VERSION 5.8 ;
BUSBITCHARS "[]" ;
DIVIDERCHAR "/" ;
UNITS
    DATABASE MICRONS 1000 ;
END UNITS

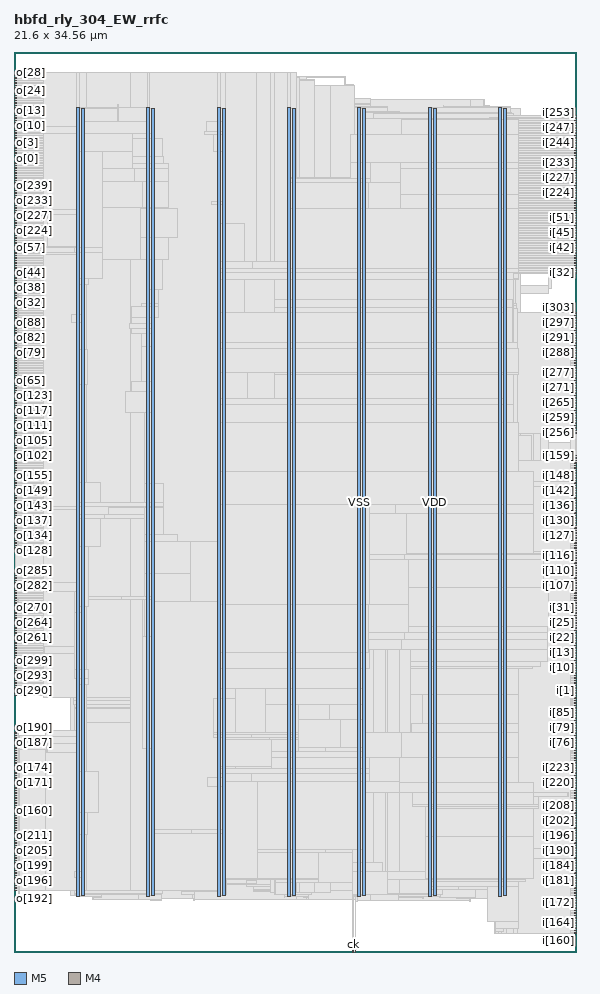
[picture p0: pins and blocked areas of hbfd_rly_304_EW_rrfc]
MACRO hbfd_rly_304_EW_rrfc
  FOREIGN hbfd_rly_304_EW_rrfc 0 0 ;
  CLASS BLOCK ;
  SIZE 21.6 BY 34.56 ;
  PIN ck
    DIRECTION INPUT ;
    USE SIGNAL ;
    PORT
      LAYER M5 ;
        RECT  13.008 0 13.032 0.084 ;
    END
  END ck
  PIN i[0]
    DIRECTION INPUT ;
    USE SIGNAL ;
    PORT
      LAYER M4 ;
        RECT  21.516 9.936 21.6 9.96 ;
    END
  END i[0]
  PIN i[100]
    DIRECTION INPUT ;
    USE SIGNAL ;
    PORT
      LAYER M4 ;
        RECT  21.516 13.392 21.6 13.416 ;
    END
  END i[100]
  PIN i[101]
    DIRECTION INPUT ;
    USE SIGNAL ;
    PORT
      LAYER M4 ;
        RECT  21.516 13.488 21.6 13.512 ;
    END
  END i[101]
  PIN i[102]
    DIRECTION INPUT ;
    USE SIGNAL ;
    PORT
      LAYER M4 ;
        RECT  21.516 13.584 21.6 13.608 ;
    END
  END i[102]
  PIN i[103]
    DIRECTION INPUT ;
    USE SIGNAL ;
    PORT
      LAYER M4 ;
        RECT  21.516 13.68 21.6 13.704 ;
    END
  END i[103]
  PIN i[104]
    DIRECTION INPUT ;
    USE SIGNAL ;
    PORT
      LAYER M4 ;
        RECT  21.516 13.776 21.6 13.8 ;
    END
  END i[104]
  PIN i[105]
    DIRECTION INPUT ;
    USE SIGNAL ;
    PORT
      LAYER M4 ;
        RECT  21.516 13.872 21.6 13.896 ;
    END
  END i[105]
  PIN i[106]
    DIRECTION INPUT ;
    USE SIGNAL ;
    PORT
      LAYER M4 ;
        RECT  21.516 13.968 21.6 13.992 ;
    END
  END i[106]
  PIN i[107]
    DIRECTION INPUT ;
    USE SIGNAL ;
    PORT
      LAYER M4 ;
        RECT  21.516 14.064 21.6 14.088 ;
    END
  END i[107]
  PIN i[108]
    DIRECTION INPUT ;
    USE SIGNAL ;
    PORT
      LAYER M4 ;
        RECT  21.516 14.16 21.6 14.184 ;
    END
  END i[108]
  PIN i[109]
    DIRECTION INPUT ;
    USE SIGNAL ;
    PORT
      LAYER M4 ;
        RECT  21.516 14.256 21.6 14.28 ;
    END
  END i[109]
  PIN i[10]
    DIRECTION INPUT ;
    USE SIGNAL ;
    PORT
      LAYER M4 ;
        RECT  21.516 10.896 21.6 10.92 ;
    END
  END i[10]
  PIN i[110]
    DIRECTION INPUT ;
    USE SIGNAL ;
    PORT
      LAYER M4 ;
        RECT  21.516 14.352 21.6 14.376 ;
    END
  END i[110]
  PIN i[111]
    DIRECTION INPUT ;
    USE SIGNAL ;
    PORT
      LAYER M4 ;
        RECT  21.516 14.448 21.6 14.472 ;
    END
  END i[111]
  PIN i[112]
    DIRECTION INPUT ;
    USE SIGNAL ;
    PORT
      LAYER M4 ;
        RECT  21.516 14.544 21.6 14.568 ;
    END
  END i[112]
  PIN i[113]
    DIRECTION INPUT ;
    USE SIGNAL ;
    PORT
      LAYER M4 ;
        RECT  21.516 14.64 21.6 14.664 ;
    END
  END i[113]
  PIN i[114]
    DIRECTION INPUT ;
    USE SIGNAL ;
    PORT
      LAYER M4 ;
        RECT  21.516 14.736 21.6 14.76 ;
    END
  END i[114]
  PIN i[115]
    DIRECTION INPUT ;
    USE SIGNAL ;
    PORT
      LAYER M4 ;
        RECT  21.516 14.832 21.6 14.856 ;
    END
  END i[115]
  PIN i[116]
    DIRECTION INPUT ;
    USE SIGNAL ;
    PORT
      LAYER M4 ;
        RECT  21.516 14.928 21.6 14.952 ;
    END
  END i[116]
  PIN i[117]
    DIRECTION INPUT ;
    USE SIGNAL ;
    PORT
      LAYER M4 ;
        RECT  21.516 15.024 21.6 15.048 ;
    END
  END i[117]
  PIN i[118]
    DIRECTION INPUT ;
    USE SIGNAL ;
    PORT
      LAYER M4 ;
        RECT  21.516 15.12 21.6 15.144 ;
    END
  END i[118]
  PIN i[119]
    DIRECTION INPUT ;
    USE SIGNAL ;
    PORT
      LAYER M4 ;
        RECT  21.516 15.216 21.6 15.24 ;
    END
  END i[119]
  PIN i[11]
    DIRECTION INPUT ;
    USE SIGNAL ;
    PORT
      LAYER M4 ;
        RECT  21.516 10.992 21.6 11.016 ;
    END
  END i[11]
  PIN i[120]
    DIRECTION INPUT ;
    USE SIGNAL ;
    PORT
      LAYER M4 ;
        RECT  21.516 15.312 21.6 15.336 ;
    END
  END i[120]
  PIN i[121]
    DIRECTION INPUT ;
    USE SIGNAL ;
    PORT
      LAYER M4 ;
        RECT  21.516 15.408 21.6 15.432 ;
    END
  END i[121]
  PIN i[122]
    DIRECTION INPUT ;
    USE SIGNAL ;
    PORT
      LAYER M4 ;
        RECT  21.516 15.504 21.6 15.528 ;
    END
  END i[122]
  PIN i[123]
    DIRECTION INPUT ;
    USE SIGNAL ;
    PORT
      LAYER M4 ;
        RECT  21.516 15.6 21.6 15.624 ;
    END
  END i[123]
  PIN i[124]
    DIRECTION INPUT ;
    USE SIGNAL ;
    PORT
      LAYER M4 ;
        RECT  21.516 15.696 21.6 15.72 ;
    END
  END i[124]
  PIN i[125]
    DIRECTION INPUT ;
    USE SIGNAL ;
    PORT
      LAYER M4 ;
        RECT  21.516 15.792 21.6 15.816 ;
    END
  END i[125]
  PIN i[126]
    DIRECTION INPUT ;
    USE SIGNAL ;
    PORT
      LAYER M4 ;
        RECT  21.516 15.888 21.6 15.912 ;
    END
  END i[126]
  PIN i[127]
    DIRECTION INPUT ;
    USE SIGNAL ;
    PORT
      LAYER M4 ;
        RECT  21.516 15.984 21.6 16.008 ;
    END
  END i[127]
  PIN i[128]
    DIRECTION INPUT ;
    USE SIGNAL ;
    PORT
      LAYER M4 ;
        RECT  21.516 16.08 21.6 16.104 ;
    END
  END i[128]
  PIN i[129]
    DIRECTION INPUT ;
    USE SIGNAL ;
    PORT
      LAYER M4 ;
        RECT  21.516 16.176 21.6 16.2 ;
    END
  END i[129]
  PIN i[12]
    DIRECTION INPUT ;
    USE SIGNAL ;
    PORT
      LAYER M4 ;
        RECT  21.516 11.088 21.6 11.112 ;
    END
  END i[12]
  PIN i[130]
    DIRECTION INPUT ;
    USE SIGNAL ;
    PORT
      LAYER M4 ;
        RECT  21.516 16.272 21.6 16.296 ;
    END
  END i[130]
  PIN i[131]
    DIRECTION INPUT ;
    USE SIGNAL ;
    PORT
      LAYER M4 ;
        RECT  21.516 16.368 21.6 16.392 ;
    END
  END i[131]
  PIN i[132]
    DIRECTION INPUT ;
    USE SIGNAL ;
    PORT
      LAYER M4 ;
        RECT  21.516 16.464 21.6 16.488 ;
    END
  END i[132]
  PIN i[133]
    DIRECTION INPUT ;
    USE SIGNAL ;
    PORT
      LAYER M4 ;
        RECT  21.516 16.56 21.6 16.584 ;
    END
  END i[133]
  PIN i[134]
    DIRECTION INPUT ;
    USE SIGNAL ;
    PORT
      LAYER M4 ;
        RECT  21.516 16.656 21.6 16.68 ;
    END
  END i[134]
  PIN i[135]
    DIRECTION INPUT ;
    USE SIGNAL ;
    PORT
      LAYER M4 ;
        RECT  21.516 16.752 21.6 16.776 ;
    END
  END i[135]
  PIN i[136]
    DIRECTION INPUT ;
    USE SIGNAL ;
    PORT
      LAYER M4 ;
        RECT  21.516 16.848 21.6 16.872 ;
    END
  END i[136]
  PIN i[137]
    DIRECTION INPUT ;
    USE SIGNAL ;
    PORT
      LAYER M4 ;
        RECT  21.516 16.944 21.6 16.968 ;
    END
  END i[137]
  PIN i[138]
    DIRECTION INPUT ;
    USE SIGNAL ;
    PORT
      LAYER M4 ;
        RECT  21.516 17.04 21.6 17.064 ;
    END
  END i[138]
  PIN i[139]
    DIRECTION INPUT ;
    USE SIGNAL ;
    PORT
      LAYER M4 ;
        RECT  21.516 17.136 21.6 17.16 ;
    END
  END i[139]
  PIN i[13]
    DIRECTION INPUT ;
    USE SIGNAL ;
    PORT
      LAYER M4 ;
        RECT  21.516 11.184 21.6 11.208 ;
    END
  END i[13]
  PIN i[140]
    DIRECTION INPUT ;
    USE SIGNAL ;
    PORT
      LAYER M4 ;
        RECT  21.516 17.232 21.6 17.256 ;
    END
  END i[140]
  PIN i[141]
    DIRECTION INPUT ;
    USE SIGNAL ;
    PORT
      LAYER M4 ;
        RECT  21.516 17.328 21.6 17.352 ;
    END
  END i[141]
  PIN i[142]
    DIRECTION INPUT ;
    USE SIGNAL ;
    PORT
      LAYER M4 ;
        RECT  21.516 17.424 21.6 17.448 ;
    END
  END i[142]
  PIN i[143]
    DIRECTION INPUT ;
    USE SIGNAL ;
    PORT
      LAYER M4 ;
        RECT  21.516 17.52 21.6 17.544 ;
    END
  END i[143]
  PIN i[144]
    DIRECTION INPUT ;
    USE SIGNAL ;
    PORT
      LAYER M4 ;
        RECT  21.516 17.616 21.6 17.64 ;
    END
  END i[144]
  PIN i[145]
    DIRECTION INPUT ;
    USE SIGNAL ;
    PORT
      LAYER M4 ;
        RECT  21.516 17.712 21.6 17.736 ;
    END
  END i[145]
  PIN i[146]
    DIRECTION INPUT ;
    USE SIGNAL ;
    PORT
      LAYER M4 ;
        RECT  21.516 17.808 21.6 17.832 ;
    END
  END i[146]
  PIN i[147]
    DIRECTION INPUT ;
    USE SIGNAL ;
    PORT
      LAYER M4 ;
        RECT  21.516 17.904 21.6 17.928 ;
    END
  END i[147]
  PIN i[148]
    DIRECTION INPUT ;
    USE SIGNAL ;
    PORT
      LAYER M4 ;
        RECT  21.516 18 21.6 18.024 ;
    END
  END i[148]
  PIN i[149]
    DIRECTION INPUT ;
    USE SIGNAL ;
    PORT
      LAYER M4 ;
        RECT  21.516 18.096 21.6 18.12 ;
    END
  END i[149]
  PIN i[14]
    DIRECTION INPUT ;
    USE SIGNAL ;
    PORT
      LAYER M4 ;
        RECT  21.516 11.28 21.6 11.304 ;
    END
  END i[14]
  PIN i[150]
    DIRECTION INPUT ;
    USE SIGNAL ;
    PORT
      LAYER M4 ;
        RECT  21.516 18.192 21.6 18.216 ;
    END
  END i[150]
  PIN i[151]
    DIRECTION INPUT ;
    USE SIGNAL ;
    PORT
      LAYER M4 ;
        RECT  21.516 18.288 21.6 18.312 ;
    END
  END i[151]
  PIN i[152]
    DIRECTION INPUT ;
    USE SIGNAL ;
    PORT
      LAYER M4 ;
        RECT  21.516 18.384 21.6 18.408 ;
    END
  END i[152]
  PIN i[153]
    DIRECTION INPUT ;
    USE SIGNAL ;
    PORT
      LAYER M4 ;
        RECT  21.516 18.48 21.6 18.504 ;
    END
  END i[153]
  PIN i[154]
    DIRECTION INPUT ;
    USE SIGNAL ;
    PORT
      LAYER M4 ;
        RECT  21.516 18.576 21.6 18.6 ;
    END
  END i[154]
  PIN i[155]
    DIRECTION INPUT ;
    USE SIGNAL ;
    PORT
      LAYER M4 ;
        RECT  21.516 18.672 21.6 18.696 ;
    END
  END i[155]
  PIN i[156]
    DIRECTION INPUT ;
    USE SIGNAL ;
    PORT
      LAYER M4 ;
        RECT  21.516 18.768 21.6 18.792 ;
    END
  END i[156]
  PIN i[157]
    DIRECTION INPUT ;
    USE SIGNAL ;
    PORT
      LAYER M4 ;
        RECT  21.516 18.864 21.6 18.888 ;
    END
  END i[157]
  PIN i[158]
    DIRECTION INPUT ;
    USE SIGNAL ;
    PORT
      LAYER M4 ;
        RECT  21.516 18.96 21.6 18.984 ;
    END
  END i[158]
  PIN i[159]
    DIRECTION INPUT ;
    USE SIGNAL ;
    PORT
      LAYER M4 ;
        RECT  21.516 19.056 21.6 19.08 ;
    END
  END i[159]
  PIN i[15]
    DIRECTION INPUT ;
    USE SIGNAL ;
    PORT
      LAYER M4 ;
        RECT  21.516 11.376 21.6 11.4 ;
    END
  END i[15]
  PIN i[160]
    DIRECTION INPUT ;
    USE SIGNAL ;
    PORT
      LAYER M4 ;
        RECT  21.516 0.72 21.6 0.744 ;
    END
  END i[160]
  PIN i[161]
    DIRECTION INPUT ;
    USE SIGNAL ;
    PORT
      LAYER M4 ;
        RECT  21.516 0.816 21.6 0.84 ;
    END
  END i[161]
  PIN i[162]
    DIRECTION INPUT ;
    USE SIGNAL ;
    PORT
      LAYER M4 ;
        RECT  21.516 0.912 21.6 0.936 ;
    END
  END i[162]
  PIN i[163]
    DIRECTION INPUT ;
    USE SIGNAL ;
    PORT
      LAYER M4 ;
        RECT  21.516 1.008 21.6 1.032 ;
    END
  END i[163]
  PIN i[164]
    DIRECTION INPUT ;
    USE SIGNAL ;
    PORT
      LAYER M4 ;
        RECT  21.516 1.104 21.6 1.128 ;
    END
  END i[164]
  PIN i[165]
    DIRECTION INPUT ;
    USE SIGNAL ;
    PORT
      LAYER M4 ;
        RECT  21.516 1.2 21.6 1.224 ;
    END
  END i[165]
  PIN i[166]
    DIRECTION INPUT ;
    USE SIGNAL ;
    PORT
      LAYER M4 ;
        RECT  21.516 1.296 21.6 1.32 ;
    END
  END i[166]
  PIN i[167]
    DIRECTION INPUT ;
    USE SIGNAL ;
    PORT
      LAYER M4 ;
        RECT  21.516 1.392 21.6 1.416 ;
    END
  END i[167]
  PIN i[168]
    DIRECTION INPUT ;
    USE SIGNAL ;
    PORT
      LAYER M4 ;
        RECT  21.516 1.488 21.6 1.512 ;
    END
  END i[168]
  PIN i[169]
    DIRECTION INPUT ;
    USE SIGNAL ;
    PORT
      LAYER M4 ;
        RECT  21.516 1.584 21.6 1.608 ;
    END
  END i[169]
  PIN i[16]
    DIRECTION INPUT ;
    USE SIGNAL ;
    PORT
      LAYER M4 ;
        RECT  21.516 11.472 21.6 11.496 ;
    END
  END i[16]
  PIN i[170]
    DIRECTION INPUT ;
    USE SIGNAL ;
    PORT
      LAYER M4 ;
        RECT  21.516 1.68 21.6 1.704 ;
    END
  END i[170]
  PIN i[171]
    DIRECTION INPUT ;
    USE SIGNAL ;
    PORT
      LAYER M4 ;
        RECT  21.516 1.776 21.6 1.8 ;
    END
  END i[171]
  PIN i[172]
    DIRECTION INPUT ;
    USE SIGNAL ;
    PORT
      LAYER M4 ;
        RECT  21.516 1.872 21.6 1.896 ;
    END
  END i[172]
  PIN i[173]
    DIRECTION INPUT ;
    USE SIGNAL ;
    PORT
      LAYER M4 ;
        RECT  21.516 1.968 21.6 1.992 ;
    END
  END i[173]
  PIN i[174]
    DIRECTION INPUT ;
    USE SIGNAL ;
    PORT
      LAYER M4 ;
        RECT  21.516 2.064 21.6 2.088 ;
    END
  END i[174]
  PIN i[175]
    DIRECTION INPUT ;
    USE SIGNAL ;
    PORT
      LAYER M4 ;
        RECT  21.516 2.16 21.6 2.184 ;
    END
  END i[175]
  PIN i[176]
    DIRECTION INPUT ;
    USE SIGNAL ;
    PORT
      LAYER M4 ;
        RECT  21.516 2.256 21.6 2.28 ;
    END
  END i[176]
  PIN i[177]
    DIRECTION INPUT ;
    USE SIGNAL ;
    PORT
      LAYER M4 ;
        RECT  21.516 2.352 21.6 2.376 ;
    END
  END i[177]
  PIN i[178]
    DIRECTION INPUT ;
    USE SIGNAL ;
    PORT
      LAYER M4 ;
        RECT  21.516 2.448 21.6 2.472 ;
    END
  END i[178]
  PIN i[179]
    DIRECTION INPUT ;
    USE SIGNAL ;
    PORT
      LAYER M4 ;
        RECT  21.516 2.544 21.6 2.568 ;
    END
  END i[179]
  PIN i[17]
    DIRECTION INPUT ;
    USE SIGNAL ;
    PORT
      LAYER M4 ;
        RECT  21.516 11.568 21.6 11.592 ;
    END
  END i[17]
  PIN i[180]
    DIRECTION INPUT ;
    USE SIGNAL ;
    PORT
      LAYER M4 ;
        RECT  21.516 2.64 21.6 2.664 ;
    END
  END i[180]
  PIN i[181]
    DIRECTION INPUT ;
    USE SIGNAL ;
    PORT
      LAYER M4 ;
        RECT  21.516 2.736 21.6 2.76 ;
    END
  END i[181]
  PIN i[182]
    DIRECTION INPUT ;
    USE SIGNAL ;
    PORT
      LAYER M4 ;
        RECT  21.516 2.832 21.6 2.856 ;
    END
  END i[182]
  PIN i[183]
    DIRECTION INPUT ;
    USE SIGNAL ;
    PORT
      LAYER M4 ;
        RECT  21.516 2.928 21.6 2.952 ;
    END
  END i[183]
  PIN i[184]
    DIRECTION INPUT ;
    USE SIGNAL ;
    PORT
      LAYER M4 ;
        RECT  21.516 3.024 21.6 3.048 ;
    END
  END i[184]
  PIN i[185]
    DIRECTION INPUT ;
    USE SIGNAL ;
    PORT
      LAYER M4 ;
        RECT  21.516 3.12 21.6 3.144 ;
    END
  END i[185]
  PIN i[186]
    DIRECTION INPUT ;
    USE SIGNAL ;
    PORT
      LAYER M4 ;
        RECT  21.516 3.216 21.6 3.24 ;
    END
  END i[186]
  PIN i[187]
    DIRECTION INPUT ;
    USE SIGNAL ;
    PORT
      LAYER M4 ;
        RECT  21.516 3.312 21.6 3.336 ;
    END
  END i[187]
  PIN i[188]
    DIRECTION INPUT ;
    USE SIGNAL ;
    PORT
      LAYER M4 ;
        RECT  21.516 3.408 21.6 3.432 ;
    END
  END i[188]
  PIN i[189]
    DIRECTION INPUT ;
    USE SIGNAL ;
    PORT
      LAYER M4 ;
        RECT  21.516 3.504 21.6 3.528 ;
    END
  END i[189]
  PIN i[18]
    DIRECTION INPUT ;
    USE SIGNAL ;
    PORT
      LAYER M4 ;
        RECT  21.516 11.664 21.6 11.688 ;
    END
  END i[18]
  PIN i[190]
    DIRECTION INPUT ;
    USE SIGNAL ;
    PORT
      LAYER M4 ;
        RECT  21.516 3.6 21.6 3.624 ;
    END
  END i[190]
  PIN i[191]
    DIRECTION INPUT ;
    USE SIGNAL ;
    PORT
      LAYER M4 ;
        RECT  21.516 3.696 21.6 3.72 ;
    END
  END i[191]
  PIN i[192]
    DIRECTION INPUT ;
    USE SIGNAL ;
    PORT
      LAYER M4 ;
        RECT  21.516 3.792 21.6 3.816 ;
    END
  END i[192]
  PIN i[193]
    DIRECTION INPUT ;
    USE SIGNAL ;
    PORT
      LAYER M4 ;
        RECT  21.516 3.888 21.6 3.912 ;
    END
  END i[193]
  PIN i[194]
    DIRECTION INPUT ;
    USE SIGNAL ;
    PORT
      LAYER M4 ;
        RECT  21.516 3.984 21.6 4.008 ;
    END
  END i[194]
  PIN i[195]
    DIRECTION INPUT ;
    USE SIGNAL ;
    PORT
      LAYER M4 ;
        RECT  21.516 4.08 21.6 4.104 ;
    END
  END i[195]
  PIN i[196]
    DIRECTION INPUT ;
    USE SIGNAL ;
    PORT
      LAYER M4 ;
        RECT  21.516 4.176 21.6 4.2 ;
    END
  END i[196]
  PIN i[197]
    DIRECTION INPUT ;
    USE SIGNAL ;
    PORT
      LAYER M4 ;
        RECT  21.516 4.272 21.6 4.296 ;
    END
  END i[197]
  PIN i[198]
    DIRECTION INPUT ;
    USE SIGNAL ;
    PORT
      LAYER M4 ;
        RECT  21.516 4.368 21.6 4.392 ;
    END
  END i[198]
  PIN i[199]
    DIRECTION INPUT ;
    USE SIGNAL ;
    PORT
      LAYER M4 ;
        RECT  21.516 4.464 21.6 4.488 ;
    END
  END i[199]
  PIN i[19]
    DIRECTION INPUT ;
    USE SIGNAL ;
    PORT
      LAYER M4 ;
        RECT  21.516 11.76 21.6 11.784 ;
    END
  END i[19]
  PIN i[1]
    DIRECTION INPUT ;
    USE SIGNAL ;
    PORT
      LAYER M4 ;
        RECT  21.516 10.032 21.6 10.056 ;
    END
  END i[1]
  PIN i[200]
    DIRECTION INPUT ;
    USE SIGNAL ;
    PORT
      LAYER M4 ;
        RECT  21.516 4.56 21.6 4.584 ;
    END
  END i[200]
  PIN i[201]
    DIRECTION INPUT ;
    USE SIGNAL ;
    PORT
      LAYER M4 ;
        RECT  21.516 4.656 21.6 4.68 ;
    END
  END i[201]
  PIN i[202]
    DIRECTION INPUT ;
    USE SIGNAL ;
    PORT
      LAYER M4 ;
        RECT  21.516 4.752 21.6 4.776 ;
    END
  END i[202]
  PIN i[203]
    DIRECTION INPUT ;
    USE SIGNAL ;
    PORT
      LAYER M4 ;
        RECT  21.516 4.848 21.6 4.872 ;
    END
  END i[203]
  PIN i[204]
    DIRECTION INPUT ;
    USE SIGNAL ;
    PORT
      LAYER M4 ;
        RECT  21.516 4.944 21.6 4.968 ;
    END
  END i[204]
  PIN i[205]
    DIRECTION INPUT ;
    USE SIGNAL ;
    PORT
      LAYER M4 ;
        RECT  21.516 5.04 21.6 5.064 ;
    END
  END i[205]
  PIN i[206]
    DIRECTION INPUT ;
    USE SIGNAL ;
    PORT
      LAYER M4 ;
        RECT  21.516 5.136 21.6 5.16 ;
    END
  END i[206]
  PIN i[207]
    DIRECTION INPUT ;
    USE SIGNAL ;
    PORT
      LAYER M4 ;
        RECT  21.516 5.232 21.6 5.256 ;
    END
  END i[207]
  PIN i[208]
    DIRECTION INPUT ;
    USE SIGNAL ;
    PORT
      LAYER M4 ;
        RECT  21.516 5.328 21.6 5.352 ;
    END
  END i[208]
  PIN i[209]
    DIRECTION INPUT ;
    USE SIGNAL ;
    PORT
      LAYER M4 ;
        RECT  21.516 5.424 21.6 5.448 ;
    END
  END i[209]
  PIN i[20]
    DIRECTION INPUT ;
    USE SIGNAL ;
    PORT
      LAYER M4 ;
        RECT  21.516 11.856 21.6 11.88 ;
    END
  END i[20]
  PIN i[210]
    DIRECTION INPUT ;
    USE SIGNAL ;
    PORT
      LAYER M4 ;
        RECT  21.516 5.52 21.6 5.544 ;
    END
  END i[210]
  PIN i[211]
    DIRECTION INPUT ;
    USE SIGNAL ;
    PORT
      LAYER M4 ;
        RECT  21.516 5.616 21.6 5.64 ;
    END
  END i[211]
  PIN i[212]
    DIRECTION INPUT ;
    USE SIGNAL ;
    PORT
      LAYER M4 ;
        RECT  21.516 5.712 21.6 5.736 ;
    END
  END i[212]
  PIN i[213]
    DIRECTION INPUT ;
    USE SIGNAL ;
    PORT
      LAYER M4 ;
        RECT  21.516 5.808 21.6 5.832 ;
    END
  END i[213]
  PIN i[214]
    DIRECTION INPUT ;
    USE SIGNAL ;
    PORT
      LAYER M4 ;
        RECT  21.516 5.904 21.6 5.928 ;
    END
  END i[214]
  PIN i[215]
    DIRECTION INPUT ;
    USE SIGNAL ;
    PORT
      LAYER M4 ;
        RECT  21.516 6 21.6 6.024 ;
    END
  END i[215]
  PIN i[216]
    DIRECTION INPUT ;
    USE SIGNAL ;
    PORT
      LAYER M4 ;
        RECT  21.516 6.096 21.6 6.12 ;
    END
  END i[216]
  PIN i[217]
    DIRECTION INPUT ;
    USE SIGNAL ;
    PORT
      LAYER M4 ;
        RECT  21.516 6.192 21.6 6.216 ;
    END
  END i[217]
  PIN i[218]
    DIRECTION INPUT ;
    USE SIGNAL ;
    PORT
      LAYER M4 ;
        RECT  21.516 6.288 21.6 6.312 ;
    END
  END i[218]
  PIN i[219]
    DIRECTION INPUT ;
    USE SIGNAL ;
    PORT
      LAYER M4 ;
        RECT  21.516 6.384 21.6 6.408 ;
    END
  END i[219]
  PIN i[21]
    DIRECTION INPUT ;
    USE SIGNAL ;
    PORT
      LAYER M4 ;
        RECT  21.516 11.952 21.6 11.976 ;
    END
  END i[21]
  PIN i[220]
    DIRECTION INPUT ;
    USE SIGNAL ;
    PORT
      LAYER M4 ;
        RECT  21.516 6.48 21.6 6.504 ;
    END
  END i[220]
  PIN i[221]
    DIRECTION INPUT ;
    USE SIGNAL ;
    PORT
      LAYER M4 ;
        RECT  21.516 6.576 21.6 6.6 ;
    END
  END i[221]
  PIN i[222]
    DIRECTION INPUT ;
    USE SIGNAL ;
    PORT
      LAYER M4 ;
        RECT  21.516 6.672 21.6 6.696 ;
    END
  END i[222]
  PIN i[223]
    DIRECTION INPUT ;
    USE SIGNAL ;
    PORT
      LAYER M4 ;
        RECT  21.516 6.768 21.6 6.792 ;
    END
  END i[223]
  PIN i[224]
    DIRECTION INPUT ;
    USE SIGNAL ;
    PORT
      LAYER M4 ;
        RECT  21.516 29.136 21.6 29.16 ;
    END
  END i[224]
  PIN i[225]
    DIRECTION INPUT ;
    USE SIGNAL ;
    PORT
      LAYER M4 ;
        RECT  21.516 29.232 21.6 29.256 ;
    END
  END i[225]
  PIN i[226]
    DIRECTION INPUT ;
    USE SIGNAL ;
    PORT
      LAYER M4 ;
        RECT  21.516 29.328 21.6 29.352 ;
    END
  END i[226]
  PIN i[227]
    DIRECTION INPUT ;
    USE SIGNAL ;
    PORT
      LAYER M4 ;
        RECT  21.516 29.424 21.6 29.448 ;
    END
  END i[227]
  PIN i[228]
    DIRECTION INPUT ;
    USE SIGNAL ;
    PORT
      LAYER M4 ;
        RECT  21.516 29.52 21.6 29.544 ;
    END
  END i[228]
  PIN i[229]
    DIRECTION INPUT ;
    USE SIGNAL ;
    PORT
      LAYER M4 ;
        RECT  21.516 29.616 21.6 29.64 ;
    END
  END i[229]
  PIN i[22]
    DIRECTION INPUT ;
    USE SIGNAL ;
    PORT
      LAYER M4 ;
        RECT  21.516 12.048 21.6 12.072 ;
    END
  END i[22]
  PIN i[230]
    DIRECTION INPUT ;
    USE SIGNAL ;
    PORT
      LAYER M4 ;
        RECT  21.516 29.712 21.6 29.736 ;
    END
  END i[230]
  PIN i[231]
    DIRECTION INPUT ;
    USE SIGNAL ;
    PORT
      LAYER M4 ;
        RECT  21.516 29.808 21.6 29.832 ;
    END
  END i[231]
  PIN i[232]
    DIRECTION INPUT ;
    USE SIGNAL ;
    PORT
      LAYER M4 ;
        RECT  21.516 29.904 21.6 29.928 ;
    END
  END i[232]
  PIN i[233]
    DIRECTION INPUT ;
    USE SIGNAL ;
    PORT
      LAYER M4 ;
        RECT  21.516 30 21.6 30.024 ;
    END
  END i[233]
  PIN i[234]
    DIRECTION INPUT ;
    USE SIGNAL ;
    PORT
      LAYER M4 ;
        RECT  21.516 30.096 21.6 30.12 ;
    END
  END i[234]
  PIN i[235]
    DIRECTION INPUT ;
    USE SIGNAL ;
    PORT
      LAYER M4 ;
        RECT  21.516 30.192 21.6 30.216 ;
    END
  END i[235]
  PIN i[236]
    DIRECTION INPUT ;
    USE SIGNAL ;
    PORT
      LAYER M4 ;
        RECT  21.516 30.288 21.6 30.312 ;
    END
  END i[236]
  PIN i[237]
    DIRECTION INPUT ;
    USE SIGNAL ;
    PORT
      LAYER M4 ;
        RECT  21.516 30.384 21.6 30.408 ;
    END
  END i[237]
  PIN i[238]
    DIRECTION INPUT ;
    USE SIGNAL ;
    PORT
      LAYER M4 ;
        RECT  21.516 30.48 21.6 30.504 ;
    END
  END i[238]
  PIN i[239]
    DIRECTION INPUT ;
    USE SIGNAL ;
    PORT
      LAYER M4 ;
        RECT  21.516 30.576 21.6 30.6 ;
    END
  END i[239]
  PIN i[23]
    DIRECTION INPUT ;
    USE SIGNAL ;
    PORT
      LAYER M4 ;
        RECT  21.516 12.144 21.6 12.168 ;
    END
  END i[23]
  PIN i[240]
    DIRECTION INPUT ;
    USE SIGNAL ;
    PORT
      LAYER M4 ;
        RECT  21.516 30.672 21.6 30.696 ;
    END
  END i[240]
  PIN i[241]
    DIRECTION INPUT ;
    USE SIGNAL ;
    PORT
      LAYER M4 ;
        RECT  21.516 30.768 21.6 30.792 ;
    END
  END i[241]
  PIN i[242]
    DIRECTION INPUT ;
    USE SIGNAL ;
    PORT
      LAYER M4 ;
        RECT  21.516 30.864 21.6 30.888 ;
    END
  END i[242]
  PIN i[243]
    DIRECTION INPUT ;
    USE SIGNAL ;
    PORT
      LAYER M4 ;
        RECT  21.516 30.96 21.6 30.984 ;
    END
  END i[243]
  PIN i[244]
    DIRECTION INPUT ;
    USE SIGNAL ;
    PORT
      LAYER M4 ;
        RECT  21.516 31.056 21.6 31.08 ;
    END
  END i[244]
  PIN i[245]
    DIRECTION INPUT ;
    USE SIGNAL ;
    PORT
      LAYER M4 ;
        RECT  21.516 31.152 21.6 31.176 ;
    END
  END i[245]
  PIN i[246]
    DIRECTION INPUT ;
    USE SIGNAL ;
    PORT
      LAYER M4 ;
        RECT  21.516 31.248 21.6 31.272 ;
    END
  END i[246]
  PIN i[247]
    DIRECTION INPUT ;
    USE SIGNAL ;
    PORT
      LAYER M4 ;
        RECT  21.516 31.344 21.6 31.368 ;
    END
  END i[247]
  PIN i[248]
    DIRECTION INPUT ;
    USE SIGNAL ;
    PORT
      LAYER M4 ;
        RECT  21.516 31.44 21.6 31.464 ;
    END
  END i[248]
  PIN i[249]
    DIRECTION INPUT ;
    USE SIGNAL ;
    PORT
      LAYER M4 ;
        RECT  21.516 31.536 21.6 31.56 ;
    END
  END i[249]
  PIN i[24]
    DIRECTION INPUT ;
    USE SIGNAL ;
    PORT
      LAYER M4 ;
        RECT  21.516 12.24 21.6 12.264 ;
    END
  END i[24]
  PIN i[250]
    DIRECTION INPUT ;
    USE SIGNAL ;
    PORT
      LAYER M4 ;
        RECT  21.516 31.632 21.6 31.656 ;
    END
  END i[250]
  PIN i[251]
    DIRECTION INPUT ;
    USE SIGNAL ;
    PORT
      LAYER M4 ;
        RECT  21.516 31.728 21.6 31.752 ;
    END
  END i[251]
  PIN i[252]
    DIRECTION INPUT ;
    USE SIGNAL ;
    PORT
      LAYER M4 ;
        RECT  21.516 31.824 21.6 31.848 ;
    END
  END i[252]
  PIN i[253]
    DIRECTION INPUT ;
    USE SIGNAL ;
    PORT
      LAYER M4 ;
        RECT  21.516 31.92 21.6 31.944 ;
    END
  END i[253]
  PIN i[254]
    DIRECTION INPUT ;
    USE SIGNAL ;
    PORT
      LAYER M4 ;
        RECT  21.516 32.016 21.6 32.04 ;
    END
  END i[254]
  PIN i[255]
    DIRECTION INPUT ;
    USE SIGNAL ;
    PORT
      LAYER M4 ;
        RECT  21.516 32.112 21.6 32.136 ;
    END
  END i[255]
  PIN i[256]
    DIRECTION INPUT ;
    USE SIGNAL ;
    PORT
      LAYER M4 ;
        RECT  21.516 19.92 21.6 19.944 ;
    END
  END i[256]
  PIN i[257]
    DIRECTION INPUT ;
    USE SIGNAL ;
    PORT
      LAYER M4 ;
        RECT  21.516 20.016 21.6 20.04 ;
    END
  END i[257]
  PIN i[258]
    DIRECTION INPUT ;
    USE SIGNAL ;
    PORT
      LAYER M4 ;
        RECT  21.516 20.112 21.6 20.136 ;
    END
  END i[258]
  PIN i[259]
    DIRECTION INPUT ;
    USE SIGNAL ;
    PORT
      LAYER M4 ;
        RECT  21.516 20.208 21.6 20.232 ;
    END
  END i[259]
  PIN i[25]
    DIRECTION INPUT ;
    USE SIGNAL ;
    PORT
      LAYER M4 ;
        RECT  21.516 12.336 21.6 12.36 ;
    END
  END i[25]
  PIN i[260]
    DIRECTION INPUT ;
    USE SIGNAL ;
    PORT
      LAYER M4 ;
        RECT  21.516 20.304 21.6 20.328 ;
    END
  END i[260]
  PIN i[261]
    DIRECTION INPUT ;
    USE SIGNAL ;
    PORT
      LAYER M4 ;
        RECT  21.516 20.4 21.6 20.424 ;
    END
  END i[261]
  PIN i[262]
    DIRECTION INPUT ;
    USE SIGNAL ;
    PORT
      LAYER M4 ;
        RECT  21.516 20.496 21.6 20.52 ;
    END
  END i[262]
  PIN i[263]
    DIRECTION INPUT ;
    USE SIGNAL ;
    PORT
      LAYER M4 ;
        RECT  21.516 20.592 21.6 20.616 ;
    END
  END i[263]
  PIN i[264]
    DIRECTION INPUT ;
    USE SIGNAL ;
    PORT
      LAYER M4 ;
        RECT  21.516 20.688 21.6 20.712 ;
    END
  END i[264]
  PIN i[265]
    DIRECTION INPUT ;
    USE SIGNAL ;
    PORT
      LAYER M4 ;
        RECT  21.516 20.784 21.6 20.808 ;
    END
  END i[265]
  PIN i[266]
    DIRECTION INPUT ;
    USE SIGNAL ;
    PORT
      LAYER M4 ;
        RECT  21.516 20.88 21.6 20.904 ;
    END
  END i[266]
  PIN i[267]
    DIRECTION INPUT ;
    USE SIGNAL ;
    PORT
      LAYER M4 ;
        RECT  21.516 20.976 21.6 21 ;
    END
  END i[267]
  PIN i[268]
    DIRECTION INPUT ;
    USE SIGNAL ;
    PORT
      LAYER M4 ;
        RECT  21.516 21.072 21.6 21.096 ;
    END
  END i[268]
  PIN i[269]
    DIRECTION INPUT ;
    USE SIGNAL ;
    PORT
      LAYER M4 ;
        RECT  21.516 21.168 21.6 21.192 ;
    END
  END i[269]
  PIN i[26]
    DIRECTION INPUT ;
    USE SIGNAL ;
    PORT
      LAYER M4 ;
        RECT  21.516 12.432 21.6 12.456 ;
    END
  END i[26]
  PIN i[270]
    DIRECTION INPUT ;
    USE SIGNAL ;
    PORT
      LAYER M4 ;
        RECT  21.516 21.264 21.6 21.288 ;
    END
  END i[270]
  PIN i[271]
    DIRECTION INPUT ;
    USE SIGNAL ;
    PORT
      LAYER M4 ;
        RECT  21.516 21.36 21.6 21.384 ;
    END
  END i[271]
  PIN i[272]
    DIRECTION INPUT ;
    USE SIGNAL ;
    PORT
      LAYER M4 ;
        RECT  21.516 21.456 21.6 21.48 ;
    END
  END i[272]
  PIN i[273]
    DIRECTION INPUT ;
    USE SIGNAL ;
    PORT
      LAYER M4 ;
        RECT  21.516 21.552 21.6 21.576 ;
    END
  END i[273]
  PIN i[274]
    DIRECTION INPUT ;
    USE SIGNAL ;
    PORT
      LAYER M4 ;
        RECT  21.516 21.648 21.6 21.672 ;
    END
  END i[274]
  PIN i[275]
    DIRECTION INPUT ;
    USE SIGNAL ;
    PORT
      LAYER M4 ;
        RECT  21.516 21.744 21.6 21.768 ;
    END
  END i[275]
  PIN i[276]
    DIRECTION INPUT ;
    USE SIGNAL ;
    PORT
      LAYER M4 ;
        RECT  21.516 21.84 21.6 21.864 ;
    END
  END i[276]
  PIN i[277]
    DIRECTION INPUT ;
    USE SIGNAL ;
    PORT
      LAYER M4 ;
        RECT  21.516 21.936 21.6 21.96 ;
    END
  END i[277]
  PIN i[278]
    DIRECTION INPUT ;
    USE SIGNAL ;
    PORT
      LAYER M4 ;
        RECT  21.516 22.032 21.6 22.056 ;
    END
  END i[278]
  PIN i[279]
    DIRECTION INPUT ;
    USE SIGNAL ;
    PORT
      LAYER M4 ;
        RECT  21.516 22.128 21.6 22.152 ;
    END
  END i[279]
  PIN i[27]
    DIRECTION INPUT ;
    USE SIGNAL ;
    PORT
      LAYER M4 ;
        RECT  21.516 12.528 21.6 12.552 ;
    END
  END i[27]
  PIN i[280]
    DIRECTION INPUT ;
    USE SIGNAL ;
    PORT
      LAYER M4 ;
        RECT  21.516 22.224 21.6 22.248 ;
    END
  END i[280]
  PIN i[281]
    DIRECTION INPUT ;
    USE SIGNAL ;
    PORT
      LAYER M4 ;
        RECT  21.516 22.32 21.6 22.344 ;
    END
  END i[281]
  PIN i[282]
    DIRECTION INPUT ;
    USE SIGNAL ;
    PORT
      LAYER M4 ;
        RECT  21.516 22.416 21.6 22.44 ;
    END
  END i[282]
  PIN i[283]
    DIRECTION INPUT ;
    USE SIGNAL ;
    PORT
      LAYER M4 ;
        RECT  21.516 22.512 21.6 22.536 ;
    END
  END i[283]
  PIN i[284]
    DIRECTION INPUT ;
    USE SIGNAL ;
    PORT
      LAYER M4 ;
        RECT  21.516 22.608 21.6 22.632 ;
    END
  END i[284]
  PIN i[285]
    DIRECTION INPUT ;
    USE SIGNAL ;
    PORT
      LAYER M4 ;
        RECT  21.516 22.704 21.6 22.728 ;
    END
  END i[285]
  PIN i[286]
    DIRECTION INPUT ;
    USE SIGNAL ;
    PORT
      LAYER M4 ;
        RECT  21.516 22.8 21.6 22.824 ;
    END
  END i[286]
  PIN i[287]
    DIRECTION INPUT ;
    USE SIGNAL ;
    PORT
      LAYER M4 ;
        RECT  21.516 22.896 21.6 22.92 ;
    END
  END i[287]
  PIN i[288]
    DIRECTION INPUT ;
    USE SIGNAL ;
    PORT
      LAYER M4 ;
        RECT  21.516 22.992 21.6 23.016 ;
    END
  END i[288]
  PIN i[289]
    DIRECTION INPUT ;
    USE SIGNAL ;
    PORT
      LAYER M4 ;
        RECT  21.516 23.088 21.6 23.112 ;
    END
  END i[289]
  PIN i[28]
    DIRECTION INPUT ;
    USE SIGNAL ;
    PORT
      LAYER M4 ;
        RECT  21.516 12.624 21.6 12.648 ;
    END
  END i[28]
  PIN i[290]
    DIRECTION INPUT ;
    USE SIGNAL ;
    PORT
      LAYER M4 ;
        RECT  21.516 23.184 21.6 23.208 ;
    END
  END i[290]
  PIN i[291]
    DIRECTION INPUT ;
    USE SIGNAL ;
    PORT
      LAYER M4 ;
        RECT  21.516 23.28 21.6 23.304 ;
    END
  END i[291]
  PIN i[292]
    DIRECTION INPUT ;
    USE SIGNAL ;
    PORT
      LAYER M4 ;
        RECT  21.516 23.376 21.6 23.4 ;
    END
  END i[292]
  PIN i[293]
    DIRECTION INPUT ;
    USE SIGNAL ;
    PORT
      LAYER M4 ;
        RECT  21.516 23.472 21.6 23.496 ;
    END
  END i[293]
  PIN i[294]
    DIRECTION INPUT ;
    USE SIGNAL ;
    PORT
      LAYER M4 ;
        RECT  21.516 23.568 21.6 23.592 ;
    END
  END i[294]
  PIN i[295]
    DIRECTION INPUT ;
    USE SIGNAL ;
    PORT
      LAYER M4 ;
        RECT  21.516 23.664 21.6 23.688 ;
    END
  END i[295]
  PIN i[296]
    DIRECTION INPUT ;
    USE SIGNAL ;
    PORT
      LAYER M4 ;
        RECT  21.516 23.76 21.6 23.784 ;
    END
  END i[296]
  PIN i[297]
    DIRECTION INPUT ;
    USE SIGNAL ;
    PORT
      LAYER M4 ;
        RECT  21.516 23.856 21.6 23.88 ;
    END
  END i[297]
  PIN i[298]
    DIRECTION INPUT ;
    USE SIGNAL ;
    PORT
      LAYER M4 ;
        RECT  21.516 23.952 21.6 23.976 ;
    END
  END i[298]
  PIN i[299]
    DIRECTION INPUT ;
    USE SIGNAL ;
    PORT
      LAYER M4 ;
        RECT  21.516 24.048 21.6 24.072 ;
    END
  END i[299]
  PIN i[29]
    DIRECTION INPUT ;
    USE SIGNAL ;
    PORT
      LAYER M4 ;
        RECT  21.516 12.72 21.6 12.744 ;
    END
  END i[29]
  PIN i[2]
    DIRECTION INPUT ;
    USE SIGNAL ;
    PORT
      LAYER M4 ;
        RECT  21.516 10.128 21.6 10.152 ;
    END
  END i[2]
  PIN i[300]
    DIRECTION INPUT ;
    USE SIGNAL ;
    PORT
      LAYER M4 ;
        RECT  21.516 24.144 21.6 24.168 ;
    END
  END i[300]
  PIN i[301]
    DIRECTION INPUT ;
    USE SIGNAL ;
    PORT
      LAYER M4 ;
        RECT  21.516 24.24 21.6 24.264 ;
    END
  END i[301]
  PIN i[302]
    DIRECTION INPUT ;
    USE SIGNAL ;
    PORT
      LAYER M4 ;
        RECT  21.516 24.336 21.6 24.36 ;
    END
  END i[302]
  PIN i[303]
    DIRECTION INPUT ;
    USE SIGNAL ;
    PORT
      LAYER M4 ;
        RECT  21.516 24.432 21.6 24.456 ;
    END
  END i[303]
  PIN i[30]
    DIRECTION INPUT ;
    USE SIGNAL ;
    PORT
      LAYER M4 ;
        RECT  21.516 12.816 21.6 12.84 ;
    END
  END i[30]
  PIN i[31]
    DIRECTION INPUT ;
    USE SIGNAL ;
    PORT
      LAYER M4 ;
        RECT  21.516 12.912 21.6 12.936 ;
    END
  END i[31]
  PIN i[32]
    DIRECTION INPUT ;
    USE SIGNAL ;
    PORT
      LAYER M4 ;
        RECT  21.516 26.064 21.6 26.088 ;
    END
  END i[32]
  PIN i[33]
    DIRECTION INPUT ;
    USE SIGNAL ;
    PORT
      LAYER M4 ;
        RECT  21.516 26.16 21.6 26.184 ;
    END
  END i[33]
  PIN i[34]
    DIRECTION INPUT ;
    USE SIGNAL ;
    PORT
      LAYER M4 ;
        RECT  21.516 26.256 21.6 26.28 ;
    END
  END i[34]
  PIN i[35]
    DIRECTION INPUT ;
    USE SIGNAL ;
    PORT
      LAYER M4 ;
        RECT  21.516 26.352 21.6 26.376 ;
    END
  END i[35]
  PIN i[36]
    DIRECTION INPUT ;
    USE SIGNAL ;
    PORT
      LAYER M4 ;
        RECT  21.516 26.448 21.6 26.472 ;
    END
  END i[36]
  PIN i[37]
    DIRECTION INPUT ;
    USE SIGNAL ;
    PORT
      LAYER M4 ;
        RECT  21.516 26.544 21.6 26.568 ;
    END
  END i[37]
  PIN i[38]
    DIRECTION INPUT ;
    USE SIGNAL ;
    PORT
      LAYER M4 ;
        RECT  21.516 26.64 21.6 26.664 ;
    END
  END i[38]
  PIN i[39]
    DIRECTION INPUT ;
    USE SIGNAL ;
    PORT
      LAYER M4 ;
        RECT  21.516 26.736 21.6 26.76 ;
    END
  END i[39]
  PIN i[3]
    DIRECTION INPUT ;
    USE SIGNAL ;
    PORT
      LAYER M4 ;
        RECT  21.516 10.224 21.6 10.248 ;
    END
  END i[3]
  PIN i[40]
    DIRECTION INPUT ;
    USE SIGNAL ;
    PORT
      LAYER M4 ;
        RECT  21.516 26.832 21.6 26.856 ;
    END
  END i[40]
  PIN i[41]
    DIRECTION INPUT ;
    USE SIGNAL ;
    PORT
      LAYER M4 ;
        RECT  21.516 26.928 21.6 26.952 ;
    END
  END i[41]
  PIN i[42]
    DIRECTION INPUT ;
    USE SIGNAL ;
    PORT
      LAYER M4 ;
        RECT  21.516 27.024 21.6 27.048 ;
    END
  END i[42]
  PIN i[43]
    DIRECTION INPUT ;
    USE SIGNAL ;
    PORT
      LAYER M4 ;
        RECT  21.516 27.12 21.6 27.144 ;
    END
  END i[43]
  PIN i[44]
    DIRECTION INPUT ;
    USE SIGNAL ;
    PORT
      LAYER M4 ;
        RECT  21.516 27.216 21.6 27.24 ;
    END
  END i[44]
  PIN i[45]
    DIRECTION INPUT ;
    USE SIGNAL ;
    PORT
      LAYER M4 ;
        RECT  21.516 27.312 21.6 27.336 ;
    END
  END i[45]
  PIN i[46]
    DIRECTION INPUT ;
    USE SIGNAL ;
    PORT
      LAYER M4 ;
        RECT  21.516 27.408 21.6 27.432 ;
    END
  END i[46]
  PIN i[47]
    DIRECTION INPUT ;
    USE SIGNAL ;
    PORT
      LAYER M4 ;
        RECT  21.516 27.504 21.6 27.528 ;
    END
  END i[47]
  PIN i[48]
    DIRECTION INPUT ;
    USE SIGNAL ;
    PORT
      LAYER M4 ;
        RECT  21.516 27.6 21.6 27.624 ;
    END
  END i[48]
  PIN i[49]
    DIRECTION INPUT ;
    USE SIGNAL ;
    PORT
      LAYER M4 ;
        RECT  21.516 27.696 21.6 27.72 ;
    END
  END i[49]
  PIN i[4]
    DIRECTION INPUT ;
    USE SIGNAL ;
    PORT
      LAYER M4 ;
        RECT  21.516 10.32 21.6 10.344 ;
    END
  END i[4]
  PIN i[50]
    DIRECTION INPUT ;
    USE SIGNAL ;
    PORT
      LAYER M4 ;
        RECT  21.516 27.792 21.6 27.816 ;
    END
  END i[50]
  PIN i[51]
    DIRECTION INPUT ;
    USE SIGNAL ;
    PORT
      LAYER M4 ;
        RECT  21.516 27.888 21.6 27.912 ;
    END
  END i[51]
  PIN i[52]
    DIRECTION INPUT ;
    USE SIGNAL ;
    PORT
      LAYER M4 ;
        RECT  21.516 27.984 21.6 28.008 ;
    END
  END i[52]
  PIN i[53]
    DIRECTION INPUT ;
    USE SIGNAL ;
    PORT
      LAYER M4 ;
        RECT  21.516 28.08 21.6 28.104 ;
    END
  END i[53]
  PIN i[54]
    DIRECTION INPUT ;
    USE SIGNAL ;
    PORT
      LAYER M4 ;
        RECT  21.516 28.176 21.6 28.2 ;
    END
  END i[54]
  PIN i[55]
    DIRECTION INPUT ;
    USE SIGNAL ;
    PORT
      LAYER M4 ;
        RECT  21.516 28.272 21.6 28.296 ;
    END
  END i[55]
  PIN i[56]
    DIRECTION INPUT ;
    USE SIGNAL ;
    PORT
      LAYER M4 ;
        RECT  21.516 28.368 21.6 28.392 ;
    END
  END i[56]
  PIN i[57]
    DIRECTION INPUT ;
    USE SIGNAL ;
    PORT
      LAYER M4 ;
        RECT  21.516 28.464 21.6 28.488 ;
    END
  END i[57]
  PIN i[58]
    DIRECTION INPUT ;
    USE SIGNAL ;
    PORT
      LAYER M4 ;
        RECT  21.516 28.56 21.6 28.584 ;
    END
  END i[58]
  PIN i[59]
    DIRECTION INPUT ;
    USE SIGNAL ;
    PORT
      LAYER M4 ;
        RECT  21.516 28.656 21.6 28.68 ;
    END
  END i[59]
  PIN i[5]
    DIRECTION INPUT ;
    USE SIGNAL ;
    PORT
      LAYER M4 ;
        RECT  21.516 10.416 21.6 10.44 ;
    END
  END i[5]
  PIN i[60]
    DIRECTION INPUT ;
    USE SIGNAL ;
    PORT
      LAYER M4 ;
        RECT  21.516 28.752 21.6 28.776 ;
    END
  END i[60]
  PIN i[61]
    DIRECTION INPUT ;
    USE SIGNAL ;
    PORT
      LAYER M4 ;
        RECT  21.516 28.848 21.6 28.872 ;
    END
  END i[61]
  PIN i[62]
    DIRECTION INPUT ;
    USE SIGNAL ;
    PORT
      LAYER M4 ;
        RECT  21.516 28.944 21.6 28.968 ;
    END
  END i[62]
  PIN i[63]
    DIRECTION INPUT ;
    USE SIGNAL ;
    PORT
      LAYER M4 ;
        RECT  21.516 29.04 21.6 29.064 ;
    END
  END i[63]
  PIN i[64]
    DIRECTION INPUT ;
    USE SIGNAL ;
    PORT
      LAYER M4 ;
        RECT  21.516 6.864 21.6 6.888 ;
    END
  END i[64]
  PIN i[65]
    DIRECTION INPUT ;
    USE SIGNAL ;
    PORT
      LAYER M4 ;
        RECT  21.516 6.96 21.6 6.984 ;
    END
  END i[65]
  PIN i[66]
    DIRECTION INPUT ;
    USE SIGNAL ;
    PORT
      LAYER M4 ;
        RECT  21.516 7.056 21.6 7.08 ;
    END
  END i[66]
  PIN i[67]
    DIRECTION INPUT ;
    USE SIGNAL ;
    PORT
      LAYER M4 ;
        RECT  21.516 7.152 21.6 7.176 ;
    END
  END i[67]
  PIN i[68]
    DIRECTION INPUT ;
    USE SIGNAL ;
    PORT
      LAYER M4 ;
        RECT  21.516 7.248 21.6 7.272 ;
    END
  END i[68]
  PIN i[69]
    DIRECTION INPUT ;
    USE SIGNAL ;
    PORT
      LAYER M4 ;
        RECT  21.516 7.344 21.6 7.368 ;
    END
  END i[69]
  PIN i[6]
    DIRECTION INPUT ;
    USE SIGNAL ;
    PORT
      LAYER M4 ;
        RECT  21.516 10.512 21.6 10.536 ;
    END
  END i[6]
  PIN i[70]
    DIRECTION INPUT ;
    USE SIGNAL ;
    PORT
      LAYER M4 ;
        RECT  21.516 7.44 21.6 7.464 ;
    END
  END i[70]
  PIN i[71]
    DIRECTION INPUT ;
    USE SIGNAL ;
    PORT
      LAYER M4 ;
        RECT  21.516 7.536 21.6 7.56 ;
    END
  END i[71]
  PIN i[72]
    DIRECTION INPUT ;
    USE SIGNAL ;
    PORT
      LAYER M4 ;
        RECT  21.516 7.632 21.6 7.656 ;
    END
  END i[72]
  PIN i[73]
    DIRECTION INPUT ;
    USE SIGNAL ;
    PORT
      LAYER M4 ;
        RECT  21.516 7.728 21.6 7.752 ;
    END
  END i[73]
  PIN i[74]
    DIRECTION INPUT ;
    USE SIGNAL ;
    PORT
      LAYER M4 ;
        RECT  21.516 7.824 21.6 7.848 ;
    END
  END i[74]
  PIN i[75]
    DIRECTION INPUT ;
    USE SIGNAL ;
    PORT
      LAYER M4 ;
        RECT  21.516 7.92 21.6 7.944 ;
    END
  END i[75]
  PIN i[76]
    DIRECTION INPUT ;
    USE SIGNAL ;
    PORT
      LAYER M4 ;
        RECT  21.516 8.016 21.6 8.04 ;
    END
  END i[76]
  PIN i[77]
    DIRECTION INPUT ;
    USE SIGNAL ;
    PORT
      LAYER M4 ;
        RECT  21.516 8.112 21.6 8.136 ;
    END
  END i[77]
  PIN i[78]
    DIRECTION INPUT ;
    USE SIGNAL ;
    PORT
      LAYER M4 ;
        RECT  21.516 8.208 21.6 8.232 ;
    END
  END i[78]
  PIN i[79]
    DIRECTION INPUT ;
    USE SIGNAL ;
    PORT
      LAYER M4 ;
        RECT  21.516 8.304 21.6 8.328 ;
    END
  END i[79]
  PIN i[7]
    DIRECTION INPUT ;
    USE SIGNAL ;
    PORT
      LAYER M4 ;
        RECT  21.516 10.608 21.6 10.632 ;
    END
  END i[7]
  PIN i[80]
    DIRECTION INPUT ;
    USE SIGNAL ;
    PORT
      LAYER M4 ;
        RECT  21.516 8.4 21.6 8.424 ;
    END
  END i[80]
  PIN i[81]
    DIRECTION INPUT ;
    USE SIGNAL ;
    PORT
      LAYER M4 ;
        RECT  21.516 8.496 21.6 8.52 ;
    END
  END i[81]
  PIN i[82]
    DIRECTION INPUT ;
    USE SIGNAL ;
    PORT
      LAYER M4 ;
        RECT  21.516 8.592 21.6 8.616 ;
    END
  END i[82]
  PIN i[83]
    DIRECTION INPUT ;
    USE SIGNAL ;
    PORT
      LAYER M4 ;
        RECT  21.516 8.688 21.6 8.712 ;
    END
  END i[83]
  PIN i[84]
    DIRECTION INPUT ;
    USE SIGNAL ;
    PORT
      LAYER M4 ;
        RECT  21.516 8.784 21.6 8.808 ;
    END
  END i[84]
  PIN i[85]
    DIRECTION INPUT ;
    USE SIGNAL ;
    PORT
      LAYER M4 ;
        RECT  21.516 8.88 21.6 8.904 ;
    END
  END i[85]
  PIN i[86]
    DIRECTION INPUT ;
    USE SIGNAL ;
    PORT
      LAYER M4 ;
        RECT  21.516 8.976 21.6 9 ;
    END
  END i[86]
  PIN i[87]
    DIRECTION INPUT ;
    USE SIGNAL ;
    PORT
      LAYER M4 ;
        RECT  21.516 9.072 21.6 9.096 ;
    END
  END i[87]
  PIN i[88]
    DIRECTION INPUT ;
    USE SIGNAL ;
    PORT
      LAYER M4 ;
        RECT  21.516 9.168 21.6 9.192 ;
    END
  END i[88]
  PIN i[89]
    DIRECTION INPUT ;
    USE SIGNAL ;
    PORT
      LAYER M4 ;
        RECT  21.516 9.264 21.6 9.288 ;
    END
  END i[89]
  PIN i[8]
    DIRECTION INPUT ;
    USE SIGNAL ;
    PORT
      LAYER M4 ;
        RECT  21.516 10.704 21.6 10.728 ;
    END
  END i[8]
  PIN i[90]
    DIRECTION INPUT ;
    USE SIGNAL ;
    PORT
      LAYER M4 ;
        RECT  21.516 9.36 21.6 9.384 ;
    END
  END i[90]
  PIN i[91]
    DIRECTION INPUT ;
    USE SIGNAL ;
    PORT
      LAYER M4 ;
        RECT  21.516 9.456 21.6 9.48 ;
    END
  END i[91]
  PIN i[92]
    DIRECTION INPUT ;
    USE SIGNAL ;
    PORT
      LAYER M4 ;
        RECT  21.516 9.552 21.6 9.576 ;
    END
  END i[92]
  PIN i[93]
    DIRECTION INPUT ;
    USE SIGNAL ;
    PORT
      LAYER M4 ;
        RECT  21.516 9.648 21.6 9.672 ;
    END
  END i[93]
  PIN i[94]
    DIRECTION INPUT ;
    USE SIGNAL ;
    PORT
      LAYER M4 ;
        RECT  21.516 9.744 21.6 9.768 ;
    END
  END i[94]
  PIN i[95]
    DIRECTION INPUT ;
    USE SIGNAL ;
    PORT
      LAYER M4 ;
        RECT  21.516 9.84 21.6 9.864 ;
    END
  END i[95]
  PIN i[96]
    DIRECTION INPUT ;
    USE SIGNAL ;
    PORT
      LAYER M4 ;
        RECT  21.516 13.008 21.6 13.032 ;
    END
  END i[96]
  PIN i[97]
    DIRECTION INPUT ;
    USE SIGNAL ;
    PORT
      LAYER M4 ;
        RECT  21.516 13.104 21.6 13.128 ;
    END
  END i[97]
  PIN i[98]
    DIRECTION INPUT ;
    USE SIGNAL ;
    PORT
      LAYER M4 ;
        RECT  21.516 13.2 21.6 13.224 ;
    END
  END i[98]
  PIN i[99]
    DIRECTION INPUT ;
    USE SIGNAL ;
    PORT
      LAYER M4 ;
        RECT  21.516 13.296 21.6 13.32 ;
    END
  END i[99]
  PIN i[9]
    DIRECTION INPUT ;
    USE SIGNAL ;
    PORT
      LAYER M4 ;
        RECT  21.516 10.8 21.6 10.824 ;
    END
  END i[9]
  PIN o[0]
    DIRECTION OUTPUT ;
    USE SIGNAL ;
    PORT
      LAYER M4 ;
        RECT  0 30.768 0.084 30.792 ;
    END
  END o[0]
  PIN o[100]
    DIRECTION OUTPUT ;
    USE SIGNAL ;
    PORT
      LAYER M4 ;
        RECT  0 18.864 0.084 18.888 ;
    END
  END o[100]
  PIN o[101]
    DIRECTION OUTPUT ;
    USE SIGNAL ;
    PORT
      LAYER M4 ;
        RECT  0 18.96 0.084 18.984 ;
    END
  END o[101]
  PIN o[102]
    DIRECTION OUTPUT ;
    USE SIGNAL ;
    PORT
      LAYER M4 ;
        RECT  0 19.056 0.084 19.08 ;
    END
  END o[102]
  PIN o[103]
    DIRECTION OUTPUT ;
    USE SIGNAL ;
    PORT
      LAYER M4 ;
        RECT  0 19.152 0.084 19.176 ;
    END
  END o[103]
  PIN o[104]
    DIRECTION OUTPUT ;
    USE SIGNAL ;
    PORT
      LAYER M4 ;
        RECT  0 19.248 0.084 19.272 ;
    END
  END o[104]
  PIN o[105]
    DIRECTION OUTPUT ;
    USE SIGNAL ;
    PORT
      LAYER M4 ;
        RECT  0 19.344 0.084 19.368 ;
    END
  END o[105]
  PIN o[106]
    DIRECTION OUTPUT ;
    USE SIGNAL ;
    PORT
      LAYER M4 ;
        RECT  0 19.44 0.084 19.464 ;
    END
  END o[106]
  PIN o[107]
    DIRECTION OUTPUT ;
    USE SIGNAL ;
    PORT
      LAYER M4 ;
        RECT  0 19.536 0.084 19.56 ;
    END
  END o[107]
  PIN o[108]
    DIRECTION OUTPUT ;
    USE SIGNAL ;
    PORT
      LAYER M4 ;
        RECT  0 19.632 0.084 19.656 ;
    END
  END o[108]
  PIN o[109]
    DIRECTION OUTPUT ;
    USE SIGNAL ;
    PORT
      LAYER M4 ;
        RECT  0 19.728 0.084 19.752 ;
    END
  END o[109]
  PIN o[10]
    DIRECTION OUTPUT ;
    USE SIGNAL ;
    PORT
      LAYER M4 ;
        RECT  0 31.728 0.084 31.752 ;
    END
  END o[10]
  PIN o[110]
    DIRECTION OUTPUT ;
    USE SIGNAL ;
    PORT
      LAYER M4 ;
        RECT  0 19.824 0.084 19.848 ;
    END
  END o[110]
  PIN o[111]
    DIRECTION OUTPUT ;
    USE SIGNAL ;
    PORT
      LAYER M4 ;
        RECT  0 19.92 0.084 19.944 ;
    END
  END o[111]
  PIN o[112]
    DIRECTION OUTPUT ;
    USE SIGNAL ;
    PORT
      LAYER M4 ;
        RECT  0 20.016 0.084 20.04 ;
    END
  END o[112]
  PIN o[113]
    DIRECTION OUTPUT ;
    USE SIGNAL ;
    PORT
      LAYER M4 ;
        RECT  0 20.112 0.084 20.136 ;
    END
  END o[113]
  PIN o[114]
    DIRECTION OUTPUT ;
    USE SIGNAL ;
    PORT
      LAYER M4 ;
        RECT  0 20.208 0.084 20.232 ;
    END
  END o[114]
  PIN o[115]
    DIRECTION OUTPUT ;
    USE SIGNAL ;
    PORT
      LAYER M4 ;
        RECT  0 20.304 0.084 20.328 ;
    END
  END o[115]
  PIN o[116]
    DIRECTION OUTPUT ;
    USE SIGNAL ;
    PORT
      LAYER M4 ;
        RECT  0 20.4 0.084 20.424 ;
    END
  END o[116]
  PIN o[117]
    DIRECTION OUTPUT ;
    USE SIGNAL ;
    PORT
      LAYER M4 ;
        RECT  0 20.496 0.084 20.52 ;
    END
  END o[117]
  PIN o[118]
    DIRECTION OUTPUT ;
    USE SIGNAL ;
    PORT
      LAYER M4 ;
        RECT  0 20.592 0.084 20.616 ;
    END
  END o[118]
  PIN o[119]
    DIRECTION OUTPUT ;
    USE SIGNAL ;
    PORT
      LAYER M4 ;
        RECT  0 20.688 0.084 20.712 ;
    END
  END o[119]
  PIN o[11]
    DIRECTION OUTPUT ;
    USE SIGNAL ;
    PORT
      LAYER M4 ;
        RECT  0 31.824 0.084 31.848 ;
    END
  END o[11]
  PIN o[120]
    DIRECTION OUTPUT ;
    USE SIGNAL ;
    PORT
      LAYER M4 ;
        RECT  0 20.784 0.084 20.808 ;
    END
  END o[120]
  PIN o[121]
    DIRECTION OUTPUT ;
    USE SIGNAL ;
    PORT
      LAYER M4 ;
        RECT  0 20.88 0.084 20.904 ;
    END
  END o[121]
  PIN o[122]
    DIRECTION OUTPUT ;
    USE SIGNAL ;
    PORT
      LAYER M4 ;
        RECT  0 20.976 0.084 21 ;
    END
  END o[122]
  PIN o[123]
    DIRECTION OUTPUT ;
    USE SIGNAL ;
    PORT
      LAYER M4 ;
        RECT  0 21.072 0.084 21.096 ;
    END
  END o[123]
  PIN o[124]
    DIRECTION OUTPUT ;
    USE SIGNAL ;
    PORT
      LAYER M4 ;
        RECT  0 21.168 0.084 21.192 ;
    END
  END o[124]
  PIN o[125]
    DIRECTION OUTPUT ;
    USE SIGNAL ;
    PORT
      LAYER M4 ;
        RECT  0 21.264 0.084 21.288 ;
    END
  END o[125]
  PIN o[126]
    DIRECTION OUTPUT ;
    USE SIGNAL ;
    PORT
      LAYER M4 ;
        RECT  0 21.36 0.084 21.384 ;
    END
  END o[126]
  PIN o[127]
    DIRECTION OUTPUT ;
    USE SIGNAL ;
    PORT
      LAYER M4 ;
        RECT  0 21.456 0.084 21.48 ;
    END
  END o[127]
  PIN o[128]
    DIRECTION OUTPUT ;
    USE SIGNAL ;
    PORT
      LAYER M4 ;
        RECT  0 15.408 0.084 15.432 ;
    END
  END o[128]
  PIN o[129]
    DIRECTION OUTPUT ;
    USE SIGNAL ;
    PORT
      LAYER M4 ;
        RECT  0 15.504 0.084 15.528 ;
    END
  END o[129]
  PIN o[12]
    DIRECTION OUTPUT ;
    USE SIGNAL ;
    PORT
      LAYER M4 ;
        RECT  0 31.92 0.084 31.944 ;
    END
  END o[12]
  PIN o[130]
    DIRECTION OUTPUT ;
    USE SIGNAL ;
    PORT
      LAYER M4 ;
        RECT  0 15.6 0.084 15.624 ;
    END
  END o[130]
  PIN o[131]
    DIRECTION OUTPUT ;
    USE SIGNAL ;
    PORT
      LAYER M4 ;
        RECT  0 15.696 0.084 15.72 ;
    END
  END o[131]
  PIN o[132]
    DIRECTION OUTPUT ;
    USE SIGNAL ;
    PORT
      LAYER M4 ;
        RECT  0 15.792 0.084 15.816 ;
    END
  END o[132]
  PIN o[133]
    DIRECTION OUTPUT ;
    USE SIGNAL ;
    PORT
      LAYER M4 ;
        RECT  0 15.888 0.084 15.912 ;
    END
  END o[133]
  PIN o[134]
    DIRECTION OUTPUT ;
    USE SIGNAL ;
    PORT
      LAYER M4 ;
        RECT  0 15.984 0.084 16.008 ;
    END
  END o[134]
  PIN o[135]
    DIRECTION OUTPUT ;
    USE SIGNAL ;
    PORT
      LAYER M4 ;
        RECT  0 16.08 0.084 16.104 ;
    END
  END o[135]
  PIN o[136]
    DIRECTION OUTPUT ;
    USE SIGNAL ;
    PORT
      LAYER M4 ;
        RECT  0 16.176 0.084 16.2 ;
    END
  END o[136]
  PIN o[137]
    DIRECTION OUTPUT ;
    USE SIGNAL ;
    PORT
      LAYER M4 ;
        RECT  0 16.272 0.084 16.296 ;
    END
  END o[137]
  PIN o[138]
    DIRECTION OUTPUT ;
    USE SIGNAL ;
    PORT
      LAYER M4 ;
        RECT  0 16.368 0.084 16.392 ;
    END
  END o[138]
  PIN o[139]
    DIRECTION OUTPUT ;
    USE SIGNAL ;
    PORT
      LAYER M4 ;
        RECT  0 16.464 0.084 16.488 ;
    END
  END o[139]
  PIN o[13]
    DIRECTION OUTPUT ;
    USE SIGNAL ;
    PORT
      LAYER M4 ;
        RECT  0 32.016 0.084 32.04 ;
    END
  END o[13]
  PIN o[140]
    DIRECTION OUTPUT ;
    USE SIGNAL ;
    PORT
      LAYER M4 ;
        RECT  0 16.56 0.084 16.584 ;
    END
  END o[140]
  PIN o[141]
    DIRECTION OUTPUT ;
    USE SIGNAL ;
    PORT
      LAYER M4 ;
        RECT  0 16.656 0.084 16.68 ;
    END
  END o[141]
  PIN o[142]
    DIRECTION OUTPUT ;
    USE SIGNAL ;
    PORT
      LAYER M4 ;
        RECT  0 16.752 0.084 16.776 ;
    END
  END o[142]
  PIN o[143]
    DIRECTION OUTPUT ;
    USE SIGNAL ;
    PORT
      LAYER M4 ;
        RECT  0 16.848 0.084 16.872 ;
    END
  END o[143]
  PIN o[144]
    DIRECTION OUTPUT ;
    USE SIGNAL ;
    PORT
      LAYER M4 ;
        RECT  0 16.944 0.084 16.968 ;
    END
  END o[144]
  PIN o[145]
    DIRECTION OUTPUT ;
    USE SIGNAL ;
    PORT
      LAYER M4 ;
        RECT  0 17.04 0.084 17.064 ;
    END
  END o[145]
  PIN o[146]
    DIRECTION OUTPUT ;
    USE SIGNAL ;
    PORT
      LAYER M4 ;
        RECT  0 17.136 0.084 17.16 ;
    END
  END o[146]
  PIN o[147]
    DIRECTION OUTPUT ;
    USE SIGNAL ;
    PORT
      LAYER M4 ;
        RECT  0 17.232 0.084 17.256 ;
    END
  END o[147]
  PIN o[148]
    DIRECTION OUTPUT ;
    USE SIGNAL ;
    PORT
      LAYER M4 ;
        RECT  0 17.328 0.084 17.352 ;
    END
  END o[148]
  PIN o[149]
    DIRECTION OUTPUT ;
    USE SIGNAL ;
    PORT
      LAYER M4 ;
        RECT  0 17.424 0.084 17.448 ;
    END
  END o[149]
  PIN o[14]
    DIRECTION OUTPUT ;
    USE SIGNAL ;
    PORT
      LAYER M4 ;
        RECT  0 32.112 0.084 32.136 ;
    END
  END o[14]
  PIN o[150]
    DIRECTION OUTPUT ;
    USE SIGNAL ;
    PORT
      LAYER M4 ;
        RECT  0 17.52 0.084 17.544 ;
    END
  END o[150]
  PIN o[151]
    DIRECTION OUTPUT ;
    USE SIGNAL ;
    PORT
      LAYER M4 ;
        RECT  0 17.616 0.084 17.64 ;
    END
  END o[151]
  PIN o[152]
    DIRECTION OUTPUT ;
    USE SIGNAL ;
    PORT
      LAYER M4 ;
        RECT  0 17.712 0.084 17.736 ;
    END
  END o[152]
  PIN o[153]
    DIRECTION OUTPUT ;
    USE SIGNAL ;
    PORT
      LAYER M4 ;
        RECT  0 17.808 0.084 17.832 ;
    END
  END o[153]
  PIN o[154]
    DIRECTION OUTPUT ;
    USE SIGNAL ;
    PORT
      LAYER M4 ;
        RECT  0 17.904 0.084 17.928 ;
    END
  END o[154]
  PIN o[155]
    DIRECTION OUTPUT ;
    USE SIGNAL ;
    PORT
      LAYER M4 ;
        RECT  0 18 0.084 18.024 ;
    END
  END o[155]
  PIN o[156]
    DIRECTION OUTPUT ;
    USE SIGNAL ;
    PORT
      LAYER M4 ;
        RECT  0 18.096 0.084 18.12 ;
    END
  END o[156]
  PIN o[157]
    DIRECTION OUTPUT ;
    USE SIGNAL ;
    PORT
      LAYER M4 ;
        RECT  0 18.192 0.084 18.216 ;
    END
  END o[157]
  PIN o[158]
    DIRECTION OUTPUT ;
    USE SIGNAL ;
    PORT
      LAYER M4 ;
        RECT  0 18.288 0.084 18.312 ;
    END
  END o[158]
  PIN o[159]
    DIRECTION OUTPUT ;
    USE SIGNAL ;
    PORT
      LAYER M4 ;
        RECT  0 18.384 0.084 18.408 ;
    END
  END o[159]
  PIN o[15]
    DIRECTION OUTPUT ;
    USE SIGNAL ;
    PORT
      LAYER M4 ;
        RECT  0 32.208 0.084 32.232 ;
    END
  END o[15]
  PIN o[160]
    DIRECTION OUTPUT ;
    USE SIGNAL ;
    PORT
      LAYER M4 ;
        RECT  0 5.424 0.084 5.448 ;
    END
  END o[160]
  PIN o[161]
    DIRECTION OUTPUT ;
    USE SIGNAL ;
    PORT
      LAYER M4 ;
        RECT  0 5.52 0.084 5.544 ;
    END
  END o[161]
  PIN o[162]
    DIRECTION OUTPUT ;
    USE SIGNAL ;
    PORT
      LAYER M4 ;
        RECT  0 5.616 0.084 5.64 ;
    END
  END o[162]
  PIN o[163]
    DIRECTION OUTPUT ;
    USE SIGNAL ;
    PORT
      LAYER M4 ;
        RECT  0 5.712 0.084 5.736 ;
    END
  END o[163]
  PIN o[164]
    DIRECTION OUTPUT ;
    USE SIGNAL ;
    PORT
      LAYER M4 ;
        RECT  0 5.808 0.084 5.832 ;
    END
  END o[164]
  PIN o[165]
    DIRECTION OUTPUT ;
    USE SIGNAL ;
    PORT
      LAYER M4 ;
        RECT  0 5.904 0.084 5.928 ;
    END
  END o[165]
  PIN o[166]
    DIRECTION OUTPUT ;
    USE SIGNAL ;
    PORT
      LAYER M4 ;
        RECT  0 6 0.084 6.024 ;
    END
  END o[166]
  PIN o[167]
    DIRECTION OUTPUT ;
    USE SIGNAL ;
    PORT
      LAYER M4 ;
        RECT  0 6.096 0.084 6.12 ;
    END
  END o[167]
  PIN o[168]
    DIRECTION OUTPUT ;
    USE SIGNAL ;
    PORT
      LAYER M4 ;
        RECT  0 6.192 0.084 6.216 ;
    END
  END o[168]
  PIN o[169]
    DIRECTION OUTPUT ;
    USE SIGNAL ;
    PORT
      LAYER M4 ;
        RECT  0 6.288 0.084 6.312 ;
    END
  END o[169]
  PIN o[16]
    DIRECTION OUTPUT ;
    USE SIGNAL ;
    PORT
      LAYER M4 ;
        RECT  0 32.304 0.084 32.328 ;
    END
  END o[16]
  PIN o[170]
    DIRECTION OUTPUT ;
    USE SIGNAL ;
    PORT
      LAYER M4 ;
        RECT  0 6.384 0.084 6.408 ;
    END
  END o[170]
  PIN o[171]
    DIRECTION OUTPUT ;
    USE SIGNAL ;
    PORT
      LAYER M4 ;
        RECT  0 6.48 0.084 6.504 ;
    END
  END o[171]
  PIN o[172]
    DIRECTION OUTPUT ;
    USE SIGNAL ;
    PORT
      LAYER M4 ;
        RECT  0 6.576 0.084 6.6 ;
    END
  END o[172]
  PIN o[173]
    DIRECTION OUTPUT ;
    USE SIGNAL ;
    PORT
      LAYER M4 ;
        RECT  0 6.672 0.084 6.696 ;
    END
  END o[173]
  PIN o[174]
    DIRECTION OUTPUT ;
    USE SIGNAL ;
    PORT
      LAYER M4 ;
        RECT  0 6.768 0.084 6.792 ;
    END
  END o[174]
  PIN o[175]
    DIRECTION OUTPUT ;
    USE SIGNAL ;
    PORT
      LAYER M4 ;
        RECT  0 6.864 0.084 6.888 ;
    END
  END o[175]
  PIN o[176]
    DIRECTION OUTPUT ;
    USE SIGNAL ;
    PORT
      LAYER M4 ;
        RECT  0 6.96 0.084 6.984 ;
    END
  END o[176]
  PIN o[177]
    DIRECTION OUTPUT ;
    USE SIGNAL ;
    PORT
      LAYER M4 ;
        RECT  0 7.056 0.084 7.08 ;
    END
  END o[177]
  PIN o[178]
    DIRECTION OUTPUT ;
    USE SIGNAL ;
    PORT
      LAYER M4 ;
        RECT  0 7.152 0.084 7.176 ;
    END
  END o[178]
  PIN o[179]
    DIRECTION OUTPUT ;
    USE SIGNAL ;
    PORT
      LAYER M4 ;
        RECT  0 7.248 0.084 7.272 ;
    END
  END o[179]
  PIN o[17]
    DIRECTION OUTPUT ;
    USE SIGNAL ;
    PORT
      LAYER M4 ;
        RECT  0 32.4 0.084 32.424 ;
    END
  END o[17]
  PIN o[180]
    DIRECTION OUTPUT ;
    USE SIGNAL ;
    PORT
      LAYER M4 ;
        RECT  0 7.344 0.084 7.368 ;
    END
  END o[180]
  PIN o[181]
    DIRECTION OUTPUT ;
    USE SIGNAL ;
    PORT
      LAYER M4 ;
        RECT  0 7.44 0.084 7.464 ;
    END
  END o[181]
  PIN o[182]
    DIRECTION OUTPUT ;
    USE SIGNAL ;
    PORT
      LAYER M4 ;
        RECT  0 7.536 0.084 7.56 ;
    END
  END o[182]
  PIN o[183]
    DIRECTION OUTPUT ;
    USE SIGNAL ;
    PORT
      LAYER M4 ;
        RECT  0 7.632 0.084 7.656 ;
    END
  END o[183]
  PIN o[184]
    DIRECTION OUTPUT ;
    USE SIGNAL ;
    PORT
      LAYER M4 ;
        RECT  0 7.728 0.084 7.752 ;
    END
  END o[184]
  PIN o[185]
    DIRECTION OUTPUT ;
    USE SIGNAL ;
    PORT
      LAYER M4 ;
        RECT  0 7.824 0.084 7.848 ;
    END
  END o[185]
  PIN o[186]
    DIRECTION OUTPUT ;
    USE SIGNAL ;
    PORT
      LAYER M4 ;
        RECT  0 7.92 0.084 7.944 ;
    END
  END o[186]
  PIN o[187]
    DIRECTION OUTPUT ;
    USE SIGNAL ;
    PORT
      LAYER M4 ;
        RECT  0 8.016 0.084 8.04 ;
    END
  END o[187]
  PIN o[188]
    DIRECTION OUTPUT ;
    USE SIGNAL ;
    PORT
      LAYER M4 ;
        RECT  0 8.112 0.084 8.136 ;
    END
  END o[188]
  PIN o[189]
    DIRECTION OUTPUT ;
    USE SIGNAL ;
    PORT
      LAYER M4 ;
        RECT  0 8.208 0.084 8.232 ;
    END
  END o[189]
  PIN o[18]
    DIRECTION OUTPUT ;
    USE SIGNAL ;
    PORT
      LAYER M4 ;
        RECT  0 32.496 0.084 32.52 ;
    END
  END o[18]
  PIN o[190]
    DIRECTION OUTPUT ;
    USE SIGNAL ;
    PORT
      LAYER M4 ;
        RECT  0 8.304 0.084 8.328 ;
    END
  END o[190]
  PIN o[191]
    DIRECTION OUTPUT ;
    USE SIGNAL ;
    PORT
      LAYER M4 ;
        RECT  0 8.4 0.084 8.424 ;
    END
  END o[191]
  PIN o[192]
    DIRECTION OUTPUT ;
    USE SIGNAL ;
    PORT
      LAYER M4 ;
        RECT  0 2.352 0.084 2.376 ;
    END
  END o[192]
  PIN o[193]
    DIRECTION OUTPUT ;
    USE SIGNAL ;
    PORT
      LAYER M4 ;
        RECT  0 2.448 0.084 2.472 ;
    END
  END o[193]
  PIN o[194]
    DIRECTION OUTPUT ;
    USE SIGNAL ;
    PORT
      LAYER M4 ;
        RECT  0 2.544 0.084 2.568 ;
    END
  END o[194]
  PIN o[195]
    DIRECTION OUTPUT ;
    USE SIGNAL ;
    PORT
      LAYER M4 ;
        RECT  0 2.64 0.084 2.664 ;
    END
  END o[195]
  PIN o[196]
    DIRECTION OUTPUT ;
    USE SIGNAL ;
    PORT
      LAYER M4 ;
        RECT  0 2.736 0.084 2.76 ;
    END
  END o[196]
  PIN o[197]
    DIRECTION OUTPUT ;
    USE SIGNAL ;
    PORT
      LAYER M4 ;
        RECT  0 2.832 0.084 2.856 ;
    END
  END o[197]
  PIN o[198]
    DIRECTION OUTPUT ;
    USE SIGNAL ;
    PORT
      LAYER M4 ;
        RECT  0 2.928 0.084 2.952 ;
    END
  END o[198]
  PIN o[199]
    DIRECTION OUTPUT ;
    USE SIGNAL ;
    PORT
      LAYER M4 ;
        RECT  0 3.024 0.084 3.048 ;
    END
  END o[199]
  PIN o[19]
    DIRECTION OUTPUT ;
    USE SIGNAL ;
    PORT
      LAYER M4 ;
        RECT  0 32.592 0.084 32.616 ;
    END
  END o[19]
  PIN o[1]
    DIRECTION OUTPUT ;
    USE SIGNAL ;
    PORT
      LAYER M4 ;
        RECT  0 30.864 0.084 30.888 ;
    END
  END o[1]
  PIN o[200]
    DIRECTION OUTPUT ;
    USE SIGNAL ;
    PORT
      LAYER M4 ;
        RECT  0 3.12 0.084 3.144 ;
    END
  END o[200]
  PIN o[201]
    DIRECTION OUTPUT ;
    USE SIGNAL ;
    PORT
      LAYER M4 ;
        RECT  0 3.216 0.084 3.24 ;
    END
  END o[201]
  PIN o[202]
    DIRECTION OUTPUT ;
    USE SIGNAL ;
    PORT
      LAYER M4 ;
        RECT  0 3.312 0.084 3.336 ;
    END
  END o[202]
  PIN o[203]
    DIRECTION OUTPUT ;
    USE SIGNAL ;
    PORT
      LAYER M4 ;
        RECT  0 3.408 0.084 3.432 ;
    END
  END o[203]
  PIN o[204]
    DIRECTION OUTPUT ;
    USE SIGNAL ;
    PORT
      LAYER M4 ;
        RECT  0 3.504 0.084 3.528 ;
    END
  END o[204]
  PIN o[205]
    DIRECTION OUTPUT ;
    USE SIGNAL ;
    PORT
      LAYER M4 ;
        RECT  0 3.6 0.084 3.624 ;
    END
  END o[205]
  PIN o[206]
    DIRECTION OUTPUT ;
    USE SIGNAL ;
    PORT
      LAYER M4 ;
        RECT  0 3.696 0.084 3.72 ;
    END
  END o[206]
  PIN o[207]
    DIRECTION OUTPUT ;
    USE SIGNAL ;
    PORT
      LAYER M4 ;
        RECT  0 3.792 0.084 3.816 ;
    END
  END o[207]
  PIN o[208]
    DIRECTION OUTPUT ;
    USE SIGNAL ;
    PORT
      LAYER M4 ;
        RECT  0 3.888 0.084 3.912 ;
    END
  END o[208]
  PIN o[209]
    DIRECTION OUTPUT ;
    USE SIGNAL ;
    PORT
      LAYER M4 ;
        RECT  0 3.984 0.084 4.008 ;
    END
  END o[209]
  PIN o[20]
    DIRECTION OUTPUT ;
    USE SIGNAL ;
    PORT
      LAYER M4 ;
        RECT  0 32.688 0.084 32.712 ;
    END
  END o[20]
  PIN o[210]
    DIRECTION OUTPUT ;
    USE SIGNAL ;
    PORT
      LAYER M4 ;
        RECT  0 4.08 0.084 4.104 ;
    END
  END o[210]
  PIN o[211]
    DIRECTION OUTPUT ;
    USE SIGNAL ;
    PORT
      LAYER M4 ;
        RECT  0 4.176 0.084 4.2 ;
    END
  END o[211]
  PIN o[212]
    DIRECTION OUTPUT ;
    USE SIGNAL ;
    PORT
      LAYER M4 ;
        RECT  0 4.272 0.084 4.296 ;
    END
  END o[212]
  PIN o[213]
    DIRECTION OUTPUT ;
    USE SIGNAL ;
    PORT
      LAYER M4 ;
        RECT  0 4.368 0.084 4.392 ;
    END
  END o[213]
  PIN o[214]
    DIRECTION OUTPUT ;
    USE SIGNAL ;
    PORT
      LAYER M4 ;
        RECT  0 4.464 0.084 4.488 ;
    END
  END o[214]
  PIN o[215]
    DIRECTION OUTPUT ;
    USE SIGNAL ;
    PORT
      LAYER M4 ;
        RECT  0 4.56 0.084 4.584 ;
    END
  END o[215]
  PIN o[216]
    DIRECTION OUTPUT ;
    USE SIGNAL ;
    PORT
      LAYER M4 ;
        RECT  0 4.656 0.084 4.68 ;
    END
  END o[216]
  PIN o[217]
    DIRECTION OUTPUT ;
    USE SIGNAL ;
    PORT
      LAYER M4 ;
        RECT  0 4.752 0.084 4.776 ;
    END
  END o[217]
  PIN o[218]
    DIRECTION OUTPUT ;
    USE SIGNAL ;
    PORT
      LAYER M4 ;
        RECT  0 4.848 0.084 4.872 ;
    END
  END o[218]
  PIN o[219]
    DIRECTION OUTPUT ;
    USE SIGNAL ;
    PORT
      LAYER M4 ;
        RECT  0 4.944 0.084 4.968 ;
    END
  END o[219]
  PIN o[21]
    DIRECTION OUTPUT ;
    USE SIGNAL ;
    PORT
      LAYER M4 ;
        RECT  0 32.784 0.084 32.808 ;
    END
  END o[21]
  PIN o[220]
    DIRECTION OUTPUT ;
    USE SIGNAL ;
    PORT
      LAYER M4 ;
        RECT  0 5.04 0.084 5.064 ;
    END
  END o[220]
  PIN o[221]
    DIRECTION OUTPUT ;
    USE SIGNAL ;
    PORT
      LAYER M4 ;
        RECT  0 5.136 0.084 5.16 ;
    END
  END o[221]
  PIN o[222]
    DIRECTION OUTPUT ;
    USE SIGNAL ;
    PORT
      LAYER M4 ;
        RECT  0 5.232 0.084 5.256 ;
    END
  END o[222]
  PIN o[223]
    DIRECTION OUTPUT ;
    USE SIGNAL ;
    PORT
      LAYER M4 ;
        RECT  0 5.328 0.084 5.352 ;
    END
  END o[223]
  PIN o[224]
    DIRECTION OUTPUT ;
    USE SIGNAL ;
    PORT
      LAYER M4 ;
        RECT  0 27.696 0.084 27.72 ;
    END
  END o[224]
  PIN o[225]
    DIRECTION OUTPUT ;
    USE SIGNAL ;
    PORT
      LAYER M4 ;
        RECT  0 27.792 0.084 27.816 ;
    END
  END o[225]
  PIN o[226]
    DIRECTION OUTPUT ;
    USE SIGNAL ;
    PORT
      LAYER M4 ;
        RECT  0 27.888 0.084 27.912 ;
    END
  END o[226]
  PIN o[227]
    DIRECTION OUTPUT ;
    USE SIGNAL ;
    PORT
      LAYER M4 ;
        RECT  0 27.984 0.084 28.008 ;
    END
  END o[227]
  PIN o[228]
    DIRECTION OUTPUT ;
    USE SIGNAL ;
    PORT
      LAYER M4 ;
        RECT  0 28.08 0.084 28.104 ;
    END
  END o[228]
  PIN o[229]
    DIRECTION OUTPUT ;
    USE SIGNAL ;
    PORT
      LAYER M4 ;
        RECT  0 28.176 0.084 28.2 ;
    END
  END o[229]
  PIN o[22]
    DIRECTION OUTPUT ;
    USE SIGNAL ;
    PORT
      LAYER M4 ;
        RECT  0 32.88 0.084 32.904 ;
    END
  END o[22]
  PIN o[230]
    DIRECTION OUTPUT ;
    USE SIGNAL ;
    PORT
      LAYER M4 ;
        RECT  0 28.272 0.084 28.296 ;
    END
  END o[230]
  PIN o[231]
    DIRECTION OUTPUT ;
    USE SIGNAL ;
    PORT
      LAYER M4 ;
        RECT  0 28.368 0.084 28.392 ;
    END
  END o[231]
  PIN o[232]
    DIRECTION OUTPUT ;
    USE SIGNAL ;
    PORT
      LAYER M4 ;
        RECT  0 28.464 0.084 28.488 ;
    END
  END o[232]
  PIN o[233]
    DIRECTION OUTPUT ;
    USE SIGNAL ;
    PORT
      LAYER M4 ;
        RECT  0 28.56 0.084 28.584 ;
    END
  END o[233]
  PIN o[234]
    DIRECTION OUTPUT ;
    USE SIGNAL ;
    PORT
      LAYER M4 ;
        RECT  0 28.656 0.084 28.68 ;
    END
  END o[234]
  PIN o[235]
    DIRECTION OUTPUT ;
    USE SIGNAL ;
    PORT
      LAYER M4 ;
        RECT  0 28.752 0.084 28.776 ;
    END
  END o[235]
  PIN o[236]
    DIRECTION OUTPUT ;
    USE SIGNAL ;
    PORT
      LAYER M4 ;
        RECT  0 28.848 0.084 28.872 ;
    END
  END o[236]
  PIN o[237]
    DIRECTION OUTPUT ;
    USE SIGNAL ;
    PORT
      LAYER M4 ;
        RECT  0 28.944 0.084 28.968 ;
    END
  END o[237]
  PIN o[238]
    DIRECTION OUTPUT ;
    USE SIGNAL ;
    PORT
      LAYER M4 ;
        RECT  0 29.04 0.084 29.064 ;
    END
  END o[238]
  PIN o[239]
    DIRECTION OUTPUT ;
    USE SIGNAL ;
    PORT
      LAYER M4 ;
        RECT  0 29.136 0.084 29.16 ;
    END
  END o[239]
  PIN o[23]
    DIRECTION OUTPUT ;
    USE SIGNAL ;
    PORT
      LAYER M4 ;
        RECT  0 32.976 0.084 33 ;
    END
  END o[23]
  PIN o[240]
    DIRECTION OUTPUT ;
    USE SIGNAL ;
    PORT
      LAYER M4 ;
        RECT  0 29.232 0.084 29.256 ;
    END
  END o[240]
  PIN o[241]
    DIRECTION OUTPUT ;
    USE SIGNAL ;
    PORT
      LAYER M4 ;
        RECT  0 29.328 0.084 29.352 ;
    END
  END o[241]
  PIN o[242]
    DIRECTION OUTPUT ;
    USE SIGNAL ;
    PORT
      LAYER M4 ;
        RECT  0 29.424 0.084 29.448 ;
    END
  END o[242]
  PIN o[243]
    DIRECTION OUTPUT ;
    USE SIGNAL ;
    PORT
      LAYER M4 ;
        RECT  0 29.52 0.084 29.544 ;
    END
  END o[243]
  PIN o[244]
    DIRECTION OUTPUT ;
    USE SIGNAL ;
    PORT
      LAYER M4 ;
        RECT  0 29.616 0.084 29.64 ;
    END
  END o[244]
  PIN o[245]
    DIRECTION OUTPUT ;
    USE SIGNAL ;
    PORT
      LAYER M4 ;
        RECT  0 29.712 0.084 29.736 ;
    END
  END o[245]
  PIN o[246]
    DIRECTION OUTPUT ;
    USE SIGNAL ;
    PORT
      LAYER M4 ;
        RECT  0 29.808 0.084 29.832 ;
    END
  END o[246]
  PIN o[247]
    DIRECTION OUTPUT ;
    USE SIGNAL ;
    PORT
      LAYER M4 ;
        RECT  0 29.904 0.084 29.928 ;
    END
  END o[247]
  PIN o[248]
    DIRECTION OUTPUT ;
    USE SIGNAL ;
    PORT
      LAYER M4 ;
        RECT  0 30 0.084 30.024 ;
    END
  END o[248]
  PIN o[249]
    DIRECTION OUTPUT ;
    USE SIGNAL ;
    PORT
      LAYER M4 ;
        RECT  0 30.096 0.084 30.12 ;
    END
  END o[249]
  PIN o[24]
    DIRECTION OUTPUT ;
    USE SIGNAL ;
    PORT
      LAYER M4 ;
        RECT  0 33.072 0.084 33.096 ;
    END
  END o[24]
  PIN o[250]
    DIRECTION OUTPUT ;
    USE SIGNAL ;
    PORT
      LAYER M4 ;
        RECT  0 30.192 0.084 30.216 ;
    END
  END o[250]
  PIN o[251]
    DIRECTION OUTPUT ;
    USE SIGNAL ;
    PORT
      LAYER M4 ;
        RECT  0 30.288 0.084 30.312 ;
    END
  END o[251]
  PIN o[252]
    DIRECTION OUTPUT ;
    USE SIGNAL ;
    PORT
      LAYER M4 ;
        RECT  0 30.384 0.084 30.408 ;
    END
  END o[252]
  PIN o[253]
    DIRECTION OUTPUT ;
    USE SIGNAL ;
    PORT
      LAYER M4 ;
        RECT  0 30.48 0.084 30.504 ;
    END
  END o[253]
  PIN o[254]
    DIRECTION OUTPUT ;
    USE SIGNAL ;
    PORT
      LAYER M4 ;
        RECT  0 30.576 0.084 30.6 ;
    END
  END o[254]
  PIN o[255]
    DIRECTION OUTPUT ;
    USE SIGNAL ;
    PORT
      LAYER M4 ;
        RECT  0 30.672 0.084 30.696 ;
    END
  END o[255]
  PIN o[256]
    DIRECTION OUTPUT ;
    USE SIGNAL ;
    PORT
      LAYER M4 ;
        RECT  0 11.568 0.084 11.592 ;
    END
  END o[256]
  PIN o[257]
    DIRECTION OUTPUT ;
    USE SIGNAL ;
    PORT
      LAYER M4 ;
        RECT  0 11.664 0.084 11.688 ;
    END
  END o[257]
  PIN o[258]
    DIRECTION OUTPUT ;
    USE SIGNAL ;
    PORT
      LAYER M4 ;
        RECT  0 11.76 0.084 11.784 ;
    END
  END o[258]
  PIN o[259]
    DIRECTION OUTPUT ;
    USE SIGNAL ;
    PORT
      LAYER M4 ;
        RECT  0 11.856 0.084 11.88 ;
    END
  END o[259]
  PIN o[25]
    DIRECTION OUTPUT ;
    USE SIGNAL ;
    PORT
      LAYER M4 ;
        RECT  0 33.168 0.084 33.192 ;
    END
  END o[25]
  PIN o[260]
    DIRECTION OUTPUT ;
    USE SIGNAL ;
    PORT
      LAYER M4 ;
        RECT  0 11.952 0.084 11.976 ;
    END
  END o[260]
  PIN o[261]
    DIRECTION OUTPUT ;
    USE SIGNAL ;
    PORT
      LAYER M4 ;
        RECT  0 12.048 0.084 12.072 ;
    END
  END o[261]
  PIN o[262]
    DIRECTION OUTPUT ;
    USE SIGNAL ;
    PORT
      LAYER M4 ;
        RECT  0 12.144 0.084 12.168 ;
    END
  END o[262]
  PIN o[263]
    DIRECTION OUTPUT ;
    USE SIGNAL ;
    PORT
      LAYER M4 ;
        RECT  0 12.24 0.084 12.264 ;
    END
  END o[263]
  PIN o[264]
    DIRECTION OUTPUT ;
    USE SIGNAL ;
    PORT
      LAYER M4 ;
        RECT  0 12.336 0.084 12.36 ;
    END
  END o[264]
  PIN o[265]
    DIRECTION OUTPUT ;
    USE SIGNAL ;
    PORT
      LAYER M4 ;
        RECT  0 12.432 0.084 12.456 ;
    END
  END o[265]
  PIN o[266]
    DIRECTION OUTPUT ;
    USE SIGNAL ;
    PORT
      LAYER M4 ;
        RECT  0 12.528 0.084 12.552 ;
    END
  END o[266]
  PIN o[267]
    DIRECTION OUTPUT ;
    USE SIGNAL ;
    PORT
      LAYER M4 ;
        RECT  0 12.624 0.084 12.648 ;
    END
  END o[267]
  PIN o[268]
    DIRECTION OUTPUT ;
    USE SIGNAL ;
    PORT
      LAYER M4 ;
        RECT  0 12.72 0.084 12.744 ;
    END
  END o[268]
  PIN o[269]
    DIRECTION OUTPUT ;
    USE SIGNAL ;
    PORT
      LAYER M4 ;
        RECT  0 12.816 0.084 12.84 ;
    END
  END o[269]
  PIN o[26]
    DIRECTION OUTPUT ;
    USE SIGNAL ;
    PORT
      LAYER M4 ;
        RECT  0 33.264 0.084 33.288 ;
    END
  END o[26]
  PIN o[270]
    DIRECTION OUTPUT ;
    USE SIGNAL ;
    PORT
      LAYER M4 ;
        RECT  0 12.912 0.084 12.936 ;
    END
  END o[270]
  PIN o[271]
    DIRECTION OUTPUT ;
    USE SIGNAL ;
    PORT
      LAYER M4 ;
        RECT  0 13.008 0.084 13.032 ;
    END
  END o[271]
  PIN o[272]
    DIRECTION OUTPUT ;
    USE SIGNAL ;
    PORT
      LAYER M4 ;
        RECT  0 13.104 0.084 13.128 ;
    END
  END o[272]
  PIN o[273]
    DIRECTION OUTPUT ;
    USE SIGNAL ;
    PORT
      LAYER M4 ;
        RECT  0 13.2 0.084 13.224 ;
    END
  END o[273]
  PIN o[274]
    DIRECTION OUTPUT ;
    USE SIGNAL ;
    PORT
      LAYER M4 ;
        RECT  0 13.296 0.084 13.32 ;
    END
  END o[274]
  PIN o[275]
    DIRECTION OUTPUT ;
    USE SIGNAL ;
    PORT
      LAYER M4 ;
        RECT  0 13.392 0.084 13.416 ;
    END
  END o[275]
  PIN o[276]
    DIRECTION OUTPUT ;
    USE SIGNAL ;
    PORT
      LAYER M4 ;
        RECT  0 13.488 0.084 13.512 ;
    END
  END o[276]
  PIN o[277]
    DIRECTION OUTPUT ;
    USE SIGNAL ;
    PORT
      LAYER M4 ;
        RECT  0 13.584 0.084 13.608 ;
    END
  END o[277]
  PIN o[278]
    DIRECTION OUTPUT ;
    USE SIGNAL ;
    PORT
      LAYER M4 ;
        RECT  0 13.68 0.084 13.704 ;
    END
  END o[278]
  PIN o[279]
    DIRECTION OUTPUT ;
    USE SIGNAL ;
    PORT
      LAYER M4 ;
        RECT  0 13.776 0.084 13.8 ;
    END
  END o[279]
  PIN o[27]
    DIRECTION OUTPUT ;
    USE SIGNAL ;
    PORT
      LAYER M4 ;
        RECT  0 33.36 0.084 33.384 ;
    END
  END o[27]
  PIN o[280]
    DIRECTION OUTPUT ;
    USE SIGNAL ;
    PORT
      LAYER M4 ;
        RECT  0 13.872 0.084 13.896 ;
    END
  END o[280]
  PIN o[281]
    DIRECTION OUTPUT ;
    USE SIGNAL ;
    PORT
      LAYER M4 ;
        RECT  0 13.968 0.084 13.992 ;
    END
  END o[281]
  PIN o[282]
    DIRECTION OUTPUT ;
    USE SIGNAL ;
    PORT
      LAYER M4 ;
        RECT  0 14.064 0.084 14.088 ;
    END
  END o[282]
  PIN o[283]
    DIRECTION OUTPUT ;
    USE SIGNAL ;
    PORT
      LAYER M4 ;
        RECT  0 14.16 0.084 14.184 ;
    END
  END o[283]
  PIN o[284]
    DIRECTION OUTPUT ;
    USE SIGNAL ;
    PORT
      LAYER M4 ;
        RECT  0 14.256 0.084 14.28 ;
    END
  END o[284]
  PIN o[285]
    DIRECTION OUTPUT ;
    USE SIGNAL ;
    PORT
      LAYER M4 ;
        RECT  0 14.352 0.084 14.376 ;
    END
  END o[285]
  PIN o[286]
    DIRECTION OUTPUT ;
    USE SIGNAL ;
    PORT
      LAYER M4 ;
        RECT  0 14.448 0.084 14.472 ;
    END
  END o[286]
  PIN o[287]
    DIRECTION OUTPUT ;
    USE SIGNAL ;
    PORT
      LAYER M4 ;
        RECT  0 14.544 0.084 14.568 ;
    END
  END o[287]
  PIN o[288]
    DIRECTION OUTPUT ;
    USE SIGNAL ;
    PORT
      LAYER M4 ;
        RECT  0 9.84 0.084 9.864 ;
    END
  END o[288]
  PIN o[289]
    DIRECTION OUTPUT ;
    USE SIGNAL ;
    PORT
      LAYER M4 ;
        RECT  0 9.936 0.084 9.96 ;
    END
  END o[289]
  PIN o[28]
    DIRECTION OUTPUT ;
    USE SIGNAL ;
    PORT
      LAYER M4 ;
        RECT  0 33.456 0.084 33.48 ;
    END
  END o[28]
  PIN o[290]
    DIRECTION OUTPUT ;
    USE SIGNAL ;
    PORT
      LAYER M4 ;
        RECT  0 10.032 0.084 10.056 ;
    END
  END o[290]
  PIN o[291]
    DIRECTION OUTPUT ;
    USE SIGNAL ;
    PORT
      LAYER M4 ;
        RECT  0 10.128 0.084 10.152 ;
    END
  END o[291]
  PIN o[292]
    DIRECTION OUTPUT ;
    USE SIGNAL ;
    PORT
      LAYER M4 ;
        RECT  0 10.224 0.084 10.248 ;
    END
  END o[292]
  PIN o[293]
    DIRECTION OUTPUT ;
    USE SIGNAL ;
    PORT
      LAYER M4 ;
        RECT  0 10.32 0.084 10.344 ;
    END
  END o[293]
  PIN o[294]
    DIRECTION OUTPUT ;
    USE SIGNAL ;
    PORT
      LAYER M4 ;
        RECT  0 10.416 0.084 10.44 ;
    END
  END o[294]
  PIN o[295]
    DIRECTION OUTPUT ;
    USE SIGNAL ;
    PORT
      LAYER M4 ;
        RECT  0 10.512 0.084 10.536 ;
    END
  END o[295]
  PIN o[296]
    DIRECTION OUTPUT ;
    USE SIGNAL ;
    PORT
      LAYER M4 ;
        RECT  0 10.608 0.084 10.632 ;
    END
  END o[296]
  PIN o[297]
    DIRECTION OUTPUT ;
    USE SIGNAL ;
    PORT
      LAYER M4 ;
        RECT  0 10.704 0.084 10.728 ;
    END
  END o[297]
  PIN o[298]
    DIRECTION OUTPUT ;
    USE SIGNAL ;
    PORT
      LAYER M4 ;
        RECT  0 10.8 0.084 10.824 ;
    END
  END o[298]
  PIN o[299]
    DIRECTION OUTPUT ;
    USE SIGNAL ;
    PORT
      LAYER M4 ;
        RECT  0 10.896 0.084 10.92 ;
    END
  END o[299]
  PIN o[29]
    DIRECTION OUTPUT ;
    USE SIGNAL ;
    PORT
      LAYER M4 ;
        RECT  0 33.552 0.084 33.576 ;
    END
  END o[29]
  PIN o[2]
    DIRECTION OUTPUT ;
    USE SIGNAL ;
    PORT
      LAYER M4 ;
        RECT  0 30.96 0.084 30.984 ;
    END
  END o[2]
  PIN o[300]
    DIRECTION OUTPUT ;
    USE SIGNAL ;
    PORT
      LAYER M4 ;
        RECT  0 10.992 0.084 11.016 ;
    END
  END o[300]
  PIN o[301]
    DIRECTION OUTPUT ;
    USE SIGNAL ;
    PORT
      LAYER M4 ;
        RECT  0 11.088 0.084 11.112 ;
    END
  END o[301]
  PIN o[302]
    DIRECTION OUTPUT ;
    USE SIGNAL ;
    PORT
      LAYER M4 ;
        RECT  0 11.184 0.084 11.208 ;
    END
  END o[302]
  PIN o[303]
    DIRECTION OUTPUT ;
    USE SIGNAL ;
    PORT
      LAYER M4 ;
        RECT  0 11.28 0.084 11.304 ;
    END
  END o[303]
  PIN o[30]
    DIRECTION OUTPUT ;
    USE SIGNAL ;
    PORT
      LAYER M4 ;
        RECT  0 33.648 0.084 33.672 ;
    END
  END o[30]
  PIN o[31]
    DIRECTION OUTPUT ;
    USE SIGNAL ;
    PORT
      LAYER M4 ;
        RECT  0 33.744 0.084 33.768 ;
    END
  END o[31]
  PIN o[32]
    DIRECTION OUTPUT ;
    USE SIGNAL ;
    PORT
      LAYER M4 ;
        RECT  0 24.624 0.084 24.648 ;
    END
  END o[32]
  PIN o[33]
    DIRECTION OUTPUT ;
    USE SIGNAL ;
    PORT
      LAYER M4 ;
        RECT  0 24.72 0.084 24.744 ;
    END
  END o[33]
  PIN o[34]
    DIRECTION OUTPUT ;
    USE SIGNAL ;
    PORT
      LAYER M4 ;
        RECT  0 24.816 0.084 24.84 ;
    END
  END o[34]
  PIN o[35]
    DIRECTION OUTPUT ;
    USE SIGNAL ;
    PORT
      LAYER M4 ;
        RECT  0 24.912 0.084 24.936 ;
    END
  END o[35]
  PIN o[36]
    DIRECTION OUTPUT ;
    USE SIGNAL ;
    PORT
      LAYER M4 ;
        RECT  0 25.008 0.084 25.032 ;
    END
  END o[36]
  PIN o[37]
    DIRECTION OUTPUT ;
    USE SIGNAL ;
    PORT
      LAYER M4 ;
        RECT  0 25.104 0.084 25.128 ;
    END
  END o[37]
  PIN o[38]
    DIRECTION OUTPUT ;
    USE SIGNAL ;
    PORT
      LAYER M4 ;
        RECT  0 25.2 0.084 25.224 ;
    END
  END o[38]
  PIN o[39]
    DIRECTION OUTPUT ;
    USE SIGNAL ;
    PORT
      LAYER M4 ;
        RECT  0 25.296 0.084 25.32 ;
    END
  END o[39]
  PIN o[3]
    DIRECTION OUTPUT ;
    USE SIGNAL ;
    PORT
      LAYER M4 ;
        RECT  0 31.056 0.084 31.08 ;
    END
  END o[3]
  PIN o[40]
    DIRECTION OUTPUT ;
    USE SIGNAL ;
    PORT
      LAYER M4 ;
        RECT  0 25.392 0.084 25.416 ;
    END
  END o[40]
  PIN o[41]
    DIRECTION OUTPUT ;
    USE SIGNAL ;
    PORT
      LAYER M4 ;
        RECT  0 25.488 0.084 25.512 ;
    END
  END o[41]
  PIN o[42]
    DIRECTION OUTPUT ;
    USE SIGNAL ;
    PORT
      LAYER M4 ;
        RECT  0 25.584 0.084 25.608 ;
    END
  END o[42]
  PIN o[43]
    DIRECTION OUTPUT ;
    USE SIGNAL ;
    PORT
      LAYER M4 ;
        RECT  0 25.68 0.084 25.704 ;
    END
  END o[43]
  PIN o[44]
    DIRECTION OUTPUT ;
    USE SIGNAL ;
    PORT
      LAYER M4 ;
        RECT  0 25.776 0.084 25.8 ;
    END
  END o[44]
  PIN o[45]
    DIRECTION OUTPUT ;
    USE SIGNAL ;
    PORT
      LAYER M4 ;
        RECT  0 25.872 0.084 25.896 ;
    END
  END o[45]
  PIN o[46]
    DIRECTION OUTPUT ;
    USE SIGNAL ;
    PORT
      LAYER M4 ;
        RECT  0 25.968 0.084 25.992 ;
    END
  END o[46]
  PIN o[47]
    DIRECTION OUTPUT ;
    USE SIGNAL ;
    PORT
      LAYER M4 ;
        RECT  0 26.064 0.084 26.088 ;
    END
  END o[47]
  PIN o[48]
    DIRECTION OUTPUT ;
    USE SIGNAL ;
    PORT
      LAYER M4 ;
        RECT  0 26.16 0.084 26.184 ;
    END
  END o[48]
  PIN o[49]
    DIRECTION OUTPUT ;
    USE SIGNAL ;
    PORT
      LAYER M4 ;
        RECT  0 26.256 0.084 26.28 ;
    END
  END o[49]
  PIN o[4]
    DIRECTION OUTPUT ;
    USE SIGNAL ;
    PORT
      LAYER M4 ;
        RECT  0 31.152 0.084 31.176 ;
    END
  END o[4]
  PIN o[50]
    DIRECTION OUTPUT ;
    USE SIGNAL ;
    PORT
      LAYER M4 ;
        RECT  0 26.352 0.084 26.376 ;
    END
  END o[50]
  PIN o[51]
    DIRECTION OUTPUT ;
    USE SIGNAL ;
    PORT
      LAYER M4 ;
        RECT  0 26.448 0.084 26.472 ;
    END
  END o[51]
  PIN o[52]
    DIRECTION OUTPUT ;
    USE SIGNAL ;
    PORT
      LAYER M4 ;
        RECT  0 26.544 0.084 26.568 ;
    END
  END o[52]
  PIN o[53]
    DIRECTION OUTPUT ;
    USE SIGNAL ;
    PORT
      LAYER M4 ;
        RECT  0 26.64 0.084 26.664 ;
    END
  END o[53]
  PIN o[54]
    DIRECTION OUTPUT ;
    USE SIGNAL ;
    PORT
      LAYER M4 ;
        RECT  0 26.736 0.084 26.76 ;
    END
  END o[54]
  PIN o[55]
    DIRECTION OUTPUT ;
    USE SIGNAL ;
    PORT
      LAYER M4 ;
        RECT  0 26.832 0.084 26.856 ;
    END
  END o[55]
  PIN o[56]
    DIRECTION OUTPUT ;
    USE SIGNAL ;
    PORT
      LAYER M4 ;
        RECT  0 26.928 0.084 26.952 ;
    END
  END o[56]
  PIN o[57]
    DIRECTION OUTPUT ;
    USE SIGNAL ;
    PORT
      LAYER M4 ;
        RECT  0 27.024 0.084 27.048 ;
    END
  END o[57]
  PIN o[58]
    DIRECTION OUTPUT ;
    USE SIGNAL ;
    PORT
      LAYER M4 ;
        RECT  0 27.12 0.084 27.144 ;
    END
  END o[58]
  PIN o[59]
    DIRECTION OUTPUT ;
    USE SIGNAL ;
    PORT
      LAYER M4 ;
        RECT  0 27.216 0.084 27.24 ;
    END
  END o[59]
  PIN o[5]
    DIRECTION OUTPUT ;
    USE SIGNAL ;
    PORT
      LAYER M4 ;
        RECT  0 31.248 0.084 31.272 ;
    END
  END o[5]
  PIN o[60]
    DIRECTION OUTPUT ;
    USE SIGNAL ;
    PORT
      LAYER M4 ;
        RECT  0 27.312 0.084 27.336 ;
    END
  END o[60]
  PIN o[61]
    DIRECTION OUTPUT ;
    USE SIGNAL ;
    PORT
      LAYER M4 ;
        RECT  0 27.408 0.084 27.432 ;
    END
  END o[61]
  PIN o[62]
    DIRECTION OUTPUT ;
    USE SIGNAL ;
    PORT
      LAYER M4 ;
        RECT  0 27.504 0.084 27.528 ;
    END
  END o[62]
  PIN o[63]
    DIRECTION OUTPUT ;
    USE SIGNAL ;
    PORT
      LAYER M4 ;
        RECT  0 27.6 0.084 27.624 ;
    END
  END o[63]
  PIN o[64]
    DIRECTION OUTPUT ;
    USE SIGNAL ;
    PORT
      LAYER M4 ;
        RECT  0 21.552 0.084 21.576 ;
    END
  END o[64]
  PIN o[65]
    DIRECTION OUTPUT ;
    USE SIGNAL ;
    PORT
      LAYER M4 ;
        RECT  0 21.648 0.084 21.672 ;
    END
  END o[65]
  PIN o[66]
    DIRECTION OUTPUT ;
    USE SIGNAL ;
    PORT
      LAYER M4 ;
        RECT  0 21.744 0.084 21.768 ;
    END
  END o[66]
  PIN o[67]
    DIRECTION OUTPUT ;
    USE SIGNAL ;
    PORT
      LAYER M4 ;
        RECT  0 21.84 0.084 21.864 ;
    END
  END o[67]
  PIN o[68]
    DIRECTION OUTPUT ;
    USE SIGNAL ;
    PORT
      LAYER M4 ;
        RECT  0 21.936 0.084 21.96 ;
    END
  END o[68]
  PIN o[69]
    DIRECTION OUTPUT ;
    USE SIGNAL ;
    PORT
      LAYER M4 ;
        RECT  0 22.032 0.084 22.056 ;
    END
  END o[69]
  PIN o[6]
    DIRECTION OUTPUT ;
    USE SIGNAL ;
    PORT
      LAYER M4 ;
        RECT  0 31.344 0.084 31.368 ;
    END
  END o[6]
  PIN o[70]
    DIRECTION OUTPUT ;
    USE SIGNAL ;
    PORT
      LAYER M4 ;
        RECT  0 22.128 0.084 22.152 ;
    END
  END o[70]
  PIN o[71]
    DIRECTION OUTPUT ;
    USE SIGNAL ;
    PORT
      LAYER M4 ;
        RECT  0 22.224 0.084 22.248 ;
    END
  END o[71]
  PIN o[72]
    DIRECTION OUTPUT ;
    USE SIGNAL ;
    PORT
      LAYER M4 ;
        RECT  0 22.32 0.084 22.344 ;
    END
  END o[72]
  PIN o[73]
    DIRECTION OUTPUT ;
    USE SIGNAL ;
    PORT
      LAYER M4 ;
        RECT  0 22.416 0.084 22.44 ;
    END
  END o[73]
  PIN o[74]
    DIRECTION OUTPUT ;
    USE SIGNAL ;
    PORT
      LAYER M4 ;
        RECT  0 22.512 0.084 22.536 ;
    END
  END o[74]
  PIN o[75]
    DIRECTION OUTPUT ;
    USE SIGNAL ;
    PORT
      LAYER M4 ;
        RECT  0 22.608 0.084 22.632 ;
    END
  END o[75]
  PIN o[76]
    DIRECTION OUTPUT ;
    USE SIGNAL ;
    PORT
      LAYER M4 ;
        RECT  0 22.704 0.084 22.728 ;
    END
  END o[76]
  PIN o[77]
    DIRECTION OUTPUT ;
    USE SIGNAL ;
    PORT
      LAYER M4 ;
        RECT  0 22.8 0.084 22.824 ;
    END
  END o[77]
  PIN o[78]
    DIRECTION OUTPUT ;
    USE SIGNAL ;
    PORT
      LAYER M4 ;
        RECT  0 22.896 0.084 22.92 ;
    END
  END o[78]
  PIN o[79]
    DIRECTION OUTPUT ;
    USE SIGNAL ;
    PORT
      LAYER M4 ;
        RECT  0 22.992 0.084 23.016 ;
    END
  END o[79]
  PIN o[7]
    DIRECTION OUTPUT ;
    USE SIGNAL ;
    PORT
      LAYER M4 ;
        RECT  0 31.44 0.084 31.464 ;
    END
  END o[7]
  PIN o[80]
    DIRECTION OUTPUT ;
    USE SIGNAL ;
    PORT
      LAYER M4 ;
        RECT  0 23.088 0.084 23.112 ;
    END
  END o[80]
  PIN o[81]
    DIRECTION OUTPUT ;
    USE SIGNAL ;
    PORT
      LAYER M4 ;
        RECT  0 23.184 0.084 23.208 ;
    END
  END o[81]
  PIN o[82]
    DIRECTION OUTPUT ;
    USE SIGNAL ;
    PORT
      LAYER M4 ;
        RECT  0 23.28 0.084 23.304 ;
    END
  END o[82]
  PIN o[83]
    DIRECTION OUTPUT ;
    USE SIGNAL ;
    PORT
      LAYER M4 ;
        RECT  0 23.376 0.084 23.4 ;
    END
  END o[83]
  PIN o[84]
    DIRECTION OUTPUT ;
    USE SIGNAL ;
    PORT
      LAYER M4 ;
        RECT  0 23.472 0.084 23.496 ;
    END
  END o[84]
  PIN o[85]
    DIRECTION OUTPUT ;
    USE SIGNAL ;
    PORT
      LAYER M4 ;
        RECT  0 23.568 0.084 23.592 ;
    END
  END o[85]
  PIN o[86]
    DIRECTION OUTPUT ;
    USE SIGNAL ;
    PORT
      LAYER M4 ;
        RECT  0 23.664 0.084 23.688 ;
    END
  END o[86]
  PIN o[87]
    DIRECTION OUTPUT ;
    USE SIGNAL ;
    PORT
      LAYER M4 ;
        RECT  0 23.76 0.084 23.784 ;
    END
  END o[87]
  PIN o[88]
    DIRECTION OUTPUT ;
    USE SIGNAL ;
    PORT
      LAYER M4 ;
        RECT  0 23.856 0.084 23.88 ;
    END
  END o[88]
  PIN o[89]
    DIRECTION OUTPUT ;
    USE SIGNAL ;
    PORT
      LAYER M4 ;
        RECT  0 23.952 0.084 23.976 ;
    END
  END o[89]
  PIN o[8]
    DIRECTION OUTPUT ;
    USE SIGNAL ;
    PORT
      LAYER M4 ;
        RECT  0 31.536 0.084 31.56 ;
    END
  END o[8]
  PIN o[90]
    DIRECTION OUTPUT ;
    USE SIGNAL ;
    PORT
      LAYER M4 ;
        RECT  0 24.048 0.084 24.072 ;
    END
  END o[90]
  PIN o[91]
    DIRECTION OUTPUT ;
    USE SIGNAL ;
    PORT
      LAYER M4 ;
        RECT  0 24.144 0.084 24.168 ;
    END
  END o[91]
  PIN o[92]
    DIRECTION OUTPUT ;
    USE SIGNAL ;
    PORT
      LAYER M4 ;
        RECT  0 24.24 0.084 24.264 ;
    END
  END o[92]
  PIN o[93]
    DIRECTION OUTPUT ;
    USE SIGNAL ;
    PORT
      LAYER M4 ;
        RECT  0 24.336 0.084 24.36 ;
    END
  END o[93]
  PIN o[94]
    DIRECTION OUTPUT ;
    USE SIGNAL ;
    PORT
      LAYER M4 ;
        RECT  0 24.432 0.084 24.456 ;
    END
  END o[94]
  PIN o[95]
    DIRECTION OUTPUT ;
    USE SIGNAL ;
    PORT
      LAYER M4 ;
        RECT  0 24.528 0.084 24.552 ;
    END
  END o[95]
  PIN o[96]
    DIRECTION OUTPUT ;
    USE SIGNAL ;
    PORT
      LAYER M4 ;
        RECT  0 18.48 0.084 18.504 ;
    END
  END o[96]
  PIN o[97]
    DIRECTION OUTPUT ;
    USE SIGNAL ;
    PORT
      LAYER M4 ;
        RECT  0 18.576 0.084 18.6 ;
    END
  END o[97]
  PIN o[98]
    DIRECTION OUTPUT ;
    USE SIGNAL ;
    PORT
      LAYER M4 ;
        RECT  0 18.672 0.084 18.696 ;
    END
  END o[98]
  PIN o[99]
    DIRECTION OUTPUT ;
    USE SIGNAL ;
    PORT
      LAYER M4 ;
        RECT  0 18.768 0.084 18.792 ;
    END
  END o[99]
  PIN o[9]
    DIRECTION OUTPUT ;
    USE SIGNAL ;
    PORT
      LAYER M4 ;
        RECT  0 31.632 0.084 31.656 ;
    END
  END o[9]
  PIN rfi
    DIRECTION INPUT ;
    USE SIGNAL ;
    PORT
      LAYER M4 ;
        RECT  21.516 24.528 21.6 24.552 ;
    END
  END rfi
  PIN rfo
    DIRECTION OUTPUT ;
    USE SIGNAL ;
    PORT
      LAYER M4 ;
        RECT  0 11.376 0.084 11.4 ;
    END
  END rfo
  PIN rs
    DIRECTION INPUT ;
    USE SIGNAL ;
    PORT
      LAYER M5 ;
        RECT  13.104 0 13.128 0.084 ;
    END
  END rs
  PIN rso
    DIRECTION OUTPUT ;
    USE SIGNAL ;
    PORT
      LAYER M4 ;
        RECT  0 11.472 0.084 11.496 ;
    END
  END rso
  PIN VDD
    DIRECTION INOUT ;
    USE POWER ;
    PORT
      LAYER M5 ;
        RECT  18.792 2.151 18.912 32.409 ;
        RECT  16.092 2.151 16.212 32.409 ;
        RECT  13.392 2.151 13.512 32.409 ;
        RECT  10.692 2.151 10.812 32.409 ;
        RECT  7.992 2.151 8.112 32.409 ;
        RECT  5.292 2.151 5.412 32.409 ;
        RECT  2.592 2.151 2.712 32.409 ;
    END
  END VDD
  PIN VSS
    DIRECTION INOUT ;
    USE GROUND ;
    PORT
      LAYER M5 ;
        RECT  18.6 2.137 18.72 32.423 ;
        RECT  15.9 2.137 16.02 32.423 ;
        RECT  13.2 2.137 13.32 32.423 ;
        RECT  10.5 2.137 10.62 32.423 ;
        RECT  7.8 2.137 7.92 32.423 ;
        RECT  5.1 2.137 5.22 32.423 ;
        RECT  2.4 2.137 2.52 32.423 ;
    END
  END VSS
  # OT_OBS_CLOSED layer=M5 d_um=1.536 added=81
  OBS
    LAYER RVTN ;
     RECT  2.16 2.16 19.44 2.295 ;
     RECT  2.16 2.565 19.44 2.835 ;
     RECT  2.16 3.105 19.44 3.375 ;
     RECT  2.16 3.645 19.44 3.915 ;
     RECT  2.16 4.185 19.44 4.455 ;
     RECT  2.16 4.725 19.44 4.995 ;
     RECT  2.16 5.265 19.44 5.535 ;
     RECT  2.16 5.805 19.44 6.075 ;
     RECT  2.16 6.345 19.44 6.615 ;
     RECT  2.16 6.885 19.44 7.155 ;
     RECT  2.16 7.425 19.44 7.695 ;
     RECT  2.16 7.965 19.44 8.235 ;
     RECT  2.16 8.505 19.44 8.775 ;
     RECT  2.16 9.045 19.44 9.315 ;
     RECT  2.16 9.585 19.44 9.855 ;
     RECT  2.16 10.125 19.44 10.395 ;
     RECT  2.16 10.665 19.44 10.935 ;
     RECT  2.16 11.205 19.44 11.475 ;
     RECT  2.16 11.745 19.44 12.015 ;
     RECT  2.16 12.285 19.44 12.555 ;
     RECT  2.16 12.825 19.44 13.095 ;
     RECT  2.16 13.365 19.44 13.635 ;
     RECT  2.16 13.905 19.44 14.175 ;
     RECT  2.16 14.445 19.44 14.715 ;
     RECT  2.16 14.985 19.44 15.255 ;
     RECT  2.16 15.525 19.44 15.795 ;
     RECT  2.16 16.065 19.44 16.335 ;
     RECT  2.16 16.605 19.44 16.875 ;
     RECT  2.16 17.145 19.44 17.415 ;
     RECT  2.16 17.685 19.44 17.955 ;
     RECT  2.16 18.225 19.44 18.495 ;
     RECT  2.16 18.765 19.44 19.035 ;
     RECT  2.16 19.305 19.44 19.575 ;
     RECT  2.16 19.845 19.44 20.115 ;
     RECT  2.16 20.385 19.44 20.655 ;
     RECT  2.16 20.925 19.44 21.195 ;
     RECT  2.16 21.465 19.44 21.735 ;
     RECT  2.16 22.005 19.44 22.275 ;
     RECT  2.16 22.545 19.44 22.815 ;
     RECT  2.16 23.085 19.44 23.355 ;
     RECT  2.16 23.625 19.44 23.895 ;
     RECT  2.16 24.165 19.44 24.435 ;
     RECT  2.16 24.705 19.44 24.975 ;
     RECT  2.16 25.245 19.44 25.515 ;
     RECT  2.16 25.785 19.44 26.055 ;
     RECT  2.16 26.325 19.44 26.595 ;
     RECT  2.16 26.865 19.44 27.135 ;
     RECT  2.16 27.405 19.44 27.675 ;
     RECT  2.16 27.945 19.44 28.215 ;
     RECT  2.16 28.485 19.44 28.755 ;
     RECT  2.16 29.025 19.44 29.295 ;
     RECT  2.16 29.565 19.44 29.835 ;
     RECT  2.16 30.105 19.44 30.375 ;
     RECT  2.16 30.645 19.44 30.915 ;
     RECT  2.16 31.185 19.44 31.455 ;
     RECT  2.16 31.725 19.44 31.995 ;
     RECT  2.16 32.265 19.44 32.4 ;
    LAYER RVTP ;
     RECT  2.16 2.295 19.44 2.565 ;
     RECT  2.16 2.835 19.44 3.105 ;
     RECT  2.16 3.375 19.44 3.645 ;
     RECT  2.16 3.915 19.44 4.185 ;
     RECT  2.16 4.455 19.44 4.725 ;
     RECT  2.16 4.995 19.44 5.265 ;
     RECT  2.16 5.535 19.44 5.805 ;
     RECT  2.16 6.075 19.44 6.345 ;
     RECT  2.16 6.615 19.44 6.885 ;
     RECT  2.16 7.155 19.44 7.425 ;
     RECT  2.16 7.695 19.44 7.965 ;
     RECT  2.16 8.235 19.44 8.505 ;
     RECT  2.16 8.775 19.44 9.045 ;
     RECT  2.16 9.315 19.44 9.585 ;
     RECT  2.16 9.855 19.44 10.125 ;
     RECT  2.16 10.395 19.44 10.665 ;
     RECT  2.16 10.935 19.44 11.205 ;
     RECT  2.16 11.475 19.44 11.745 ;
     RECT  2.16 12.015 19.44 12.285 ;
     RECT  2.16 12.555 19.44 12.825 ;
     RECT  2.16 13.095 19.44 13.365 ;
     RECT  2.16 13.635 19.44 13.905 ;
     RECT  2.16 14.175 19.44 14.445 ;
     RECT  2.16 14.715 19.44 14.985 ;
     RECT  2.16 15.255 19.44 15.525 ;
     RECT  2.16 15.795 19.44 16.065 ;
     RECT  2.16 16.335 19.44 16.605 ;
     RECT  2.16 16.875 19.44 17.145 ;
     RECT  2.16 17.415 19.44 17.685 ;
     RECT  2.16 17.955 19.44 18.225 ;
     RECT  2.16 18.495 19.44 18.765 ;
     RECT  2.16 19.035 19.44 19.305 ;
     RECT  2.16 19.575 19.44 19.845 ;
     RECT  2.16 20.115 19.44 20.385 ;
     RECT  2.16 20.655 19.44 20.925 ;
     RECT  2.16 21.195 19.44 21.465 ;
     RECT  2.16 21.735 19.44 22.005 ;
     RECT  2.16 22.275 19.44 22.545 ;
     RECT  2.16 22.815 19.44 23.085 ;
     RECT  2.16 23.355 19.44 23.625 ;
     RECT  2.16 23.895 19.44 24.165 ;
     RECT  2.16 24.435 19.44 24.705 ;
     RECT  2.16 24.975 19.44 25.245 ;
     RECT  2.16 25.515 19.44 25.785 ;
     RECT  2.16 26.055 19.44 26.325 ;
     RECT  2.16 26.595 19.44 26.865 ;
     RECT  2.16 27.135 19.44 27.405 ;
     RECT  2.16 27.675 19.44 27.945 ;
     RECT  2.16 28.215 19.44 28.485 ;
     RECT  2.16 28.755 19.44 29.025 ;
     RECT  2.16 29.295 19.44 29.565 ;
     RECT  2.16 29.835 19.44 30.105 ;
     RECT  2.16 30.375 19.44 30.645 ;
     RECT  2.16 30.915 19.44 31.185 ;
     RECT  2.16 31.455 19.44 31.725 ;
     RECT  2.16 31.995 19.44 32.265 ;
    LAYER M1 ;
     RECT  2.16 2.151 19.44 32.409 ;
    LAYER M2 ;
     RECT  0.103 7.74 0.139 7.758 ;
     RECT  0.103 23.751 0.139 23.769 ;
     RECT  0.103 18.666 0.175 18.684 ;
     RECT  0.103 2.538 0.203 2.556 ;
     RECT  0.103 3.996 0.203 4.014 ;
     RECT  0.103 5.31 0.203 5.526 ;
     RECT  0.103 6.66 0.203 6.678 ;
     RECT  0.103 11.412 0.203 11.43 ;
     RECT  0.103 14.256 0.203 14.274 ;
     RECT  0.103 17.316 0.203 17.442 ;
     RECT  0.103 19.62 0.203 19.638 ;
     RECT  0.103 31.806 0.203 31.824 ;
     RECT  0.175 18.621 0.211 18.684 ;
     RECT  0.203 5.31 0.239 5.328 ;
     RECT  0.139 21.816 0.239 21.834 ;
     RECT  0.103 29.376 0.239 30.744 ;
     RECT  0.139 7.668 0.347 7.758 ;
     RECT  0.211 18.621 0.347 19.602 ;
     RECT  0.103 20.97 0.347 20.988 ;
     RECT  0.139 23.634 0.347 23.769 ;
     RECT  0.103 24.984 0.347 25.002 ;
     RECT  0.347 7.668 0.383 7.686 ;
     RECT  0.499 10.404 0.535 10.422 ;
     RECT  0.347 18.621 0.823 18.684 ;
     RECT  0.535 15.066 1.111 15.084 ;
     RECT  0.535 10.404 1.147 10.494 ;
     RECT  0.203 17.316 1.147 17.334 ;
     RECT  0.347 19.584 1.147 19.602 ;
     RECT  1.111 27.954 1.147 27.972 ;
     RECT  0.823 18.198 1.175 18.684 ;
     RECT  1.147 19.584 1.175 19.674 ;
     RECT  1.147 27.954 1.175 28.044 ;
     RECT  1.175 19.656 1.219 19.674 ;
     RECT  1.147 20.664 1.219 20.682 ;
     RECT  1.147 17.082 1.319 17.334 ;
     RECT  1.219 19.656 1.355 20.682 ;
     RECT  1.291 7.668 1.391 7.686 ;
     RECT  1.355 20.664 1.391 20.682 ;
     RECT  1.687 3.348 2.16 3.366 ;
     RECT  1.147 10.296 2.16 10.494 ;
     RECT  1.111 15.066 2.16 15.282 ;
     RECT  1.319 17.316 2.16 17.334 ;
     RECT  1.175 18.198 2.16 18.594 ;
     RECT  1.355 19.656 2.16 19.674 ;
     RECT  0.347 23.706 2.16 23.724 ;
     RECT  1.723 24.786 2.16 24.804 ;
     RECT  0.535 26.136 2.16 26.154 ;
     RECT  1.175 28.026 2.16 28.044 ;
     RECT  0.239 29.376 2.16 30.402 ;
     RECT  1.723 32.58 2.16 32.598 ;
     RECT  2.16 2.151 2.335 32.598 ;
     RECT  2.335 2.151 2.551 33.066 ;
     RECT  2.551 2.151 3.019 33.102 ;
     RECT  3.019 2.034 5.251 33.138 ;
     RECT  5.251 1.998 5.675 33.138 ;
     RECT  5.675 2.07 6.907 33.138 ;
     RECT  6.907 1.998 10.831 33.138 ;
     RECT  10.831 1.998 11.219 33.606 ;
     RECT  11.219 33.588 12.731 33.606 ;
     RECT  11.219 1.998 13.171 32.76 ;
     RECT  13.171 1.962 13.703 32.76 ;
     RECT  13.703 1.962 17.519 32.724 ;
     RECT  17.519 2.106 18.059 32.724 ;
     RECT  18.059 2.106 18.275 32.49 ;
     RECT  18.275 2.106 18.959 32.454 ;
     RECT  18.959 2.151 19.067 32.454 ;
     RECT  19.067 2.151 19.44 32.409 ;
     RECT  19.44 15.84 19.967 24.228 ;
     RECT  19.44 26.37 19.967 30.6 ;
     RECT  19.44 2.538 20.219 5.76 ;
     RECT  19.967 15.84 20.219 23.922 ;
     RECT  19.44 31.77 20.219 32.058 ;
     RECT  20.219 2.538 20.435 4.986 ;
     RECT  19.44 6.66 20.435 8.766 ;
     RECT  20.435 2.538 20.507 4.518 ;
     RECT  20.219 17.118 20.507 23.922 ;
     RECT  20.507 4.158 20.543 4.518 ;
     RECT  20.435 6.66 20.543 8.226 ;
     RECT  19.44 11.718 20.543 13.086 ;
     RECT  20.507 20.358 20.543 23.922 ;
     RECT  19.44 25.29 20.543 25.578 ;
     RECT  19.967 26.568 20.543 27.972 ;
     RECT  19.967 28.8 20.543 30.6 ;
     RECT  20.219 31.77 20.543 31.986 ;
     RECT  20.543 20.358 20.579 23.688 ;
     RECT  20.543 25.488 20.579 25.578 ;
     RECT  20.543 29.538 20.579 30.6 ;
     RECT  20.543 26.568 20.615 27.738 ;
     RECT  20.579 25.488 20.651 25.506 ;
     RECT  20.615 27.72 20.651 27.738 ;
     RECT  20.219 5.742 21.271 5.76 ;
     RECT  20.543 12.834 21.271 13.086 ;
     RECT  20.543 4.158 21.299 4.446 ;
     RECT  19.44 10.098 21.307 10.116 ;
     RECT  21.307 10.098 21.343 10.728 ;
     RECT  20.579 21.474 21.371 23.346 ;
     RECT  21.343 10.098 21.407 10.854 ;
     RECT  20.507 17.118 21.407 19.566 ;
     RECT  20.507 2.538 21.415 3.366 ;
     RECT  21.299 4.158 21.415 4.176 ;
     RECT  21.271 5.742 21.415 6.174 ;
     RECT  21.271 12.636 21.415 13.086 ;
     RECT  19.44 13.95 21.415 15.084 ;
     RECT  20.219 15.84 21.415 16.362 ;
     RECT  21.407 17.388 21.415 19.566 ;
     RECT  20.579 20.358 21.415 20.376 ;
     RECT  20.579 29.538 21.415 29.826 ;
     RECT  21.415 2.538 21.443 4.176 ;
     RECT  20.543 11.718 21.443 11.736 ;
     RECT  21.415 17.388 21.443 20.376 ;
     RECT  21.371 21.474 21.443 21.996 ;
     RECT  21.371 23.058 21.443 23.346 ;
     RECT  20.615 26.568 21.443 26.586 ;
     RECT  21.443 3.114 21.479 3.744 ;
     RECT  20.543 7.128 21.479 8.226 ;
     RECT  21.307 9.054 21.479 9.072 ;
     RECT  21.407 10.71 21.479 10.854 ;
     RECT  21.415 12.636 21.479 16.362 ;
     RECT  21.443 17.586 21.479 19.026 ;
     RECT  21.443 21.474 21.479 21.798 ;
     RECT  21.479 12.636 21.487 13.968 ;
     RECT  21.479 3.348 21.515 3.744 ;
     RECT  21.415 5.508 21.515 6.174 ;
     RECT  21.479 7.128 21.515 7.758 ;
     RECT  21.479 10.71 21.515 10.728 ;
     RECT  21.487 12.366 21.515 13.968 ;
     RECT  21.479 14.958 21.515 16.362 ;
     RECT  21.479 18.036 21.515 19.026 ;
     RECT  21.443 20.016 21.515 20.214 ;
     RECT  21.479 21.78 21.515 21.798 ;
     RECT  21.443 23.328 21.515 23.346 ;
     RECT  21.415 28.26 21.515 29.826 ;
     RECT  20.579 30.582 21.515 30.6 ;
     RECT  20.543 31.968 21.515 31.986 ;
     RECT  21.515 12.366 21.587 12.384 ;
     RECT  21.515 16.344 21.587 16.362 ;
     RECT  21.515 18.774 21.587 18.792 ;
     RECT  21.515 20.016 21.587 20.034 ;
    LAYER M3 ;
     RECT  21.42 1.099 21.438 1.291 ;
     RECT  13.104 0.091 13.122 1.957 ;
     RECT  21.384 1.291 21.438 1.963 ;
     RECT  18.54 1.867 18.558 2.011 ;
     RECT  5.256 1.993 5.67 2.029 ;
     RECT  17.496 1.957 17.514 2.059 ;
     RECT  6.912 1.993 6.93 2.065 ;
     RECT  17.496 2.059 17.766 2.065 ;
     RECT  3.024 2.029 3.042 2.101 ;
     RECT  11.304 2.065 11.322 2.101 ;
     RECT  14.76 1.993 14.778 2.101 ;
     RECT  15.696 2.065 15.714 2.101 ;
     RECT  16.992 2.065 17.766 2.101 ;
     RECT  18.54 2.011 18.774 2.101 ;
     RECT  16.704 2.101 17.766 2.107 ;
     RECT  18.54 2.101 18.954 2.107 ;
     RECT  3.024 2.101 3.366 2.143 ;
     RECT  10.368 2.101 10.386 2.143 ;
     RECT  11.124 2.101 11.322 2.143 ;
     RECT  13.104 1.957 13.194 2.143 ;
     RECT  14.76 2.101 15.714 2.143 ;
     RECT  16.704 2.107 18.954 2.143 ;
     RECT  2.415 2.143 3.366 2.191 ;
     RECT  4.788 2.029 5.67 2.191 ;
     RECT  6.84 2.065 6.93 2.191 ;
     RECT  7.815 2.143 7.905 2.191 ;
     RECT  10.368 2.143 11.322 2.191 ;
     RECT  14.76 2.143 18.954 2.191 ;
     RECT  2.415 2.191 5.67 2.227 ;
     RECT  14.292 2.191 18.954 2.251 ;
     RECT  21.276 1.963 21.438 2.251 ;
     RECT  2.34 2.227 5.67 2.263 ;
     RECT  10.008 2.191 11.43 2.299 ;
     RECT  14.112 2.251 18.954 2.299 ;
     RECT  20.52 1.579 20.538 2.333 ;
     RECT  6.444 2.191 6.93 2.335 ;
     RECT  7.815 2.191 8.154 2.335 ;
     RECT  9.864 2.299 12.15 2.335 ;
     RECT  2.34 2.263 5.706 2.371 ;
     RECT  9.18 2.335 12.15 2.371 ;
     RECT  13.104 2.143 13.305 2.371 ;
     RECT  14.112 2.299 18.99 2.371 ;
     RECT  9.18 2.371 13.305 2.413 ;
     RECT  14.112 2.371 19.206 2.413 ;
     RECT  2.304 2.371 5.706 2.461 ;
     RECT  6.444 2.335 8.154 2.461 ;
     RECT  0.18 2.251 0.198 2.533 ;
     RECT  9.18 2.413 19.206 2.533 ;
     RECT  8.928 2.533 19.206 2.587 ;
     RECT  8.928 2.587 19.314 2.759 ;
     RECT  0.108 2.533 0.198 2.765 ;
     RECT  2.304 2.461 8.154 2.767 ;
     RECT  8.928 2.759 19.278 2.767 ;
     RECT  0.18 2.765 0.198 2.813 ;
     RECT  2.304 2.767 19.278 3.343 ;
     RECT  21.276 2.251 21.51 3.403 ;
     RECT  21.204 3.403 21.51 3.629 ;
     RECT  1.692 3.343 19.278 3.643 ;
     RECT  21.276 3.629 21.51 3.749 ;
     RECT  0.144 3.499 0.162 3.991 ;
     RECT  0.108 3.991 0.198 4.109 ;
     RECT  0.144 4.109 0.198 4.219 ;
     RECT  0.144 4.219 0.234 4.363 ;
     RECT  21.276 3.749 21.438 4.451 ;
     RECT  0.144 4.363 0.342 4.493 ;
     RECT  20.484 3.787 20.538 4.523 ;
     RECT  1.692 3.643 19.314 4.685 ;
     RECT  2.304 4.685 19.314 4.733 ;
     RECT  21.312 4.451 21.438 4.781 ;
     RECT  2.304 4.733 19.242 5.225 ;
     RECT  0.144 4.493 0.162 5.305 ;
     RECT  20.412 4.555 20.43 5.323 ;
     RECT  2.304 5.225 19.206 5.369 ;
     RECT  20.412 5.323 20.538 5.419 ;
     RECT  21.348 4.781 21.438 5.503 ;
     RECT  20.196 5.419 20.538 5.603 ;
     RECT  0.108 5.305 0.234 5.645 ;
     RECT  20.52 5.603 20.538 5.707 ;
     RECT  21.348 5.503 21.51 5.707 ;
     RECT  1.26 5.803 1.278 5.851 ;
     RECT  0.144 5.645 0.234 5.899 ;
     RECT  1.152 5.851 1.278 6.077 ;
     RECT  20.52 5.707 21.51 6.077 ;
     RECT  2.376 5.369 19.206 6.151 ;
     RECT  21.276 6.077 21.51 6.179 ;
     RECT  21.384 6.179 21.51 6.221 ;
     RECT  2.304 6.151 19.206 6.379 ;
     RECT  20.52 6.077 20.538 6.379 ;
     RECT  20.484 6.379 20.538 6.475 ;
     RECT  0.144 5.899 0.342 6.509 ;
     RECT  0.144 6.509 0.234 6.655 ;
     RECT  20.448 6.475 20.538 6.683 ;
     RECT  0.108 6.655 0.234 6.797 ;
     RECT  2.304 6.379 19.314 6.845 ;
     RECT  12.42 6.845 19.314 6.859 ;
     RECT  20.448 6.683 20.502 6.953 ;
     RECT  20.448 6.953 20.466 6.989 ;
     RECT  0.144 6.797 0.234 7.243 ;
     RECT  2.304 6.845 11.682 7.385 ;
     RECT  21.42 6.221 21.51 7.435 ;
     RECT  21.312 7.435 21.51 7.627 ;
     RECT  0.144 7.243 0.342 7.663 ;
     RECT  1.296 7.627 1.314 7.663 ;
     RECT  12.42 6.859 19.458 7.691 ;
     RECT  1.296 7.663 1.386 7.709 ;
     RECT  0.144 7.663 0.378 7.723 ;
     RECT  0.108 7.723 0.378 7.757 ;
     RECT  21.276 7.627 21.51 7.757 ;
     RECT  0.108 7.757 0.342 7.763 ;
     RECT  21.312 7.757 21.51 7.763 ;
     RECT  2.376 7.385 11.682 7.771 ;
     RECT  12.42 7.691 19.386 7.771 ;
     RECT  2.376 7.771 19.386 7.799 ;
     RECT  0.144 7.763 0.342 7.949 ;
     RECT  0.144 7.949 0.234 8.141 ;
     RECT  2.376 7.799 19.314 8.195 ;
     RECT  21.312 7.763 21.474 8.231 ;
     RECT  0.144 8.141 0.162 8.429 ;
     RECT  1.224 8.299 1.242 8.525 ;
     RECT  2.415 8.195 19.314 8.525 ;
     RECT  21.312 8.231 21.438 8.587 ;
     RECT  14.4 8.525 19.314 8.735 ;
     RECT  20.412 8.299 20.43 8.771 ;
     RECT  15.156 8.735 19.314 8.843 ;
     RECT  21.24 8.587 21.438 9.049 ;
     RECT  21.24 9.049 21.474 9.101 ;
     RECT  2.415 8.525 13.497 9.355 ;
     RECT  2.376 9.355 13.497 9.391 ;
     RECT  2.34 9.391 13.497 9.517 ;
     RECT  2.268 9.517 13.497 9.661 ;
     RECT  14.4 8.735 14.418 9.661 ;
     RECT  15.444 8.843 19.314 9.751 ;
     RECT  2.268 9.661 14.418 9.859 ;
     RECT  21.312 9.101 21.402 9.869 ;
     RECT  21.384 9.869 21.402 9.931 ;
     RECT  2.268 9.859 14.526 10.075 ;
     RECT  2.232 10.075 14.526 10.319 ;
     RECT  0.144 10.363 0.162 10.399 ;
     RECT  1.152 9.787 1.17 10.399 ;
     RECT  0.144 10.399 1.17 10.427 ;
     RECT  15.336 9.751 19.314 10.507 ;
     RECT  2.268 10.319 14.526 10.699 ;
     RECT  15.336 10.507 19.386 10.699 ;
     RECT  21.384 9.931 21.438 10.699 ;
     RECT  21.384 10.699 21.51 10.705 ;
     RECT  21.312 10.705 21.51 10.733 ;
     RECT  21.312 10.733 21.474 10.829 ;
     RECT  2.268 10.699 19.386 10.895 ;
     RECT  0.144 10.427 0.666 11.309 ;
     RECT  0.144 11.309 0.198 11.407 ;
     RECT  0.108 11.407 0.198 11.549 ;
     RECT  0.108 11.549 0.162 11.597 ;
     RECT  21.348 10.829 21.474 11.755 ;
     RECT  1.26 11.467 1.278 11.885 ;
     RECT  21.276 11.755 21.474 12.331 ;
     RECT  21.276 12.331 21.51 12.361 ;
     RECT  2.304 10.895 19.386 12.523 ;
     RECT  0.144 11.597 0.162 12.571 ;
     RECT  2.304 12.523 19.422 12.653 ;
     RECT  21.276 12.361 21.582 13.037 ;
     RECT  20.52 12.325 20.538 13.133 ;
     RECT  21.348 13.037 21.582 13.229 ;
     RECT  0.144 12.571 0.234 13.483 ;
     RECT  0.144 13.483 0.342 13.613 ;
     RECT  2.304 12.653 19.314 13.981 ;
     RECT  1.368 13.867 1.386 14.059 ;
     RECT  0.144 13.613 0.306 14.093 ;
     RECT  1.152 14.059 1.386 14.107 ;
     RECT  2.268 13.981 19.314 14.107 ;
     RECT  1.152 14.107 19.314 14.189 ;
     RECT  1.368 14.189 19.314 14.237 ;
     RECT  0.144 14.093 0.234 14.251 ;
     RECT  21.384 13.229 21.582 14.347 ;
     RECT  0.108 14.251 0.234 14.669 ;
     RECT  21.312 14.347 21.582 15.245 ;
     RECT  0.288 15.061 0.558 15.259 ;
     RECT  1.98 14.237 19.314 15.355 ;
     RECT  0.288 15.259 1.134 15.403 ;
     RECT  0.144 15.403 1.17 15.451 ;
     RECT  1.98 15.355 19.386 15.451 ;
     RECT  21.384 15.245 21.582 15.979 ;
     RECT  0.144 15.451 19.386 16.105 ;
     RECT  0.144 16.105 19.962 16.205 ;
     RECT  0.144 16.205 19.314 16.349 ;
     RECT  21.348 15.979 21.582 16.367 ;
     RECT  0.216 16.349 19.314 16.493 ;
     RECT  20.196 16.555 20.214 16.673 ;
     RECT  1.116 16.493 19.314 17.105 ;
     RECT  1.116 17.105 1.206 17.117 ;
     RECT  1.98 17.105 19.314 17.165 ;
     RECT  1.116 17.117 1.17 17.261 ;
     RECT  0.216 16.493 0.378 17.311 ;
     RECT  21.348 16.367 21.438 17.323 ;
     RECT  0.108 17.311 0.378 17.549 ;
     RECT  21.276 17.323 21.51 17.689 ;
     RECT  2.304 17.165 19.314 17.755 ;
     RECT  0.144 17.549 0.378 17.837 ;
     RECT  20.556 17.689 21.51 17.933 ;
     RECT  2.304 17.755 19.386 17.987 ;
     RECT  20.556 17.933 20.574 17.995 ;
     RECT  20.484 17.995 20.574 18.029 ;
     RECT  21.348 17.933 21.51 18.125 ;
     RECT  0.216 17.837 0.378 18.193 ;
     RECT  1.116 17.261 1.134 18.193 ;
     RECT  2.304 17.987 19.314 18.193 ;
     RECT  2.268 18.193 19.314 18.329 ;
     RECT  0.216 18.193 1.134 18.427 ;
     RECT  20.484 18.029 20.502 18.491 ;
     RECT  0.216 18.427 1.206 18.557 ;
     RECT  0.216 18.557 1.17 18.616 ;
     RECT  0.18 18.616 1.17 18.661 ;
     RECT  0.108 18.661 1.17 18.689 ;
     RECT  2.304 18.329 19.314 18.763 ;
     RECT  21.42 18.125 21.51 18.769 ;
     RECT  2.304 18.763 19.854 18.869 ;
     RECT  21.42 18.769 21.582 19.051 ;
     RECT  21.384 19.051 21.582 19.301 ;
     RECT  0.108 18.689 0.846 19.579 ;
     RECT  0.108 19.579 1.17 19.757 ;
     RECT  0.18 19.757 1.17 19.805 ;
     RECT  2.376 18.869 19.854 19.841 ;
     RECT  2.376 19.841 19.35 19.885 ;
     RECT  21.42 19.301 21.582 20.039 ;
     RECT  21.42 20.039 21.51 20.059 ;
     RECT  2.304 19.885 19.35 20.111 ;
     RECT  21.384 20.059 21.51 20.237 ;
     RECT  0.216 19.805 1.17 20.299 ;
     RECT  2.304 20.111 19.134 20.309 ;
     RECT  0.216 20.299 1.35 20.347 ;
     RECT  20.484 20.119 20.502 20.429 ;
     RECT  21.384 20.237 21.438 20.525 ;
     RECT  0.216 20.347 1.422 20.587 ;
     RECT  2.304 20.309 19.098 20.587 ;
     RECT  0.216 20.587 19.098 20.635 ;
     RECT  0.144 20.635 19.098 20.875 ;
     RECT  0.108 20.875 19.098 20.909 ;
     RECT  20.52 20.695 20.538 20.965 ;
     RECT  0.108 20.909 0.846 20.993 ;
     RECT  20.52 20.965 20.574 21.005 ;
     RECT  20.556 21.005 20.574 21.101 ;
     RECT  1.728 20.909 19.098 21.211 ;
     RECT  21.42 20.525 21.438 21.355 ;
     RECT  21.312 21.355 21.438 21.451 ;
     RECT  0.144 20.993 0.846 21.691 ;
     RECT  1.728 21.211 19.314 21.691 ;
     RECT  21.312 21.451 21.474 21.739 ;
     RECT  21.312 21.739 21.51 21.773 ;
     RECT  21.42 21.773 21.51 21.803 ;
     RECT  0.144 21.691 19.314 21.869 ;
     RECT  0.828 21.869 19.314 22.045 ;
     RECT  0.828 22.045 19.35 22.157 ;
     RECT  1.152 22.157 19.35 22.205 ;
     RECT  21.42 21.803 21.438 22.585 ;
     RECT  21.348 22.585 21.438 22.699 ;
     RECT  1.152 22.205 19.314 22.781 ;
     RECT  0.144 22.987 0.162 23.179 ;
     RECT  21.348 22.699 21.51 23.179 ;
     RECT  21.312 23.179 21.51 23.351 ;
     RECT  0.144 23.179 0.234 23.629 ;
     RECT  0.144 23.629 0.342 23.659 ;
     RECT  20.52 22.315 20.538 23.665 ;
     RECT  0.108 23.659 0.342 23.774 ;
     RECT  21.312 23.351 21.33 23.885 ;
     RECT  20.52 23.665 20.574 24.077 ;
     RECT  1.728 22.781 19.314 24.091 ;
     RECT  1.152 24.091 19.314 24.205 ;
     RECT  1.152 24.205 19.962 24.365 ;
     RECT  21.42 24.235 21.438 24.413 ;
     RECT  1.152 24.365 19.386 24.557 ;
     RECT  1.152 24.557 19.314 24.809 ;
     RECT  0.144 23.774 0.342 24.811 ;
     RECT  2.376 24.809 19.314 24.899 ;
     RECT  0.144 24.811 0.378 24.941 ;
     RECT  0.144 24.941 0.342 24.979 ;
     RECT  0.108 24.979 0.342 25.037 ;
     RECT  20.52 25.285 20.538 25.483 ;
     RECT  1.152 24.809 1.17 25.723 ;
     RECT  2.376 24.899 19.242 25.825 ;
     RECT  2.34 25.825 19.386 25.861 ;
     RECT  1.152 25.723 1.242 26.093 ;
     RECT  0.144 25.037 0.342 26.131 ;
     RECT  1.152 26.093 1.17 26.131 ;
     RECT  0.144 26.131 1.17 26.141 ;
     RECT  2.304 25.861 19.386 26.189 ;
     RECT  2.34 26.189 19.386 26.249 ;
     RECT  2.376 26.249 19.386 26.365 ;
     RECT  20.52 25.483 20.646 26.365 ;
     RECT  2.376 26.365 20.646 26.669 ;
     RECT  20.484 26.669 20.646 26.861 ;
     RECT  0.144 26.141 0.558 26.923 ;
     RECT  0.144 26.923 1.17 27.149 ;
     RECT  21.42 26.443 21.438 27.355 ;
     RECT  2.376 26.669 19.386 27.409 ;
     RECT  20.484 26.861 20.61 27.437 ;
     RECT  2.34 27.409 19.386 27.481 ;
     RECT  0.144 27.149 0.63 27.533 ;
     RECT  2.304 27.481 19.386 27.629 ;
     RECT  20.52 27.437 20.61 27.715 ;
     RECT  21.348 27.355 21.438 27.715 ;
     RECT  20.52 27.715 21.438 27.821 ;
     RECT  2.304 27.629 19.062 27.905 ;
     RECT  20.52 27.821 20.646 28.205 ;
     RECT  20.52 28.205 20.538 28.255 ;
     RECT  21.42 27.821 21.438 28.255 ;
     RECT  0.144 27.533 0.162 28.267 ;
     RECT  1.116 27.949 1.17 28.363 ;
     RECT  19.944 28.255 20.538 28.397 ;
     RECT  2.376 27.905 19.062 28.411 ;
     RECT  2.376 28.411 19.314 28.445 ;
     RECT  1.116 28.363 1.422 28.493 ;
     RECT  1.116 28.493 1.386 28.733 ;
     RECT  1.188 28.733 1.314 28.781 ;
     RECT  0.144 28.267 0.234 28.843 ;
     RECT  20.52 28.397 20.538 28.877 ;
     RECT  21.42 28.255 21.51 29.021 ;
     RECT  0.144 28.843 0.27 29.131 ;
     RECT  0.144 29.131 0.342 29.371 ;
     RECT  19.944 29.335 19.962 29.453 ;
     RECT  0.108 29.371 0.342 29.569 ;
     RECT  1.188 28.781 1.278 29.569 ;
     RECT  2.376 28.445 19.098 29.641 ;
     RECT  21.492 29.021 21.51 29.755 ;
     RECT  2.304 29.641 19.098 29.851 ;
     RECT  0.108 29.569 1.278 29.995 ;
     RECT  20.52 29.995 20.538 30.073 ;
     RECT  0.108 29.995 1.386 30.125 ;
     RECT  0.108 30.125 1.314 30.209 ;
     RECT  21.42 29.755 21.51 30.283 ;
     RECT  2.304 29.851 19.314 30.335 ;
     RECT  21.312 30.283 21.51 30.413 ;
     RECT  20.52 30.073 20.574 30.605 ;
     RECT  21.492 30.413 21.51 30.605 ;
     RECT  0.108 30.209 1.278 30.749 ;
     RECT  0.144 30.749 1.278 30.941 ;
     RECT  2.34 30.335 19.314 31.225 ;
     RECT  0.18 30.941 1.278 31.277 ;
     RECT  2.304 31.225 19.314 31.415 ;
     RECT  21.492 31.627 21.51 31.675 ;
     RECT  1.152 31.277 1.278 31.723 ;
     RECT  2.304 31.415 19.17 31.723 ;
     RECT  20.52 30.605 20.538 31.793 ;
     RECT  0.18 31.277 0.234 31.801 ;
     RECT  0.108 31.801 0.234 31.853 ;
     RECT  21.42 31.675 21.51 31.853 ;
     RECT  21.492 31.853 21.51 31.991 ;
     RECT  20.196 31.915 20.214 32.063 ;
     RECT  0.144 31.853 0.234 32.107 ;
     RECT  1.152 31.723 19.17 32.189 ;
     RECT  7.02 32.189 19.098 32.225 ;
     RECT  0.144 32.107 0.342 32.237 ;
     RECT  1.152 32.189 5.274 32.261 ;
     RECT  7.02 32.225 14.814 32.261 ;
     RECT  1.152 32.261 5.205 32.333 ;
     RECT  1.728 32.333 5.205 32.417 ;
     RECT  7.02 32.261 14.346 32.417 ;
     RECT  15.915 32.225 19.062 32.417 ;
     RECT  0.144 32.237 0.27 32.429 ;
     RECT  1.728 32.417 4.95 32.459 ;
     RECT  8.568 32.417 14.346 32.459 ;
     RECT  16.488 32.417 18.27 32.459 ;
     RECT  19.044 32.417 19.062 32.459 ;
     RECT  16.488 32.459 16.506 32.495 ;
     RECT  18.036 32.459 18.27 32.495 ;
     RECT  9.432 32.459 13.698 32.525 ;
     RECT  7.02 32.417 7.578 32.531 ;
     RECT  1.728 32.459 4.878 32.567 ;
     RECT  8.568 32.459 8.586 32.567 ;
     RECT  10.656 32.525 13.698 32.573 ;
     RECT  1.728 32.567 4.014 32.603 ;
     RECT  2.34 32.603 4.014 32.639 ;
     RECT  4.788 32.567 4.878 32.669 ;
     RECT  2.34 32.639 3.438 32.684 ;
     RECT  9.432 32.525 9.81 32.717 ;
     RECT  18.036 32.495 18.054 32.729 ;
     RECT  0.144 32.429 0.162 32.765 ;
     RECT  2.34 32.684 3.222 32.765 ;
     RECT  10.836 32.573 13.698 32.765 ;
     RECT  4.86 32.669 4.878 32.801 ;
     RECT  7.56 32.531 7.578 32.801 ;
     RECT  2.34 32.765 3.042 33.071 ;
     RECT  10.944 32.765 13.05 33.101 ;
     RECT  2.556 33.071 3.042 33.107 ;
     RECT  3.024 33.107 3.042 33.143 ;
     RECT  10.944 33.101 11.862 33.197 ;
     RECT  12.708 33.101 13.05 33.293 ;
     RECT  9.72 32.717 9.81 33.389 ;
     RECT  10.944 33.197 11.538 33.485 ;
     RECT  10.944 33.485 10.962 33.581 ;
     RECT  12.708 33.293 12.726 33.611 ;
     RECT  9.72 33.389 9.738 33.677 ;
     RECT  10.836 33.583 10.854 33.773 ;
    LAYER M4 ;
     RECT  0.084 2.352 0.169 2.376 ;
     RECT  0.06 2.376 0.169 2.448 ;
     RECT  0.084 2.448 0.169 2.472 ;
     RECT  0.06 2.472 0.169 2.544 ;
     RECT  0.084 2.544 0.169 2.568 ;
     RECT  0.06 2.568 0.169 2.64 ;
     RECT  0.084 2.64 0.169 2.664 ;
     RECT  0.06 2.664 0.169 2.736 ;
     RECT  0.084 2.736 0.169 2.76 ;
     RECT  0.06 2.76 0.169 2.832 ;
     RECT  0.084 2.832 0.169 2.856 ;
     RECT  0.06 2.856 0.169 2.928 ;
     RECT  0.084 2.928 0.169 2.952 ;
     RECT  0.06 2.952 0.169 3.024 ;
     RECT  0.084 3.024 0.169 3.048 ;
     RECT  0.06 3.048 0.169 3.12 ;
     RECT  0.084 3.12 0.169 3.144 ;
     RECT  0.06 3.144 0.169 3.216 ;
     RECT  0.084 3.216 0.169 3.24 ;
     RECT  0.06 3.24 0.169 3.312 ;
     RECT  0.084 3.312 0.169 3.336 ;
     RECT  0.06 3.336 0.169 3.408 ;
     RECT  0.084 3.408 0.169 3.432 ;
     RECT  0.06 3.432 0.169 3.504 ;
     RECT  0.084 3.504 0.169 3.528 ;
     RECT  0.06 3.528 0.169 3.6 ;
     RECT  0.084 3.6 0.169 3.624 ;
     RECT  0.06 3.624 0.169 3.696 ;
     RECT  0.084 3.696 0.169 3.72 ;
     RECT  0.06 3.72 0.169 3.792 ;
     RECT  0.084 3.792 0.169 3.816 ;
     RECT  0.06 3.816 0.169 3.888 ;
     RECT  0.084 3.888 0.169 3.912 ;
     RECT  0.06 3.912 0.169 3.984 ;
     RECT  0.084 3.984 0.169 4.008 ;
     RECT  0.06 4.008 0.169 4.08 ;
     RECT  0.084 4.08 0.169 4.104 ;
     RECT  0.06 4.104 0.169 4.176 ;
     RECT  0.084 4.176 0.169 4.2 ;
     RECT  0.06 4.2 0.169 4.272 ;
     RECT  0.084 4.272 0.169 4.296 ;
     RECT  0.06 4.296 0.169 4.368 ;
     RECT  0.084 4.368 0.169 4.392 ;
     RECT  0.06 4.392 0.169 4.464 ;
     RECT  0.084 4.464 0.169 4.488 ;
     RECT  0.06 4.488 0.169 4.56 ;
     RECT  0.084 4.56 0.169 4.584 ;
     RECT  0.06 4.584 0.169 4.656 ;
     RECT  0.084 4.656 0.169 4.68 ;
     RECT  0.06 4.68 0.169 4.752 ;
     RECT  0.084 4.752 0.169 4.776 ;
     RECT  0.06 4.776 0.169 4.848 ;
     RECT  0.084 4.848 0.169 4.872 ;
     RECT  0.06 4.872 0.169 4.944 ;
     RECT  0.084 4.944 0.169 4.968 ;
     RECT  0.06 4.968 0.169 5.04 ;
     RECT  0.084 5.04 0.169 5.064 ;
     RECT  0.06 5.064 0.169 5.136 ;
     RECT  0.084 5.136 0.169 5.16 ;
     RECT  0.06 5.16 0.169 5.232 ;
     RECT  0.084 5.232 0.169 5.256 ;
     RECT  0.06 5.256 0.169 5.328 ;
     RECT  0.084 5.328 0.169 5.352 ;
     RECT  0.06 5.352 0.169 5.424 ;
     RECT  0.084 5.424 0.169 5.448 ;
     RECT  0.06 5.448 0.169 5.52 ;
     RECT  0.084 5.52 0.169 5.544 ;
     RECT  0.06 5.544 0.169 5.616 ;
     RECT  0.084 5.616 0.169 5.64 ;
     RECT  0.06 5.64 0.169 5.712 ;
     RECT  0.084 5.712 0.169 5.736 ;
     RECT  0.06 5.736 0.169 5.808 ;
     RECT  0.084 5.808 0.169 5.832 ;
     RECT  0.06 5.832 0.169 5.904 ;
     RECT  0.084 5.904 0.169 5.928 ;
     RECT  0.06 5.928 0.169 6 ;
     RECT  0.084 6 0.169 6.024 ;
     RECT  0.06 6.024 0.169 6.096 ;
     RECT  0.084 6.096 0.169 6.12 ;
     RECT  0.06 6.12 0.169 6.192 ;
     RECT  0.084 6.192 0.169 6.216 ;
     RECT  0.06 6.216 0.169 6.288 ;
     RECT  0.084 6.288 0.169 6.312 ;
     RECT  0.06 6.312 0.169 6.384 ;
     RECT  0.084 6.384 0.169 6.408 ;
     RECT  0.06 6.408 0.169 6.48 ;
     RECT  0.084 6.48 0.169 6.504 ;
     RECT  0.06 6.504 0.169 6.576 ;
     RECT  0.084 6.576 0.169 6.6 ;
     RECT  0.06 6.6 0.169 6.672 ;
     RECT  0.084 6.672 0.169 6.696 ;
     RECT  0.06 6.696 0.169 6.768 ;
     RECT  0.084 6.768 0.169 6.792 ;
     RECT  0.06 6.792 0.169 6.864 ;
     RECT  0.084 6.864 0.169 6.888 ;
     RECT  0.06 6.888 0.169 6.96 ;
     RECT  0.084 6.96 0.169 6.984 ;
     RECT  0.06 6.984 0.169 7.056 ;
     RECT  0.084 7.056 0.169 7.08 ;
     RECT  0.06 7.08 0.169 7.152 ;
     RECT  0.084 7.152 0.169 7.176 ;
     RECT  0.06 7.176 0.169 7.248 ;
     RECT  0.084 7.248 0.169 7.272 ;
     RECT  0.06 7.272 0.169 7.344 ;
     RECT  0.084 7.344 0.169 7.368 ;
     RECT  0.06 7.368 0.169 7.44 ;
     RECT  0.084 7.44 0.169 7.464 ;
     RECT  0.06 7.464 0.169 7.536 ;
     RECT  0.084 7.536 0.169 7.56 ;
     RECT  0.06 7.56 0.169 7.632 ;
     RECT  0.084 7.632 0.169 7.656 ;
     RECT  0.06 7.656 0.169 7.728 ;
     RECT  0.084 7.728 0.169 7.752 ;
     RECT  0.06 7.752 0.169 7.824 ;
     RECT  0.084 7.824 0.169 7.848 ;
     RECT  0.06 7.848 0.169 7.92 ;
     RECT  0.084 7.92 0.169 7.944 ;
     RECT  0.06 7.944 0.169 8.016 ;
     RECT  0.084 8.016 0.169 8.04 ;
     RECT  0.06 8.04 0.169 8.112 ;
     RECT  0.084 8.112 0.169 8.136 ;
     RECT  0.06 8.136 0.169 8.208 ;
     RECT  0.084 8.208 0.169 8.232 ;
     RECT  0.06 8.232 0.169 8.304 ;
     RECT  0.084 8.304 0.169 8.328 ;
     RECT  0.06 8.328 0.169 8.4 ;
     RECT  0.084 8.4 0.169 8.424 ;
     RECT  0.169 2.256 0.173 8.424 ;
     RECT  0.173 2.256 0.227 8.328 ;
     RECT  0.084 9.84 1.141 9.864 ;
     RECT  0.06 9.864 1.141 9.936 ;
     RECT  0.084 9.936 1.141 9.96 ;
     RECT  0.06 9.96 1.141 10.032 ;
     RECT  0.084 10.032 1.141 10.056 ;
     RECT  0.06 10.056 1.141 10.128 ;
     RECT  0.084 10.128 1.141 10.152 ;
     RECT  0.06 10.152 1.141 10.224 ;
     RECT  0.084 10.224 1.141 10.248 ;
     RECT  0.06 10.248 1.141 10.32 ;
     RECT  0.084 10.32 1.141 10.344 ;
     RECT  0.06 10.344 1.141 10.416 ;
     RECT  0.084 10.416 1.141 10.44 ;
     RECT  0.06 10.44 1.141 10.512 ;
     RECT  0.084 10.512 1.141 10.536 ;
     RECT  0.06 10.536 1.141 10.608 ;
     RECT  0.084 10.608 1.141 10.632 ;
     RECT  0.06 10.632 1.141 10.704 ;
     RECT  0.084 10.704 1.141 10.728 ;
     RECT  0.06 10.728 1.141 10.8 ;
     RECT  0.084 10.8 1.141 10.824 ;
     RECT  0.06 10.824 1.141 10.896 ;
     RECT  0.084 10.896 1.141 10.92 ;
     RECT  0.06 10.92 1.141 10.992 ;
     RECT  0.084 10.992 1.141 11.016 ;
     RECT  0.06 11.016 1.141 11.088 ;
     RECT  0.084 11.088 1.141 11.112 ;
     RECT  0.06 11.112 1.141 11.184 ;
     RECT  0.084 11.184 1.141 11.208 ;
     RECT  0.06 11.208 1.141 11.28 ;
     RECT  0.084 11.28 1.141 11.304 ;
     RECT  0.06 11.304 1.141 11.376 ;
     RECT  0.084 11.376 1.141 11.4 ;
     RECT  0.06 11.4 1.141 11.472 ;
     RECT  0.084 11.472 1.141 11.496 ;
     RECT  0.06 11.496 1.141 11.568 ;
     RECT  0.084 11.568 1.141 11.592 ;
     RECT  0.06 11.592 1.141 11.664 ;
     RECT  0.084 11.664 1.141 11.688 ;
     RECT  0.06 11.688 1.141 11.76 ;
     RECT  0.084 11.76 1.141 11.784 ;
     RECT  0.06 11.784 1.141 11.856 ;
     RECT  0.084 11.856 1.141 11.88 ;
     RECT  0.06 11.88 1.141 11.952 ;
     RECT  0.084 11.952 1.141 11.976 ;
     RECT  0.06 11.976 1.141 12.048 ;
     RECT  0.084 12.048 1.141 12.072 ;
     RECT  0.06 12.072 1.141 12.144 ;
     RECT  0.084 12.144 1.141 12.168 ;
     RECT  0.06 12.168 1.141 12.24 ;
     RECT  0.084 12.24 1.141 12.264 ;
     RECT  0.06 12.264 1.141 12.336 ;
     RECT  0.084 12.336 1.141 12.36 ;
     RECT  0.06 12.36 1.141 12.432 ;
     RECT  0.084 12.432 1.141 12.456 ;
     RECT  0.06 12.456 1.141 12.528 ;
     RECT  0.084 12.528 1.141 12.552 ;
     RECT  0.06 12.552 1.141 12.624 ;
     RECT  0.084 12.624 1.141 12.648 ;
     RECT  0.06 12.648 1.141 12.72 ;
     RECT  0.084 12.72 1.141 12.744 ;
     RECT  0.06 12.744 1.141 12.816 ;
     RECT  0.084 12.816 1.141 12.84 ;
     RECT  0.06 12.84 1.141 12.912 ;
     RECT  0.084 12.912 1.141 12.936 ;
     RECT  0.06 12.936 1.141 13.008 ;
     RECT  0.084 13.008 1.141 13.032 ;
     RECT  0.06 13.032 1.141 13.104 ;
     RECT  0.084 13.104 1.141 13.128 ;
     RECT  0.06 13.128 1.141 13.2 ;
     RECT  0.084 13.2 1.141 13.224 ;
     RECT  0.06 13.224 1.141 13.296 ;
     RECT  0.084 13.296 1.141 13.32 ;
     RECT  0.06 13.32 1.141 13.392 ;
     RECT  0.084 13.392 1.141 13.416 ;
     RECT  0.06 13.416 1.141 13.488 ;
     RECT  0.084 13.488 1.141 13.512 ;
     RECT  0.06 13.512 1.141 13.584 ;
     RECT  0.084 13.584 1.141 13.608 ;
     RECT  0.06 13.608 1.141 13.68 ;
     RECT  0.084 13.68 1.141 13.704 ;
     RECT  0.06 13.704 1.141 13.776 ;
     RECT  0.084 13.776 1.141 13.8 ;
     RECT  0.06 13.8 1.141 13.872 ;
     RECT  0.084 13.872 1.141 13.896 ;
     RECT  0.06 13.896 1.141 13.968 ;
     RECT  0.084 13.968 1.141 13.992 ;
     RECT  0.06 13.992 1.141 14.064 ;
     RECT  0.084 14.064 1.141 14.088 ;
     RECT  0.06 14.088 1.141 14.16 ;
     RECT  0.084 14.16 1.141 14.184 ;
     RECT  0.06 14.184 1.141 14.256 ;
     RECT  0.084 14.256 1.141 14.28 ;
     RECT  0.06 14.28 1.141 14.352 ;
     RECT  0.084 14.352 1.141 14.376 ;
     RECT  0.06 14.376 1.141 14.448 ;
     RECT  0.084 14.448 1.141 14.472 ;
     RECT  0.06 14.472 1.141 14.544 ;
     RECT  0.084 14.544 1.141 14.568 ;
     RECT  0.06 14.568 1.141 15.408 ;
     RECT  0.084 15.408 1.141 15.432 ;
     RECT  0.06 15.432 1.141 15.504 ;
     RECT  0.084 15.504 1.141 15.528 ;
     RECT  0.06 15.528 1.141 15.6 ;
     RECT  0.084 15.6 1.141 15.624 ;
     RECT  0.06 15.624 1.141 15.696 ;
     RECT  0.084 15.696 1.141 15.72 ;
     RECT  0.06 15.72 1.141 15.792 ;
     RECT  0.084 15.792 1.141 15.816 ;
     RECT  0.06 15.816 1.141 15.888 ;
     RECT  0.084 15.888 1.141 15.912 ;
     RECT  0.06 15.912 1.141 15.984 ;
     RECT  0.084 15.984 1.141 16.008 ;
     RECT  0.06 16.008 1.141 16.08 ;
     RECT  0.084 16.08 1.141 16.104 ;
     RECT  0.06 16.104 1.141 16.176 ;
     RECT  0.084 16.176 1.141 16.2 ;
     RECT  0.06 16.2 1.141 16.272 ;
     RECT  0.084 16.272 1.141 16.296 ;
     RECT  0.06 16.296 1.141 16.368 ;
     RECT  0.084 16.368 1.141 16.392 ;
     RECT  0.06 16.392 1.141 16.464 ;
     RECT  0.084 16.464 1.141 16.488 ;
     RECT  0.06 16.488 1.141 16.56 ;
     RECT  0.084 16.56 1.141 16.584 ;
     RECT  0.06 16.584 1.141 16.656 ;
     RECT  0.084 16.656 1.141 16.68 ;
     RECT  0.06 16.68 1.141 16.752 ;
     RECT  0.084 16.752 1.141 16.776 ;
     RECT  0.06 16.776 1.141 16.848 ;
     RECT  0.084 16.848 1.141 16.872 ;
     RECT  0.06 16.872 1.141 16.944 ;
     RECT  0.084 16.944 1.141 16.968 ;
     RECT  0.06 16.968 1.141 17.04 ;
     RECT  0.084 17.04 1.141 17.064 ;
     RECT  0.06 17.064 1.141 17.136 ;
     RECT  0.084 17.136 1.141 17.16 ;
     RECT  0.06 17.16 1.141 17.232 ;
     RECT  0.084 17.232 1.141 17.256 ;
     RECT  0.06 17.256 1.141 17.328 ;
     RECT  0.084 17.328 1.141 17.352 ;
     RECT  0.06 17.352 1.141 17.424 ;
     RECT  0.084 17.424 1.141 17.448 ;
     RECT  0.06 17.448 1.141 17.52 ;
     RECT  0.084 17.52 1.141 17.544 ;
     RECT  0.06 17.544 1.141 17.616 ;
     RECT  0.084 17.616 1.141 17.64 ;
     RECT  0.06 17.64 1.141 17.712 ;
     RECT  0.084 17.712 1.141 17.736 ;
     RECT  0.06 17.736 1.141 17.808 ;
     RECT  0.084 17.808 1.141 17.832 ;
     RECT  0.06 17.832 1.141 17.904 ;
     RECT  0.084 17.904 1.141 17.928 ;
     RECT  0.06 17.928 1.141 18 ;
     RECT  0.084 18 1.141 18.024 ;
     RECT  0.06 18.024 1.141 18.096 ;
     RECT  0.084 18.096 1.141 18.12 ;
     RECT  0.06 18.12 1.141 18.192 ;
     RECT  0.084 18.192 1.141 18.216 ;
     RECT  0.06 18.216 1.141 18.288 ;
     RECT  0.084 18.288 1.141 18.312 ;
     RECT  0.06 18.312 1.141 18.384 ;
     RECT  0.084 18.384 1.141 18.408 ;
     RECT  0.06 18.408 1.141 18.48 ;
     RECT  0.084 18.48 1.141 18.504 ;
     RECT  0.06 18.504 1.141 18.576 ;
     RECT  0.084 18.576 1.141 18.6 ;
     RECT  0.06 18.6 1.141 18.672 ;
     RECT  0.084 18.672 1.141 18.696 ;
     RECT  0.06 18.696 1.141 18.768 ;
     RECT  0.084 18.768 1.141 18.792 ;
     RECT  0.06 18.792 1.141 18.864 ;
     RECT  0.084 18.864 1.141 18.888 ;
     RECT  0.06 18.888 1.141 18.96 ;
     RECT  0.084 18.96 1.141 18.984 ;
     RECT  0.06 18.984 1.141 19.056 ;
     RECT  0.084 19.056 1.141 19.08 ;
     RECT  0.06 19.08 1.141 19.152 ;
     RECT  0.084 19.152 1.141 19.176 ;
     RECT  0.06 19.176 1.141 19.248 ;
     RECT  0.084 19.248 1.141 19.272 ;
     RECT  0.06 19.272 1.141 19.344 ;
     RECT  0.084 19.344 1.141 19.368 ;
     RECT  0.06 19.368 1.141 19.44 ;
     RECT  0.084 19.44 1.141 19.464 ;
     RECT  0.06 19.464 1.141 19.536 ;
     RECT  0.084 19.536 1.141 19.56 ;
     RECT  0.06 19.56 1.141 19.632 ;
     RECT  0.084 19.632 1.141 19.656 ;
     RECT  0.06 19.656 1.141 19.728 ;
     RECT  0.084 19.728 1.141 19.752 ;
     RECT  0.06 19.752 1.141 19.824 ;
     RECT  0.084 19.824 1.141 19.848 ;
     RECT  0.06 19.848 1.141 19.92 ;
     RECT  0.084 19.92 1.141 19.944 ;
     RECT  0.06 19.944 1.141 20.016 ;
     RECT  0.084 20.016 1.141 20.04 ;
     RECT  0.06 20.04 1.141 20.112 ;
     RECT  0.084 20.112 1.141 20.136 ;
     RECT  0.06 20.136 1.141 20.208 ;
     RECT  0.084 20.208 1.141 20.232 ;
     RECT  0.06 20.232 1.141 20.304 ;
     RECT  0.084 20.304 1.141 20.328 ;
     RECT  0.06 20.328 1.141 20.4 ;
     RECT  0.084 20.4 1.141 20.424 ;
     RECT  0.06 20.424 1.141 20.496 ;
     RECT  0.084 20.496 1.141 20.52 ;
     RECT  0.06 20.52 1.141 20.592 ;
     RECT  0.084 20.592 1.141 20.616 ;
     RECT  0.06 20.616 1.141 20.688 ;
     RECT  0.084 20.688 1.141 20.712 ;
     RECT  0.06 20.712 1.141 20.784 ;
     RECT  0.084 20.784 1.141 20.808 ;
     RECT  0.06 20.808 1.141 20.88 ;
     RECT  0.084 20.88 1.141 20.904 ;
     RECT  0.06 20.904 1.141 20.976 ;
     RECT  0.084 20.976 1.141 21 ;
     RECT  0.06 21 1.141 21.072 ;
     RECT  0.084 21.072 1.141 21.096 ;
     RECT  0.06 21.096 1.141 21.168 ;
     RECT  0.084 21.168 1.141 21.192 ;
     RECT  0.06 21.192 1.141 21.264 ;
     RECT  0.084 21.264 1.141 21.288 ;
     RECT  0.06 21.288 1.141 21.36 ;
     RECT  0.084 21.36 1.141 21.384 ;
     RECT  0.06 21.384 1.141 21.456 ;
     RECT  0.084 21.456 1.141 21.48 ;
     RECT  0.06 21.48 1.141 21.552 ;
     RECT  0.084 21.552 1.141 21.576 ;
     RECT  0.06 21.576 1.141 21.648 ;
     RECT  0.084 21.648 1.141 21.672 ;
     RECT  0.06 21.672 1.141 21.744 ;
     RECT  0.084 21.744 1.141 21.768 ;
     RECT  0.06 21.768 1.141 21.84 ;
     RECT  0.084 21.84 1.141 21.864 ;
     RECT  0.06 21.864 1.141 21.936 ;
     RECT  0.084 21.936 1.141 21.96 ;
     RECT  0.06 21.96 1.141 22.032 ;
     RECT  0.084 22.032 1.141 22.056 ;
     RECT  0.06 22.056 1.141 22.128 ;
     RECT  0.084 22.128 1.141 22.152 ;
     RECT  0.06 22.152 1.141 22.224 ;
     RECT  0.084 22.224 1.141 22.248 ;
     RECT  0.06 22.248 1.141 22.32 ;
     RECT  0.084 22.32 1.141 22.344 ;
     RECT  0.06 22.344 1.141 22.416 ;
     RECT  0.084 22.416 1.141 22.44 ;
     RECT  0.06 22.44 1.141 22.512 ;
     RECT  0.084 22.512 1.141 22.536 ;
     RECT  0.06 22.536 1.141 22.608 ;
     RECT  0.084 22.608 1.141 22.632 ;
     RECT  0.06 22.632 1.141 22.704 ;
     RECT  0.084 22.704 1.141 22.728 ;
     RECT  0.06 22.728 1.141 22.8 ;
     RECT  0.084 22.8 1.141 22.824 ;
     RECT  0.06 22.824 1.141 22.896 ;
     RECT  0.084 22.896 1.141 22.92 ;
     RECT  0.06 22.92 1.141 22.992 ;
     RECT  0.084 22.992 1.141 23.016 ;
     RECT  0.06 23.016 1.141 23.088 ;
     RECT  0.084 23.088 1.141 23.112 ;
     RECT  0.06 23.112 1.141 23.184 ;
     RECT  0.084 23.184 1.141 23.208 ;
     RECT  0.06 23.208 1.141 23.28 ;
     RECT  0.084 23.28 1.141 23.304 ;
     RECT  0.06 23.304 1.141 23.376 ;
     RECT  0.084 23.376 1.141 23.4 ;
     RECT  0.06 23.4 1.141 23.472 ;
     RECT  0.084 23.472 1.141 23.496 ;
     RECT  0.06 23.496 1.141 23.568 ;
     RECT  0.084 23.568 1.141 23.592 ;
     RECT  0.06 23.592 1.141 23.664 ;
     RECT  0.084 23.664 1.141 23.688 ;
     RECT  0.06 23.688 1.141 23.76 ;
     RECT  0.084 23.76 1.141 23.784 ;
     RECT  0.06 23.784 1.141 23.856 ;
     RECT  0.084 23.856 1.141 23.88 ;
     RECT  0.06 23.88 1.141 23.952 ;
     RECT  0.084 23.952 1.141 23.976 ;
     RECT  0.06 23.976 1.141 24.048 ;
     RECT  0.084 24.048 1.141 24.072 ;
     RECT  0.06 24.072 1.141 24.144 ;
     RECT  0.084 24.144 1.141 24.168 ;
     RECT  0.06 24.168 1.141 24.24 ;
     RECT  0.084 24.24 1.141 24.264 ;
     RECT  0.06 24.264 1.141 24.336 ;
     RECT  0.084 24.336 1.141 24.36 ;
     RECT  0.06 24.36 1.141 24.432 ;
     RECT  0.084 24.432 1.141 24.456 ;
     RECT  0.06 24.456 1.141 24.528 ;
     RECT  0.084 24.528 1.141 24.552 ;
     RECT  0.06 24.552 1.141 24.624 ;
     RECT  0.084 24.624 1.141 24.648 ;
     RECT  0.06 24.648 1.141 24.72 ;
     RECT  0.084 24.72 1.141 24.744 ;
     RECT  0.06 24.744 1.141 24.816 ;
     RECT  0.084 24.816 1.141 24.84 ;
     RECT  0.06 24.84 1.141 24.912 ;
     RECT  0.084 24.912 1.141 24.936 ;
     RECT  0.06 24.936 1.141 25.008 ;
     RECT  0.084 25.008 1.141 25.032 ;
     RECT  0.06 25.032 1.141 25.104 ;
     RECT  0.084 25.104 1.141 25.128 ;
     RECT  0.06 25.128 1.141 25.2 ;
     RECT  0.084 25.2 1.141 25.224 ;
     RECT  0.06 25.224 1.141 25.296 ;
     RECT  0.084 25.296 1.141 25.32 ;
     RECT  0.06 25.32 1.141 25.392 ;
     RECT  0.084 25.392 1.141 25.416 ;
     RECT  0.06 25.416 1.141 25.488 ;
     RECT  0.084 25.488 1.141 25.512 ;
     RECT  0.06 25.512 1.141 25.584 ;
     RECT  0.084 25.584 1.141 25.608 ;
     RECT  0.06 25.608 1.141 25.68 ;
     RECT  0.084 25.68 1.141 25.704 ;
     RECT  0.06 25.704 1.141 25.776 ;
     RECT  0.084 25.776 1.141 25.8 ;
     RECT  0.06 25.8 1.141 25.872 ;
     RECT  0.084 25.872 1.141 25.896 ;
     RECT  0.06 25.896 1.141 25.968 ;
     RECT  0.084 25.968 1.141 25.992 ;
     RECT  0.06 25.992 1.141 26.064 ;
     RECT  0.084 26.064 1.141 26.088 ;
     RECT  0.06 26.088 1.141 26.16 ;
     RECT  0.084 26.16 1.141 26.184 ;
     RECT  0.06 26.184 1.141 26.256 ;
     RECT  0.084 26.256 1.141 26.28 ;
     RECT  0.06 26.28 1.141 26.352 ;
     RECT  0.084 26.352 1.141 26.376 ;
     RECT  0.06 26.376 1.141 26.448 ;
     RECT  0.084 26.448 1.141 26.472 ;
     RECT  0.06 26.472 1.141 26.544 ;
     RECT  0.084 26.544 1.141 26.568 ;
     RECT  0.06 26.568 1.141 26.64 ;
     RECT  0.084 26.64 1.141 26.664 ;
     RECT  0.06 26.664 1.141 26.736 ;
     RECT  0.084 26.736 1.141 26.76 ;
     RECT  0.06 26.76 1.141 26.832 ;
     RECT  0.084 26.832 1.141 26.856 ;
     RECT  0.06 26.856 1.141 26.928 ;
     RECT  0.084 26.928 1.141 26.952 ;
     RECT  0.06 26.952 1.141 27.024 ;
     RECT  0.084 27.024 1.141 27.048 ;
     RECT  0.06 27.048 1.141 27.12 ;
     RECT  0.084 27.12 1.141 27.144 ;
     RECT  0.06 27.144 1.141 27.216 ;
     RECT  0.084 27.216 1.141 27.24 ;
     RECT  0.06 27.24 1.141 27.312 ;
     RECT  0.084 27.312 1.141 27.336 ;
     RECT  0.06 27.336 1.141 27.408 ;
     RECT  0.084 27.408 1.141 27.432 ;
     RECT  0.06 27.432 1.141 27.504 ;
     RECT  0.084 27.504 1.141 27.528 ;
     RECT  0.06 27.528 1.141 27.6 ;
     RECT  0.084 27.6 1.141 27.624 ;
     RECT  0.06 27.624 1.141 27.696 ;
     RECT  0.084 27.696 1.141 27.72 ;
     RECT  0.06 27.72 1.141 27.792 ;
     RECT  0.084 27.792 1.141 27.816 ;
     RECT  0.06 27.816 1.141 27.888 ;
     RECT  0.084 27.888 1.141 27.912 ;
     RECT  0.06 27.912 1.141 27.984 ;
     RECT  0.084 27.984 1.141 28.008 ;
     RECT  0.06 28.008 1.141 28.08 ;
     RECT  0.084 28.08 1.141 28.104 ;
     RECT  0.06 28.104 1.141 28.176 ;
     RECT  0.084 28.176 1.141 28.2 ;
     RECT  0.06 28.2 1.141 28.272 ;
     RECT  0.084 28.272 1.141 28.296 ;
     RECT  0.06 28.296 1.141 28.368 ;
     RECT  0.084 28.368 1.141 28.392 ;
     RECT  0.06 28.392 1.141 28.464 ;
     RECT  0.084 28.464 1.141 28.488 ;
     RECT  0.06 28.488 1.141 28.56 ;
     RECT  0.084 28.56 1.141 28.584 ;
     RECT  0.06 28.584 1.141 28.656 ;
     RECT  0.084 28.656 1.141 28.68 ;
     RECT  0.06 28.68 1.141 28.752 ;
     RECT  0.084 28.752 1.141 28.776 ;
     RECT  0.06 28.776 1.141 28.848 ;
     RECT  0.084 28.848 1.141 28.872 ;
     RECT  0.06 28.872 1.141 28.944 ;
     RECT  0.084 28.944 1.141 28.968 ;
     RECT  0.06 28.968 1.141 29.04 ;
     RECT  0.084 29.04 1.141 29.064 ;
     RECT  0.06 29.064 1.141 29.136 ;
     RECT  0.084 29.136 1.141 29.16 ;
     RECT  0.06 29.16 1.141 29.232 ;
     RECT  0.084 29.232 1.141 29.256 ;
     RECT  0.06 29.256 1.141 29.328 ;
     RECT  0.084 29.328 1.141 29.352 ;
     RECT  0.06 29.352 1.141 29.424 ;
     RECT  0.084 29.424 1.141 29.448 ;
     RECT  0.06 29.448 1.141 29.52 ;
     RECT  0.084 29.52 1.141 29.544 ;
     RECT  0.06 29.544 1.141 29.616 ;
     RECT  0.084 29.616 1.141 29.64 ;
     RECT  0.06 29.64 1.141 29.712 ;
     RECT  0.084 29.712 1.141 29.736 ;
     RECT  0.06 29.736 1.141 29.808 ;
     RECT  0.084 29.808 1.141 29.832 ;
     RECT  0.06 29.832 1.141 29.904 ;
     RECT  0.084 29.904 1.141 29.928 ;
     RECT  0.06 29.928 1.141 30 ;
     RECT  0.084 30 1.141 30.024 ;
     RECT  0.06 30.024 1.141 30.096 ;
     RECT  0.084 30.096 1.141 30.12 ;
     RECT  0.06 30.12 1.141 30.192 ;
     RECT  0.084 30.192 1.141 30.216 ;
     RECT  0.06 30.216 1.141 30.288 ;
     RECT  0.084 30.288 1.141 30.312 ;
     RECT  0.06 30.312 1.141 30.384 ;
     RECT  0.084 30.384 1.141 30.408 ;
     RECT  0.06 30.408 1.141 30.48 ;
     RECT  0.084 30.48 1.141 30.504 ;
     RECT  0.06 30.504 1.141 30.576 ;
     RECT  0.084 30.576 1.141 30.6 ;
     RECT  0.06 30.6 1.141 30.672 ;
     RECT  0.084 30.672 1.141 30.696 ;
     RECT  0.06 30.696 1.141 30.768 ;
     RECT  0.084 30.768 1.141 30.792 ;
     RECT  0.06 30.792 1.141 30.864 ;
     RECT  0.084 30.864 1.141 30.888 ;
     RECT  0.06 30.888 1.141 30.96 ;
     RECT  0.084 30.96 1.141 30.984 ;
     RECT  0.06 30.984 1.141 31.056 ;
     RECT  0.084 31.056 1.141 31.08 ;
     RECT  0.06 31.08 1.141 31.152 ;
     RECT  0.084 31.152 1.141 31.176 ;
     RECT  0.06 31.176 1.141 31.248 ;
     RECT  0.084 31.248 1.141 31.272 ;
     RECT  0.06 31.272 1.141 31.344 ;
     RECT  0.084 31.344 1.141 31.368 ;
     RECT  0.06 31.368 1.141 31.44 ;
     RECT  0.084 31.44 1.141 31.464 ;
     RECT  0.06 31.464 1.141 31.536 ;
     RECT  0.084 31.536 1.141 31.56 ;
     RECT  0.06 31.56 1.141 31.632 ;
     RECT  0.084 31.632 1.141 31.656 ;
     RECT  0.06 31.656 1.141 31.728 ;
     RECT  0.084 31.728 1.141 31.752 ;
     RECT  0.06 31.752 1.141 31.824 ;
     RECT  0.084 31.824 1.141 31.848 ;
     RECT  0.06 31.848 1.141 31.92 ;
     RECT  0.084 31.92 1.141 31.944 ;
     RECT  0.06 31.944 1.141 32.016 ;
     RECT  0.084 32.016 1.141 32.04 ;
     RECT  0.06 32.04 1.141 32.112 ;
     RECT  0.084 32.112 1.141 32.136 ;
     RECT  0.06 32.136 1.141 32.208 ;
     RECT  0.084 32.208 1.141 32.232 ;
     RECT  0.06 32.232 1.141 32.304 ;
     RECT  0.084 32.304 1.141 32.328 ;
     RECT  0.06 32.328 1.141 32.4 ;
     RECT  0.084 32.4 1.141 32.424 ;
     RECT  0.06 32.424 1.141 32.496 ;
     RECT  0.084 32.496 1.141 32.52 ;
     RECT  0.06 32.52 1.141 32.592 ;
     RECT  0.084 32.592 1.141 32.616 ;
     RECT  0.06 32.616 1.141 32.688 ;
     RECT  0.084 32.688 1.141 32.712 ;
     RECT  0.06 32.712 1.141 32.784 ;
     RECT  0.084 32.784 1.141 32.808 ;
     RECT  0.06 32.808 1.141 32.88 ;
     RECT  0.084 32.88 1.141 32.904 ;
     RECT  0.06 32.904 1.141 32.976 ;
     RECT  0.084 32.976 1.141 33 ;
     RECT  0.06 33 1.141 33.072 ;
     RECT  0.084 33.072 1.141 33.096 ;
     RECT  0.06 33.096 1.141 33.168 ;
     RECT  0.084 33.168 1.141 33.192 ;
     RECT  0.06 33.192 1.141 33.264 ;
     RECT  0.084 33.264 1.141 33.288 ;
     RECT  0.06 33.288 1.141 33.36 ;
     RECT  0.084 33.36 1.141 33.384 ;
     RECT  0.06 33.384 1.141 33.456 ;
     RECT  0.084 33.456 1.141 33.48 ;
     RECT  0.06 33.48 1.141 33.552 ;
     RECT  0.084 33.552 1.141 33.576 ;
     RECT  0.06 33.576 1.141 33.648 ;
     RECT  0.084 33.648 1.141 33.672 ;
     RECT  0.06 33.672 1.141 33.744 ;
     RECT  0.084 33.744 1.141 33.768 ;
     RECT  0.227 2.352 1.213 8.328 ;
     RECT  1.213 2.352 2.408 8.52 ;
     RECT  1.141 9.792 2.408 33.768 ;
     RECT  2.408 2.148 2.512 33.768 ;
     RECT  2.512 2.352 2.765 33.768 ;
     RECT  2.765 2.352 4.489 8.808 ;
     RECT  2.765 9.792 4.489 33.768 ;
     RECT  4.489 2.352 5.108 33.768 ;
     RECT  5.108 2.148 5.212 33.768 ;
     RECT  5.212 2.352 7.808 33.768 ;
     RECT  7.808 2.148 7.912 33.768 ;
     RECT  7.912 2.418 8.104 33.768 ;
     RECT  8.104 2.544 8.165 2.616 ;
     RECT  8.165 2.592 9.313 2.616 ;
     RECT  8.104 3.696 9.313 33.768 ;
     RECT  9.313 2.592 9.853 33.768 ;
     RECT  9.853 2.304 9.997 33.768 ;
     RECT  9.997 2.208 10.508 33.768 ;
     RECT  10.508 2.148 10.612 33.768 ;
     RECT  10.612 2.304 10.865 33.768 ;
     RECT  10.865 2.304 10.973 33.576 ;
     RECT  10.973 2.304 11.549 33.48 ;
     RECT  11.549 2.304 12.161 33.288 ;
     RECT  12.161 2.352 13.061 33.288 ;
     RECT  13.093 0.096 13.139 0.12 ;
     RECT  13.061 2.352 13.208 32.412 ;
     RECT  13.208 2.148 13.312 32.412 ;
     RECT  13.312 2.256 13.817 32.232 ;
     RECT  13.817 2.256 14.281 31.896 ;
     RECT  14.281 2.208 14.339 31.896 ;
     RECT  14.339 2.256 14.785 31.896 ;
     RECT  14.785 2.256 15.908 31.992 ;
     RECT  15.908 2.148 16.012 32.412 ;
     RECT  16.012 2.148 16.204 32.142 ;
     RECT  16.204 2.148 16.357 31.992 ;
     RECT  16.357 2.112 17.737 31.992 ;
     RECT  17.737 2.064 18.181 31.992 ;
     RECT  18.181 1.2 18.277 31.992 ;
     RECT  18.277 1.2 18.469 32.04 ;
     RECT  18.469 0.72 18.608 32.04 ;
     RECT  18.608 0.72 18.712 32.412 ;
     RECT  18.712 0.72 18.904 32.142 ;
     RECT  18.904 0.72 19.187 25.08 ;
     RECT  19.187 0.72 19.325 24.696 ;
     RECT  19.325 0.72 21.373 18.888 ;
     RECT  19.325 19.92 21.373 24.552 ;
     RECT  21.373 0.72 21.516 0.744 ;
     RECT  21.373 0.744 21.564 0.816 ;
     RECT  21.373 0.816 21.516 0.84 ;
     RECT  21.373 0.84 21.564 0.912 ;
     RECT  21.373 0.912 21.516 0.936 ;
     RECT  21.373 0.936 21.564 1.008 ;
     RECT  21.373 1.008 21.516 1.032 ;
     RECT  21.373 1.032 21.564 1.104 ;
     RECT  21.373 1.104 21.516 1.128 ;
     RECT  21.373 1.128 21.564 1.2 ;
     RECT  21.373 1.2 21.516 1.224 ;
     RECT  21.373 1.224 21.564 1.296 ;
     RECT  21.373 1.296 21.516 1.32 ;
     RECT  21.373 1.32 21.564 1.392 ;
     RECT  21.373 1.392 21.516 1.416 ;
     RECT  21.373 1.416 21.564 1.488 ;
     RECT  21.373 1.488 21.516 1.512 ;
     RECT  21.373 1.512 21.564 1.584 ;
     RECT  21.373 1.584 21.516 1.608 ;
     RECT  21.373 1.608 21.564 1.68 ;
     RECT  21.373 1.68 21.516 1.704 ;
     RECT  21.373 1.704 21.564 1.776 ;
     RECT  21.373 1.776 21.516 1.8 ;
     RECT  21.373 1.8 21.564 1.872 ;
     RECT  21.373 1.872 21.516 1.896 ;
     RECT  21.373 1.896 21.564 1.968 ;
     RECT  21.373 1.968 21.516 1.992 ;
     RECT  21.373 1.992 21.564 2.064 ;
     RECT  21.373 2.064 21.516 2.088 ;
     RECT  21.373 2.088 21.564 2.16 ;
     RECT  21.373 2.16 21.516 2.184 ;
     RECT  21.373 2.184 21.564 2.256 ;
     RECT  21.373 2.256 21.516 2.28 ;
     RECT  21.373 2.28 21.564 2.352 ;
     RECT  21.373 2.352 21.516 2.376 ;
     RECT  21.373 2.376 21.564 2.448 ;
     RECT  21.373 2.448 21.516 2.472 ;
     RECT  21.373 2.472 21.564 2.544 ;
     RECT  21.373 2.544 21.516 2.568 ;
     RECT  21.373 2.568 21.564 2.64 ;
     RECT  21.373 2.64 21.516 2.664 ;
     RECT  21.373 2.664 21.564 2.736 ;
     RECT  21.373 2.736 21.516 2.76 ;
     RECT  21.373 2.76 21.564 2.832 ;
     RECT  21.373 2.832 21.516 2.856 ;
     RECT  21.373 2.856 21.564 2.928 ;
     RECT  21.373 2.928 21.516 2.952 ;
     RECT  21.373 2.952 21.564 3.024 ;
     RECT  21.373 3.024 21.516 3.048 ;
     RECT  21.373 3.048 21.564 3.12 ;
     RECT  21.373 3.12 21.516 3.144 ;
     RECT  21.373 3.144 21.564 3.216 ;
     RECT  21.373 3.216 21.516 3.24 ;
     RECT  21.373 3.24 21.564 3.312 ;
     RECT  21.373 3.312 21.516 3.336 ;
     RECT  21.373 3.336 21.564 3.408 ;
     RECT  21.373 3.408 21.516 3.432 ;
     RECT  21.373 3.432 21.564 3.504 ;
     RECT  21.373 3.504 21.516 3.528 ;
     RECT  21.373 3.528 21.564 3.6 ;
     RECT  21.373 3.6 21.516 3.624 ;
     RECT  21.373 3.624 21.564 3.696 ;
     RECT  21.373 3.696 21.516 3.72 ;
     RECT  21.373 3.72 21.564 3.792 ;
     RECT  21.373 3.792 21.516 3.816 ;
     RECT  21.373 3.816 21.564 3.888 ;
     RECT  21.373 3.888 21.516 3.912 ;
     RECT  21.373 3.912 21.564 3.984 ;
     RECT  21.373 3.984 21.516 4.008 ;
     RECT  21.373 4.008 21.564 4.08 ;
     RECT  21.373 4.08 21.516 4.104 ;
     RECT  21.373 4.104 21.564 4.176 ;
     RECT  21.373 4.176 21.516 4.2 ;
     RECT  21.373 4.2 21.564 4.272 ;
     RECT  21.373 4.272 21.516 4.296 ;
     RECT  21.373 4.296 21.564 4.368 ;
     RECT  21.373 4.368 21.516 4.392 ;
     RECT  21.373 4.392 21.564 4.464 ;
     RECT  21.373 4.464 21.516 4.488 ;
     RECT  21.373 4.488 21.564 4.56 ;
     RECT  21.373 4.56 21.516 4.584 ;
     RECT  21.373 4.584 21.564 4.656 ;
     RECT  21.373 4.656 21.516 4.68 ;
     RECT  21.373 4.68 21.564 4.752 ;
     RECT  21.373 4.752 21.516 4.776 ;
     RECT  21.373 4.776 21.564 4.848 ;
     RECT  21.373 4.848 21.516 4.872 ;
     RECT  21.373 4.872 21.564 4.944 ;
     RECT  21.373 4.944 21.516 4.968 ;
     RECT  21.373 4.968 21.564 5.04 ;
     RECT  21.373 5.04 21.516 5.064 ;
     RECT  21.373 5.064 21.564 5.136 ;
     RECT  21.373 5.136 21.516 5.16 ;
     RECT  21.373 5.16 21.564 5.232 ;
     RECT  21.373 5.232 21.516 5.256 ;
     RECT  21.373 5.256 21.564 5.328 ;
     RECT  21.373 5.328 21.516 5.352 ;
     RECT  21.373 5.352 21.564 5.424 ;
     RECT  21.373 5.424 21.516 5.448 ;
     RECT  21.373 5.448 21.564 5.52 ;
     RECT  21.373 5.52 21.516 5.544 ;
     RECT  21.373 5.544 21.564 5.616 ;
     RECT  21.373 5.616 21.516 5.64 ;
     RECT  21.373 5.64 21.564 5.712 ;
     RECT  21.373 5.712 21.516 5.736 ;
     RECT  21.373 5.736 21.564 5.808 ;
     RECT  21.373 5.808 21.516 5.832 ;
     RECT  21.373 5.832 21.564 5.904 ;
     RECT  21.373 5.904 21.516 5.928 ;
     RECT  21.373 5.928 21.564 6 ;
     RECT  21.373 6 21.516 6.024 ;
     RECT  21.373 6.024 21.564 6.096 ;
     RECT  21.373 6.096 21.516 6.12 ;
     RECT  21.373 6.12 21.564 6.192 ;
     RECT  21.373 6.192 21.516 6.216 ;
     RECT  21.373 6.216 21.564 6.288 ;
     RECT  21.373 6.288 21.516 6.312 ;
     RECT  21.373 6.312 21.564 6.384 ;
     RECT  21.373 6.384 21.516 6.408 ;
     RECT  21.373 6.408 21.564 6.48 ;
     RECT  21.373 6.48 21.516 6.504 ;
     RECT  21.373 6.504 21.564 6.576 ;
     RECT  21.373 6.576 21.516 6.6 ;
     RECT  21.373 6.6 21.564 6.672 ;
     RECT  21.373 6.672 21.516 6.696 ;
     RECT  21.373 6.696 21.564 6.768 ;
     RECT  21.373 6.768 21.516 6.792 ;
     RECT  21.373 6.792 21.564 6.864 ;
     RECT  21.373 6.864 21.516 6.888 ;
     RECT  21.373 6.888 21.564 6.96 ;
     RECT  21.373 6.96 21.516 6.984 ;
     RECT  21.373 6.984 21.564 7.056 ;
     RECT  21.373 7.056 21.516 7.08 ;
     RECT  21.373 7.08 21.564 7.152 ;
     RECT  21.373 7.152 21.516 7.176 ;
     RECT  21.373 7.176 21.564 7.248 ;
     RECT  21.373 7.248 21.516 7.272 ;
     RECT  21.373 7.272 21.564 7.344 ;
     RECT  21.373 7.344 21.516 7.368 ;
     RECT  21.373 7.368 21.564 7.44 ;
     RECT  21.373 7.44 21.516 7.464 ;
     RECT  21.373 7.464 21.564 7.536 ;
     RECT  21.373 7.536 21.516 7.56 ;
     RECT  21.373 7.56 21.564 7.632 ;
     RECT  21.373 7.632 21.516 7.656 ;
     RECT  21.373 7.656 21.564 7.728 ;
     RECT  21.373 7.728 21.516 7.752 ;
     RECT  21.373 7.752 21.564 7.824 ;
     RECT  21.373 7.824 21.516 7.848 ;
     RECT  21.373 7.848 21.564 7.92 ;
     RECT  21.373 7.92 21.516 7.944 ;
     RECT  21.373 7.944 21.564 8.016 ;
     RECT  21.373 8.016 21.516 8.04 ;
     RECT  21.373 8.04 21.564 8.112 ;
     RECT  21.373 8.112 21.516 8.136 ;
     RECT  21.373 8.136 21.564 8.208 ;
     RECT  21.373 8.208 21.516 8.232 ;
     RECT  21.373 8.232 21.564 8.304 ;
     RECT  21.373 8.304 21.516 8.328 ;
     RECT  21.373 8.328 21.564 8.4 ;
     RECT  21.373 8.4 21.516 8.424 ;
     RECT  21.373 8.424 21.564 8.496 ;
     RECT  21.373 8.496 21.516 8.52 ;
     RECT  21.373 8.52 21.564 8.592 ;
     RECT  21.373 8.592 21.516 8.616 ;
     RECT  21.373 8.616 21.564 8.688 ;
     RECT  21.373 8.688 21.516 8.712 ;
     RECT  21.373 8.712 21.564 8.784 ;
     RECT  21.373 8.784 21.516 8.808 ;
     RECT  21.373 8.808 21.564 8.88 ;
     RECT  21.373 8.88 21.516 8.904 ;
     RECT  21.373 8.904 21.564 8.976 ;
     RECT  21.373 8.976 21.516 9 ;
     RECT  21.373 9 21.564 9.072 ;
     RECT  21.373 9.072 21.516 9.096 ;
     RECT  21.373 9.096 21.564 9.168 ;
     RECT  21.373 9.168 21.516 9.192 ;
     RECT  21.373 9.192 21.564 9.264 ;
     RECT  21.373 9.264 21.516 9.288 ;
     RECT  21.373 9.288 21.564 9.36 ;
     RECT  21.373 9.36 21.516 9.384 ;
     RECT  21.373 9.384 21.564 9.456 ;
     RECT  21.373 9.456 21.516 9.48 ;
     RECT  21.373 9.48 21.564 9.552 ;
     RECT  21.373 9.552 21.516 9.576 ;
     RECT  21.373 9.576 21.564 9.648 ;
     RECT  21.373 9.648 21.516 9.672 ;
     RECT  21.373 9.672 21.564 9.744 ;
     RECT  21.373 9.744 21.516 9.768 ;
     RECT  21.373 9.768 21.564 9.84 ;
     RECT  21.373 9.84 21.516 9.864 ;
     RECT  21.373 9.864 21.564 9.936 ;
     RECT  21.373 9.936 21.516 9.96 ;
     RECT  21.373 9.96 21.564 10.032 ;
     RECT  21.373 10.032 21.516 10.056 ;
     RECT  21.373 10.056 21.564 10.128 ;
     RECT  21.373 10.128 21.516 10.152 ;
     RECT  21.373 10.152 21.564 10.224 ;
     RECT  21.373 10.224 21.516 10.248 ;
     RECT  21.373 10.248 21.564 10.32 ;
     RECT  21.373 10.32 21.516 10.344 ;
     RECT  21.373 10.344 21.564 10.416 ;
     RECT  21.373 10.416 21.516 10.44 ;
     RECT  21.373 10.44 21.564 10.512 ;
     RECT  21.373 10.512 21.516 10.536 ;
     RECT  21.373 10.536 21.564 10.608 ;
     RECT  21.373 10.608 21.516 10.632 ;
     RECT  21.373 10.632 21.564 10.704 ;
     RECT  21.373 10.704 21.516 10.728 ;
     RECT  21.373 10.728 21.564 10.8 ;
     RECT  21.373 10.8 21.516 10.824 ;
     RECT  21.373 10.824 21.564 10.896 ;
     RECT  21.373 10.896 21.516 10.92 ;
     RECT  21.373 10.92 21.564 10.992 ;
     RECT  21.373 10.992 21.516 11.016 ;
     RECT  21.373 11.016 21.564 11.088 ;
     RECT  21.373 11.088 21.516 11.112 ;
     RECT  21.373 11.112 21.564 11.184 ;
     RECT  21.373 11.184 21.516 11.208 ;
     RECT  21.373 11.208 21.564 11.28 ;
     RECT  21.373 11.28 21.516 11.304 ;
     RECT  21.373 11.304 21.564 11.376 ;
     RECT  21.373 11.376 21.516 11.4 ;
     RECT  21.373 11.4 21.564 11.472 ;
     RECT  21.373 11.472 21.516 11.496 ;
     RECT  21.373 11.496 21.564 11.568 ;
     RECT  21.373 11.568 21.516 11.592 ;
     RECT  21.373 11.592 21.564 11.664 ;
     RECT  21.373 11.664 21.516 11.688 ;
     RECT  21.373 11.688 21.564 11.76 ;
     RECT  21.373 11.76 21.516 11.784 ;
     RECT  21.373 11.784 21.564 11.856 ;
     RECT  21.373 11.856 21.516 11.88 ;
     RECT  21.373 11.88 21.564 11.952 ;
     RECT  21.373 11.952 21.516 11.976 ;
     RECT  21.373 11.976 21.564 12.048 ;
     RECT  21.373 12.048 21.516 12.072 ;
     RECT  21.373 12.072 21.564 12.144 ;
     RECT  21.373 12.144 21.516 12.168 ;
     RECT  21.373 12.168 21.564 12.24 ;
     RECT  21.373 12.24 21.516 12.264 ;
     RECT  21.373 12.264 21.564 12.336 ;
     RECT  21.373 12.336 21.516 12.36 ;
     RECT  21.373 12.36 21.564 12.432 ;
     RECT  21.373 12.432 21.516 12.456 ;
     RECT  21.373 12.456 21.564 12.528 ;
     RECT  21.373 12.528 21.516 12.552 ;
     RECT  21.373 12.552 21.564 12.624 ;
     RECT  21.373 12.624 21.516 12.648 ;
     RECT  21.373 12.648 21.564 12.72 ;
     RECT  21.373 12.72 21.516 12.744 ;
     RECT  21.373 12.744 21.564 12.816 ;
     RECT  21.373 12.816 21.516 12.84 ;
     RECT  21.373 12.84 21.564 12.912 ;
     RECT  21.373 12.912 21.516 12.936 ;
     RECT  21.373 12.936 21.564 13.008 ;
     RECT  21.373 13.008 21.516 13.032 ;
     RECT  21.373 13.032 21.564 13.104 ;
     RECT  21.373 13.104 21.516 13.128 ;
     RECT  21.373 13.128 21.564 13.2 ;
     RECT  21.373 13.2 21.516 13.224 ;
     RECT  21.373 13.224 21.564 13.296 ;
     RECT  21.373 13.296 21.516 13.32 ;
     RECT  21.373 13.32 21.564 13.392 ;
     RECT  21.373 13.392 21.516 13.416 ;
     RECT  21.373 13.416 21.564 13.488 ;
     RECT  21.373 13.488 21.516 13.512 ;
     RECT  21.373 13.512 21.564 13.584 ;
     RECT  21.373 13.584 21.516 13.608 ;
     RECT  21.373 13.608 21.564 13.68 ;
     RECT  21.373 13.68 21.516 13.704 ;
     RECT  21.373 13.704 21.564 13.776 ;
     RECT  21.373 13.776 21.516 13.8 ;
     RECT  21.373 13.8 21.564 13.872 ;
     RECT  21.373 13.872 21.516 13.896 ;
     RECT  21.373 13.896 21.564 13.968 ;
     RECT  21.373 13.968 21.516 13.992 ;
     RECT  21.373 13.992 21.564 14.064 ;
     RECT  21.373 14.064 21.516 14.088 ;
     RECT  21.373 14.088 21.564 14.16 ;
     RECT  21.373 14.16 21.516 14.184 ;
     RECT  21.373 14.184 21.564 14.256 ;
     RECT  21.373 14.256 21.516 14.28 ;
     RECT  21.373 14.28 21.564 14.352 ;
     RECT  21.373 14.352 21.516 14.376 ;
     RECT  21.373 14.376 21.564 14.448 ;
     RECT  21.373 14.448 21.516 14.472 ;
     RECT  21.373 14.472 21.564 14.544 ;
     RECT  21.373 14.544 21.516 14.568 ;
     RECT  21.373 14.568 21.564 14.64 ;
     RECT  21.373 14.64 21.516 14.664 ;
     RECT  21.373 14.664 21.564 14.736 ;
     RECT  21.373 14.736 21.516 14.76 ;
     RECT  21.373 14.76 21.564 14.832 ;
     RECT  21.373 14.832 21.516 14.856 ;
     RECT  21.373 14.856 21.564 14.928 ;
     RECT  21.373 14.928 21.516 14.952 ;
     RECT  21.373 14.952 21.564 15.024 ;
     RECT  21.373 15.024 21.516 15.048 ;
     RECT  21.373 15.048 21.564 15.12 ;
     RECT  21.373 15.12 21.516 15.144 ;
     RECT  21.373 15.144 21.564 15.216 ;
     RECT  21.373 15.216 21.516 15.24 ;
     RECT  21.373 15.24 21.564 15.312 ;
     RECT  21.373 15.312 21.516 15.336 ;
     RECT  21.373 15.336 21.564 15.408 ;
     RECT  21.373 15.408 21.516 15.432 ;
     RECT  21.373 15.432 21.564 15.504 ;
     RECT  21.373 15.504 21.516 15.528 ;
     RECT  21.373 15.528 21.564 15.6 ;
     RECT  21.373 15.6 21.516 15.624 ;
     RECT  21.373 15.624 21.564 15.696 ;
     RECT  21.373 15.696 21.516 15.72 ;
     RECT  21.373 15.72 21.564 15.792 ;
     RECT  21.373 15.792 21.516 15.816 ;
     RECT  21.373 15.816 21.564 15.888 ;
     RECT  21.373 15.888 21.516 15.912 ;
     RECT  21.373 15.912 21.564 15.984 ;
     RECT  21.373 15.984 21.516 16.008 ;
     RECT  21.373 16.008 21.564 16.08 ;
     RECT  21.373 16.08 21.516 16.104 ;
     RECT  21.373 16.104 21.564 16.176 ;
     RECT  21.373 16.176 21.516 16.2 ;
     RECT  21.373 16.2 21.564 16.272 ;
     RECT  21.373 16.272 21.516 16.296 ;
     RECT  21.373 16.296 21.564 16.368 ;
     RECT  21.373 16.368 21.516 16.392 ;
     RECT  21.373 16.392 21.564 16.464 ;
     RECT  21.373 16.464 21.516 16.488 ;
     RECT  21.373 16.488 21.564 16.56 ;
     RECT  21.373 16.56 21.516 16.584 ;
     RECT  21.373 16.584 21.564 16.656 ;
     RECT  21.373 16.656 21.516 16.68 ;
     RECT  21.373 16.68 21.564 16.752 ;
     RECT  21.373 16.752 21.516 16.776 ;
     RECT  21.373 16.776 21.564 16.848 ;
     RECT  21.373 16.848 21.516 16.872 ;
     RECT  21.373 16.872 21.564 16.944 ;
     RECT  21.373 16.944 21.516 16.968 ;
     RECT  21.373 16.968 21.564 17.04 ;
     RECT  21.373 17.04 21.516 17.064 ;
     RECT  21.373 17.064 21.564 17.136 ;
     RECT  21.373 17.136 21.516 17.16 ;
     RECT  21.373 17.16 21.564 17.232 ;
     RECT  21.373 17.232 21.516 17.256 ;
     RECT  21.373 17.256 21.564 17.328 ;
     RECT  21.373 17.328 21.516 17.352 ;
     RECT  21.373 17.352 21.564 17.424 ;
     RECT  21.373 17.424 21.516 17.448 ;
     RECT  21.373 17.448 21.564 17.52 ;
     RECT  21.373 17.52 21.516 17.544 ;
     RECT  21.373 17.544 21.564 17.616 ;
     RECT  21.373 17.616 21.516 17.64 ;
     RECT  21.373 17.64 21.564 17.712 ;
     RECT  21.373 17.712 21.516 17.736 ;
     RECT  21.373 17.736 21.564 17.808 ;
     RECT  21.373 17.808 21.516 17.832 ;
     RECT  21.373 17.832 21.564 17.904 ;
     RECT  21.373 17.904 21.516 17.928 ;
     RECT  21.373 17.928 21.564 18 ;
     RECT  21.373 18 21.516 18.024 ;
     RECT  21.373 18.024 21.564 18.096 ;
     RECT  21.373 18.096 21.516 18.12 ;
     RECT  21.373 18.12 21.564 18.192 ;
     RECT  21.373 18.192 21.516 18.216 ;
     RECT  21.373 18.216 21.564 18.288 ;
     RECT  21.373 18.288 21.516 18.312 ;
     RECT  21.373 18.312 21.564 18.384 ;
     RECT  21.373 18.384 21.516 18.408 ;
     RECT  21.373 18.408 21.564 18.48 ;
     RECT  21.373 18.48 21.516 18.504 ;
     RECT  21.373 18.504 21.564 18.576 ;
     RECT  21.373 18.576 21.516 18.6 ;
     RECT  21.373 18.6 21.564 18.672 ;
     RECT  21.373 18.672 21.516 18.696 ;
     RECT  21.373 18.696 21.564 18.768 ;
     RECT  21.373 18.768 21.516 18.792 ;
     RECT  21.373 18.792 21.564 18.864 ;
     RECT  21.373 18.864 21.516 18.888 ;
     RECT  21.373 18.888 21.564 18.96 ;
     RECT  21.373 18.96 21.516 18.984 ;
     RECT  21.373 18.984 21.564 19.056 ;
     RECT  21.373 19.056 21.516 19.08 ;
     RECT  21.373 19.08 21.564 19.92 ;
     RECT  21.373 19.92 21.516 19.944 ;
     RECT  21.373 19.944 21.564 20.016 ;
     RECT  21.373 20.016 21.516 20.04 ;
     RECT  21.373 20.04 21.564 20.112 ;
     RECT  21.373 20.112 21.516 20.136 ;
     RECT  21.373 20.136 21.564 20.208 ;
     RECT  21.373 20.208 21.516 20.232 ;
     RECT  21.373 20.232 21.564 20.304 ;
     RECT  21.373 20.304 21.516 20.328 ;
     RECT  21.373 20.328 21.564 20.4 ;
     RECT  21.373 20.4 21.516 20.424 ;
     RECT  21.373 20.424 21.564 20.496 ;
     RECT  21.373 20.496 21.516 20.52 ;
     RECT  21.373 20.52 21.564 20.592 ;
     RECT  21.373 20.592 21.516 20.616 ;
     RECT  21.373 20.616 21.564 20.688 ;
     RECT  21.373 20.688 21.516 20.712 ;
     RECT  21.373 20.712 21.564 20.784 ;
     RECT  21.373 20.784 21.516 20.808 ;
     RECT  21.373 20.808 21.564 20.88 ;
     RECT  21.373 20.88 21.516 20.904 ;
     RECT  21.373 20.904 21.564 20.976 ;
     RECT  21.373 20.976 21.516 21 ;
     RECT  21.373 21 21.564 21.072 ;
     RECT  21.373 21.072 21.516 21.096 ;
     RECT  21.373 21.096 21.564 21.168 ;
     RECT  21.373 21.168 21.516 21.192 ;
     RECT  21.373 21.192 21.564 21.264 ;
     RECT  21.373 21.264 21.516 21.288 ;
     RECT  21.373 21.288 21.564 21.36 ;
     RECT  21.373 21.36 21.516 21.384 ;
     RECT  21.373 21.384 21.564 21.456 ;
     RECT  21.373 21.456 21.516 21.48 ;
     RECT  21.373 21.48 21.564 21.552 ;
     RECT  21.373 21.552 21.516 21.576 ;
     RECT  21.373 21.576 21.564 21.648 ;
     RECT  21.373 21.648 21.516 21.672 ;
     RECT  21.373 21.672 21.564 21.744 ;
     RECT  21.373 21.744 21.516 21.768 ;
     RECT  21.373 21.768 21.564 21.84 ;
     RECT  21.373 21.84 21.516 21.864 ;
     RECT  21.373 21.864 21.564 21.936 ;
     RECT  21.373 21.936 21.516 21.96 ;
     RECT  21.373 21.96 21.564 22.032 ;
     RECT  21.373 22.032 21.516 22.056 ;
     RECT  21.373 22.056 21.564 22.128 ;
     RECT  21.373 22.128 21.516 22.152 ;
     RECT  21.373 22.152 21.564 22.224 ;
     RECT  21.373 22.224 21.516 22.248 ;
     RECT  21.373 22.248 21.564 22.32 ;
     RECT  21.373 22.32 21.516 22.344 ;
     RECT  21.373 22.344 21.564 22.416 ;
     RECT  21.373 22.416 21.516 22.44 ;
     RECT  21.373 22.44 21.564 22.512 ;
     RECT  21.373 22.512 21.516 22.536 ;
     RECT  21.373 22.536 21.564 22.608 ;
     RECT  21.373 22.608 21.516 22.632 ;
     RECT  21.373 22.632 21.564 22.704 ;
     RECT  21.373 22.704 21.516 22.728 ;
     RECT  21.373 22.728 21.564 22.8 ;
     RECT  21.373 22.8 21.516 22.824 ;
     RECT  21.373 22.824 21.564 22.896 ;
     RECT  21.373 22.896 21.516 22.92 ;
     RECT  21.373 22.92 21.564 22.992 ;
     RECT  21.373 22.992 21.516 23.016 ;
     RECT  21.373 23.016 21.564 23.088 ;
     RECT  21.373 23.088 21.516 23.112 ;
     RECT  21.373 23.112 21.564 23.184 ;
     RECT  21.373 23.184 21.516 23.208 ;
     RECT  21.373 23.208 21.564 23.28 ;
     RECT  21.373 23.28 21.516 23.304 ;
     RECT  21.373 23.304 21.564 23.376 ;
     RECT  21.373 23.376 21.516 23.4 ;
     RECT  21.373 23.4 21.564 23.472 ;
     RECT  21.373 23.472 21.516 23.496 ;
     RECT  21.373 23.496 21.564 23.568 ;
     RECT  21.373 23.568 21.516 23.592 ;
     RECT  21.373 23.592 21.564 23.664 ;
     RECT  21.373 23.664 21.516 23.688 ;
     RECT  21.373 23.688 21.564 23.76 ;
     RECT  21.373 23.76 21.516 23.784 ;
     RECT  21.373 23.784 21.564 23.856 ;
     RECT  21.373 23.856 21.516 23.88 ;
     RECT  21.373 23.88 21.564 23.952 ;
     RECT  21.373 23.952 21.516 23.976 ;
     RECT  21.373 23.976 21.564 24.048 ;
     RECT  21.373 24.048 21.516 24.072 ;
     RECT  21.373 24.072 21.564 24.144 ;
     RECT  21.373 24.144 21.516 24.168 ;
     RECT  21.373 24.168 21.564 24.24 ;
     RECT  21.373 24.24 21.516 24.264 ;
     RECT  21.373 24.264 21.564 24.336 ;
     RECT  21.373 24.336 21.516 24.36 ;
     RECT  21.373 24.36 21.564 24.432 ;
     RECT  21.373 24.432 21.516 24.456 ;
     RECT  21.373 24.456 21.564 24.528 ;
     RECT  21.373 24.528 21.516 24.552 ;
     RECT  18.904 26.064 21.516 26.088 ;
     RECT  18.904 26.088 21.564 26.16 ;
     RECT  18.904 26.16 21.516 26.184 ;
     RECT  18.904 26.184 21.564 26.256 ;
     RECT  18.904 26.256 21.516 26.28 ;
     RECT  18.904 26.28 21.564 26.352 ;
     RECT  18.904 26.352 21.516 26.376 ;
     RECT  18.904 26.376 21.564 26.448 ;
     RECT  18.904 26.448 21.516 26.472 ;
     RECT  18.904 26.472 21.564 26.544 ;
     RECT  18.904 26.544 21.516 26.568 ;
     RECT  18.904 26.568 21.564 26.64 ;
     RECT  18.904 26.64 21.516 26.664 ;
     RECT  18.904 26.664 21.564 26.736 ;
     RECT  18.904 26.736 21.516 26.76 ;
     RECT  18.904 26.76 21.564 26.832 ;
     RECT  18.904 26.832 21.516 26.856 ;
     RECT  18.904 26.856 21.564 26.928 ;
     RECT  18.904 26.928 21.516 26.952 ;
     RECT  18.904 26.952 21.564 27.024 ;
     RECT  18.904 27.024 21.516 27.048 ;
     RECT  18.904 27.048 21.564 27.12 ;
     RECT  18.904 27.12 21.516 27.144 ;
     RECT  18.904 27.144 21.564 27.216 ;
     RECT  18.904 27.216 21.516 27.24 ;
     RECT  18.904 27.24 21.564 27.312 ;
     RECT  18.904 27.312 21.516 27.336 ;
     RECT  18.904 27.336 21.564 27.408 ;
     RECT  18.904 27.408 21.516 27.432 ;
     RECT  18.904 27.432 21.564 27.504 ;
     RECT  18.904 27.504 21.516 27.528 ;
     RECT  18.904 27.528 21.564 27.6 ;
     RECT  18.904 27.6 21.516 27.624 ;
     RECT  18.904 27.624 21.564 27.696 ;
     RECT  18.904 27.696 21.516 27.72 ;
     RECT  18.904 27.72 21.564 27.792 ;
     RECT  18.904 27.792 21.516 27.816 ;
     RECT  18.904 27.816 21.564 27.888 ;
     RECT  18.904 27.888 21.516 27.912 ;
     RECT  18.904 27.912 21.564 27.984 ;
     RECT  18.904 27.984 21.516 28.008 ;
     RECT  18.904 28.008 21.564 28.08 ;
     RECT  18.904 28.08 21.516 28.104 ;
     RECT  18.904 28.104 21.564 28.176 ;
     RECT  18.904 28.176 21.516 28.2 ;
     RECT  18.904 28.2 21.564 28.272 ;
     RECT  18.904 28.272 21.516 28.296 ;
     RECT  18.904 28.296 21.564 28.368 ;
     RECT  18.904 28.368 21.516 28.392 ;
     RECT  18.904 28.392 21.564 28.464 ;
     RECT  18.904 28.464 21.516 28.488 ;
     RECT  18.904 28.488 21.564 28.56 ;
     RECT  18.904 28.56 21.516 28.584 ;
     RECT  18.904 28.584 21.564 28.656 ;
     RECT  18.904 28.656 21.516 28.68 ;
     RECT  18.904 28.68 21.564 28.752 ;
     RECT  18.904 28.752 21.516 28.776 ;
     RECT  18.904 28.776 21.564 28.848 ;
     RECT  18.904 28.848 21.516 28.872 ;
     RECT  18.904 28.872 21.564 28.944 ;
     RECT  18.904 28.944 21.516 28.968 ;
     RECT  18.904 28.968 21.564 29.04 ;
     RECT  18.904 29.04 21.516 29.064 ;
     RECT  18.904 29.064 21.564 29.136 ;
     RECT  18.904 29.136 21.516 29.16 ;
     RECT  18.904 29.16 21.564 29.232 ;
     RECT  18.904 29.232 21.516 29.256 ;
     RECT  18.904 29.256 21.564 29.328 ;
     RECT  18.904 29.328 21.516 29.352 ;
     RECT  18.904 29.352 21.564 29.424 ;
     RECT  18.904 29.424 21.516 29.448 ;
     RECT  18.904 29.448 21.564 29.52 ;
     RECT  18.904 29.52 21.516 29.544 ;
     RECT  18.904 29.544 21.564 29.616 ;
     RECT  18.904 29.616 21.516 29.64 ;
     RECT  18.904 29.64 21.564 29.712 ;
     RECT  18.904 29.712 21.516 29.736 ;
     RECT  18.904 29.736 21.564 29.808 ;
     RECT  18.904 29.808 21.516 29.832 ;
     RECT  18.904 29.832 21.564 29.904 ;
     RECT  18.904 29.904 21.516 29.928 ;
     RECT  18.904 29.928 21.564 30 ;
     RECT  18.904 30 21.516 30.024 ;
     RECT  18.904 30.024 21.564 30.096 ;
     RECT  18.904 30.096 21.516 30.12 ;
     RECT  18.904 30.12 21.564 30.192 ;
     RECT  18.904 30.192 21.516 30.216 ;
     RECT  18.904 30.216 21.564 30.288 ;
     RECT  18.904 30.288 21.516 30.312 ;
     RECT  18.904 30.312 21.564 30.384 ;
     RECT  18.904 30.384 21.516 30.408 ;
     RECT  18.904 30.408 21.564 30.48 ;
     RECT  18.904 30.48 21.516 30.504 ;
     RECT  18.904 30.504 21.564 30.576 ;
     RECT  18.904 30.576 21.516 30.6 ;
     RECT  18.904 30.6 21.564 30.672 ;
     RECT  18.904 30.672 21.516 30.696 ;
     RECT  18.904 30.696 21.564 30.768 ;
     RECT  18.904 30.768 21.516 30.792 ;
     RECT  18.904 30.792 21.564 30.864 ;
     RECT  18.904 30.864 21.516 30.888 ;
     RECT  18.904 30.888 21.564 30.96 ;
     RECT  18.904 30.96 21.516 30.984 ;
     RECT  18.904 30.984 21.564 31.056 ;
     RECT  18.904 31.056 21.516 31.08 ;
     RECT  18.904 31.08 21.564 31.152 ;
     RECT  18.904 31.152 21.516 31.176 ;
     RECT  18.904 31.176 21.564 31.248 ;
     RECT  18.904 31.248 21.516 31.272 ;
     RECT  18.904 31.272 21.564 31.344 ;
     RECT  18.904 31.344 21.516 31.368 ;
     RECT  18.904 31.368 21.564 31.44 ;
     RECT  18.904 31.44 21.516 31.464 ;
     RECT  18.904 31.464 21.564 31.536 ;
     RECT  18.904 31.536 21.516 31.56 ;
     RECT  18.904 31.56 21.564 31.632 ;
     RECT  18.904 31.632 21.516 31.656 ;
     RECT  18.904 31.656 21.564 31.728 ;
     RECT  18.904 31.728 21.516 31.752 ;
     RECT  18.904 31.752 21.564 31.824 ;
     RECT  18.904 31.824 21.516 31.848 ;
     RECT  18.904 31.848 21.564 31.92 ;
     RECT  18.904 31.92 21.516 31.944 ;
     RECT  18.904 31.944 21.564 32.016 ;
     RECT  18.904 32.016 21.516 32.04 ;
     RECT  18.904 32.04 21.564 32.112 ;
     RECT  18.904 32.112 21.516 32.136 ;
    LAYER M5 ;
     RECT  13.032 0.016 13.104 0.084 ;
     RECT  13.008 0.084 13.128 0.131 ;
     RECT  18.48 0.709 18.504 0.805 ;
     RECT  18.48 0.805 18.792 0.901 ;
     RECT  18.48 0.901 19.368 1.189 ;
     RECT  13.008 0.131 13.032 2.137 ;
     RECT  16.368 2.101 16.392 2.137 ;
     RECT  2.4 2.137 2.52 2.151 ;
     RECT  5.1 2.137 5.22 2.151 ;
     RECT  7.8 2.137 7.92 2.151 ;
     RECT  10.5 2.137 10.62 2.151 ;
     RECT  13.008 2.137 13.32 2.151 ;
     RECT  10.5 2.151 10.812 2.197 ;
     RECT  13.008 2.151 13.512 2.197 ;
     RECT  15.9 2.137 16.392 2.197 ;
     RECT  15.9 2.197 16.44 2.389 ;
     RECT  0.192 2.245 0.216 2.531 ;
     RECT  15.9 2.389 17.064 2.533 ;
     RECT  18.192 1.189 19.368 2.533 ;
     RECT  10.032 2.197 10.812 2.677 ;
     RECT  15.9 2.533 19.368 2.725 ;
     RECT  10.032 2.677 11.688 2.773 ;
     RECT  15.9 2.725 19.656 2.773 ;
     RECT  9.552 2.773 11.688 2.821 ;
     RECT  15.792 2.773 19.656 2.821 ;
     RECT  2.4 2.151 2.712 2.869 ;
     RECT  2.304 2.869 2.712 3.107 ;
     RECT  13.008 2.197 14.328 3.107 ;
     RECT  13.008 3.107 14.136 3.443 ;
     RECT  9.36 2.821 11.688 3.829 ;
     RECT  9.36 3.829 11.976 3.925 ;
     RECT  13.008 3.443 13.512 3.925 ;
     RECT  21.408 3.589 21.432 3.971 ;
     RECT  15.792 2.821 19.944 4.451 ;
     RECT  2.4 3.107 2.712 4.501 ;
     RECT  7.8 2.151 8.112 4.549 ;
     RECT  6.816 4.549 8.112 4.691 ;
     RECT  2.4 4.501 2.808 5.365 ;
     RECT  15.9 4.451 19.944 5.509 ;
     RECT  15.9 5.509 20.136 5.605 ;
     RECT  15.312 5.605 20.136 5.651 ;
     RECT  21.264 5.989 21.288 6.131 ;
     RECT  15.312 5.651 19.944 6.133 ;
     RECT  7.8 4.691 8.112 6.373 ;
     RECT  14.784 6.133 19.944 6.515 ;
     RECT  9.36 3.925 13.512 6.565 ;
     RECT  7.44 6.373 8.112 6.707 ;
     RECT  7.8 6.707 8.112 6.853 ;
     RECT  9.12 6.565 13.656 6.853 ;
     RECT  2.4 5.365 3.24 6.947 ;
     RECT  7.8 6.853 13.656 7.043 ;
     RECT  7.8 7.043 8.52 7.139 ;
     RECT  0.144 7.189 0.168 7.379 ;
     RECT  9.888 7.043 13.656 7.475 ;
     RECT  14.784 6.515 19.368 7.475 ;
     RECT  9.888 7.475 13.512 7.715 ;
     RECT  5.1 2.151 5.412 7.813 ;
     RECT  11.952 7.715 13.512 7.859 ;
     RECT  21.408 7.717 21.432 7.907 ;
     RECT  0.192 7.765 0.216 7.955 ;
     RECT  1.248 7.669 1.272 7.957 ;
     RECT  1.152 7.957 1.272 8.003 ;
     RECT  9.888 7.715 10.92 8.149 ;
     RECT  7.8 7.139 8.112 8.245 ;
     RECT  9.792 8.149 10.92 8.245 ;
     RECT  1.152 8.003 1.176 8.291 ;
     RECT  7.68 8.245 8.112 8.341 ;
     RECT  9.12 8.245 10.92 8.341 ;
     RECT  7.68 8.341 10.92 8.435 ;
     RECT  14.88 7.475 19.368 8.435 ;
     RECT  15.264 8.435 19.368 8.771 ;
     RECT  12.528 7.859 13.512 8.917 ;
     RECT  9.648 8.435 10.92 9.493 ;
     RECT  12.096 8.917 13.512 9.493 ;
     RECT  7.68 8.435 8.52 9.731 ;
     RECT  15.696 8.771 19.368 9.877 ;
     RECT  7.8 9.731 8.52 10.117 ;
     RECT  9.648 9.493 13.512 10.117 ;
     RECT  21.408 9.253 21.432 10.211 ;
     RECT  2.4 6.947 2.712 10.261 ;
     RECT  2.4 10.261 2.856 10.501 ;
     RECT  2.304 10.501 2.856 10.835 ;
     RECT  7.8 10.117 13.512 10.885 ;
     RECT  15.216 9.877 19.368 10.885 ;
     RECT  15.216 10.885 19.896 10.981 ;
     RECT  15.216 10.981 20.232 11.173 ;
     RECT  7.8 10.885 13.656 11.507 ;
     RECT  15.216 11.173 20.472 11.605 ;
     RECT  1.152 11.461 1.176 11.747 ;
     RECT  14.88 11.605 20.472 11.987 ;
     RECT  4.944 7.813 5.412 12.131 ;
     RECT  14.976 11.987 20.472 12.275 ;
     RECT  15.168 12.275 20.472 12.517 ;
     RECT  2.304 10.835 2.712 13.043 ;
     RECT  2.4 13.043 2.712 13.285 ;
     RECT  7.8 11.507 13.608 13.333 ;
     RECT  4.992 12.131 5.412 13.525 ;
     RECT  0.144 13.333 0.168 13.619 ;
     RECT  4.128 13.525 5.412 13.667 ;
     RECT  15.168 12.517 20.52 14.003 ;
     RECT  1.248 13.861 1.272 14.195 ;
     RECT  4.992 13.667 5.412 14.533 ;
     RECT  6.768 13.477 6.792 14.533 ;
     RECT  15.168 14.003 20.328 15.061 ;
     RECT  14.976 15.061 20.328 15.251 ;
     RECT  15.072 15.251 20.328 15.299 ;
     RECT  21.408 14.293 21.432 15.395 ;
     RECT  2.4 13.285 2.856 15.589 ;
     RECT  4.992 14.533 6.792 15.779 ;
     RECT  0.144 15.541 0.168 15.827 ;
     RECT  4.992 15.779 6.264 16.019 ;
     RECT  2.4 15.589 3.336 16.645 ;
     RECT  2.4 16.645 3.48 16.789 ;
     RECT  15.072 15.299 19.944 16.837 ;
     RECT  0.144 16.837 0.168 16.981 ;
     RECT  0.144 16.981 1.128 17.027 ;
     RECT  4.992 16.019 5.412 17.077 ;
     RECT  1.104 17.027 1.128 17.123 ;
     RECT  2.4 16.789 3.624 17.125 ;
     RECT  4.944 17.077 5.736 17.125 ;
     RECT  7.8 13.333 13.656 17.173 ;
     RECT  14.64 16.837 19.944 17.173 ;
     RECT  2.4 17.125 5.736 17.267 ;
     RECT  4.992 17.267 5.736 17.987 ;
     RECT  2.4 17.267 3.336 18.035 ;
     RECT  21.408 17.893 21.432 18.083 ;
     RECT  7.8 17.173 19.944 18.467 ;
     RECT  7.8 18.467 19.368 20.339 ;
     RECT  0.144 20.101 0.168 20.387 ;
     RECT  4.992 17.987 5.412 20.725 ;
     RECT  7.8 20.339 19.176 21.011 ;
     RECT  7.8 21.011 18.912 21.251 ;
     RECT  4.272 20.725 5.412 21.539 ;
     RECT  2.4 18.035 2.712 21.781 ;
     RECT  4.512 21.539 5.412 21.923 ;
     RECT  9.984 21.251 18.912 22.165 ;
     RECT  7.8 21.251 8.952 22.261 ;
     RECT  9.984 22.165 19.368 22.261 ;
     RECT  2.4 21.781 2.808 23.123 ;
     RECT  7.8 22.261 19.368 23.171 ;
     RECT  5.1 21.923 5.412 23.269 ;
     RECT  7.8 23.171 19.32 23.411 ;
     RECT  4.896 23.269 5.412 23.749 ;
     RECT  21.408 23.125 21.432 23.891 ;
     RECT  4.512 23.749 5.412 23.941 ;
     RECT  4.416 23.941 5.412 24.131 ;
     RECT  2.4 23.123 2.712 24.181 ;
     RECT  4.512 24.131 5.412 24.373 ;
     RECT  2.208 24.181 2.712 24.467 ;
     RECT  7.8 23.411 18.912 24.563 ;
     RECT  9.984 24.563 18.912 24.757 ;
     RECT  4.512 24.373 5.544 24.803 ;
     RECT  4.896 24.803 5.544 24.899 ;
     RECT  9.984 24.757 19.128 25.045 ;
     RECT  5.1 24.899 5.544 25.429 ;
     RECT  0.144 21.733 0.168 25.523 ;
     RECT  2.4 24.467 2.712 25.621 ;
     RECT  7.8 24.563 8.856 25.813 ;
     RECT  9.984 25.045 19.176 25.813 ;
     RECT  2.4 25.621 2.856 25.861 ;
     RECT  7.8 25.813 19.176 26.101 ;
     RECT  7.8 26.101 19.368 26.243 ;
     RECT  7.8 26.243 9.144 26.531 ;
     RECT  5.1 25.429 5.688 26.581 ;
     RECT  2.4 25.861 3.384 26.869 ;
     RECT  2.304 26.869 3.384 27.059 ;
     RECT  1.152 26.773 1.176 27.107 ;
     RECT  4.848 26.581 5.928 27.445 ;
     RECT  7.8 26.531 8.856 27.971 ;
     RECT  1.296 28.309 1.32 28.499 ;
     RECT  4.848 27.445 6.264 28.547 ;
     RECT  10.5 26.243 19.368 28.547 ;
     RECT  4.848 28.547 5.928 28.595 ;
     RECT  7.8 27.971 8.112 28.693 ;
     RECT  7.584 28.693 8.112 28.835 ;
     RECT  0.144 28.693 0.168 28.979 ;
     RECT  14.832 28.547 19.368 29.075 ;
     RECT  10.5 28.547 13.608 29.557 ;
     RECT  4.944 28.595 5.928 29.605 ;
     RECT  10.5 29.557 13.704 29.699 ;
     RECT  10.5 29.699 11.736 29.747 ;
     RECT  4.608 29.605 5.928 30.085 ;
     RECT  14.832 29.075 18.912 30.085 ;
     RECT  4.56 30.085 5.928 30.275 ;
     RECT  12.912 29.699 13.704 30.325 ;
     RECT  14.832 30.085 19.368 30.325 ;
     RECT  4.56 30.275 5.736 30.563 ;
     RECT  2.4 27.059 3.384 30.755 ;
     RECT  7.8 28.835 8.112 30.757 ;
     RECT  4.56 30.563 5.688 31.235 ;
     RECT  12.912 30.325 19.368 31.379 ;
     RECT  7.68 30.757 8.112 31.381 ;
     RECT  4.56 31.235 5.412 31.427 ;
     RECT  7.296 31.381 8.112 31.523 ;
     RECT  1.152 31.429 1.176 31.715 ;
     RECT  7.392 31.523 8.112 31.907 ;
     RECT  14.88 31.379 19.368 31.955 ;
     RECT  14.88 31.955 17.592 32.003 ;
     RECT  2.4 30.755 2.712 32.409 ;
     RECT  5.1 31.427 5.412 32.409 ;
     RECT  7.8 31.907 8.112 32.409 ;
     RECT  10.5 29.747 10.812 32.409 ;
     RECT  13.2 31.379 13.512 32.409 ;
     RECT  15.9 32.003 16.212 32.409 ;
     RECT  18.6 31.955 18.912 32.409 ;
     RECT  2.4 32.409 2.52 32.423 ;
     RECT  5.1 32.409 5.22 32.423 ;
     RECT  7.8 32.409 7.92 32.423 ;
     RECT  10.5 32.409 10.62 32.423 ;
     RECT  13.2 32.409 13.32 32.423 ;
     RECT  15.9 32.409 16.02 32.423 ;
     RECT  18.6 32.409 18.72 32.423 ;
     RECT  3.984 31.909 4.008 32.531 ;
     RECT  17.064 2.389 18.192 2.533 ;
     RECT  11.688 2.677 13.008 3.829 ;
     RECT  8.112 2.773 9.552 2.821 ;
     RECT  14.328 2.773 15.792 3.107 ;
     RECT  8.112 2.821 9.36 6.565 ;
     RECT  19.944 3.589 21.408 3.971 ;
     RECT  11.976 3.829 13.008 3.925 ;
     RECT  15.792 4.451 15.9 5.605 ;
     RECT  5.412 4.549 6.816 4.691 ;
     RECT  19.944 5.651 20.136 5.989 ;
     RECT  19.944 5.989 21.264 6.131 ;
     RECT  13.512 6.133 14.784 6.565 ;
     RECT  8.112 6.565 9.12 6.853 ;
     RECT  13.656 6.565 14.784 7.475 ;
     RECT  8.52 7.043 9.888 7.139 ;
     RECT  8.112 7.139 9.888 8.149 ;
     RECT  13.512 7.475 14.88 8.435 ;
     RECT  1.272 7.669 2.4 8.003 ;
     RECT  10.92 7.715 11.952 7.859 ;
     RECT  0.216 7.765 1.248 7.955 ;
     RECT  10.92 7.859 12.528 8.917 ;
     RECT  21.408 7.907 21.42 9.253 ;
     RECT  1.152 7.955 1.248 7.957 ;
     RECT  1.176 8.003 2.4 8.291 ;
     RECT  8.112 8.149 9.792 8.245 ;
     RECT  8.112 8.245 9.12 8.341 ;
     RECT  8.52 8.435 9.648 10.117 ;
     RECT  15.216 8.435 15.264 8.771 ;
     RECT  15.216 8.771 15.696 9.877 ;
     RECT  10.92 8.917 12.096 9.493 ;
     RECT  1.176 11.461 2.304 11.747 ;
     RECT  13.608 11.507 13.656 11.605 ;
     RECT  13.608 11.605 14.88 11.987 ;
     RECT  13.608 11.987 14.976 12.275 ;
     RECT  4.944 12.131 4.992 13.525 ;
     RECT  13.608 12.275 15.168 13.333 ;
     RECT  2.304 13.043 2.4 13.861 ;
     RECT  13.656 13.333 15.168 15.061 ;
     RECT  5.412 13.477 6.768 14.533 ;
     RECT  6.792 13.477 7.8 15.779 ;
     RECT  2.856 13.525 4.128 13.667 ;
     RECT  1.272 13.861 2.4 14.195 ;
     RECT  20.328 14.003 20.52 14.293 ;
     RECT  20.328 14.293 21.408 15.299 ;
     RECT  13.656 15.061 14.976 15.251 ;
     RECT  13.656 15.251 15.072 16.837 ;
     RECT  19.944 15.299 21.408 15.395 ;
     RECT  5.412 16.019 5.736 17.077 ;
     RECT  3.48 16.645 4.992 16.789 ;
     RECT  3.624 16.789 4.992 17.077 ;
     RECT  13.656 16.837 14.64 17.173 ;
     RECT  1.128 16.981 2.4 17.123 ;
     RECT  3.624 17.077 4.944 17.125 ;
     RECT  19.944 17.893 21.408 18.083 ;
     RECT  18.912 21.011 19.176 22.165 ;
     RECT  8.952 21.251 9.984 22.261 ;
     RECT  4.896 21.923 5.1 23.269 ;
     RECT  18.912 23.411 19.128 24.757 ;
     RECT  8.856 24.563 9.984 25.813 ;
     RECT  9.144 26.243 10.5 26.531 ;
     RECT  3.384 26.581 4.848 28.595 ;
     RECT  1.176 26.773 2.4 26.869 ;
     RECT  1.176 26.869 2.304 27.059 ;
     RECT  1.176 27.059 2.4 27.107 ;
     RECT  1.296 27.107 2.4 28.309 ;
     RECT  1.32 28.309 2.4 28.499 ;
     RECT  13.608 28.547 14.832 29.557 ;
     RECT  3.384 28.595 4.944 29.605 ;
     RECT  18.912 29.075 19.368 30.085 ;
     RECT  13.704 29.557 14.832 30.325 ;
     RECT  3.384 29.605 4.608 30.085 ;
     RECT  11.736 29.699 12.912 29.747 ;
     RECT  3.384 30.085 4.56 30.755 ;
     RECT  2.712 30.755 4.56 31.427 ;
     RECT  13.512 31.379 14.88 32.003 ;
     RECT  2.712 31.427 5.1 31.909 ;
     RECT  1.176 31.429 2.4 31.715 ;
     RECT  2.712 31.909 3.984 32.409 ;
     RECT  4.008 31.909 5.1 32.423 ;
     RECT  17.592 31.955 18.6 32.003 ;
     RECT  2.52 32.409 3.984 32.423 ;
  END
END hbfd_rly_304_EW_rrfc
END LIBRARY
